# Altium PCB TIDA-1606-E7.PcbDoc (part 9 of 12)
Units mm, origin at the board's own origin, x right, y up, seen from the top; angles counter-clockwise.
Board outline 270 x 345 mm, 4 copper layers (Top Layer, Signal Layer 1, Signal Layer 2, Bottom Layer), stack 1.69 mm thick; 1263 components, 574 nets, 3595 pads, 4069 vias.
Unrouted connection lines stored in the file: 1719.

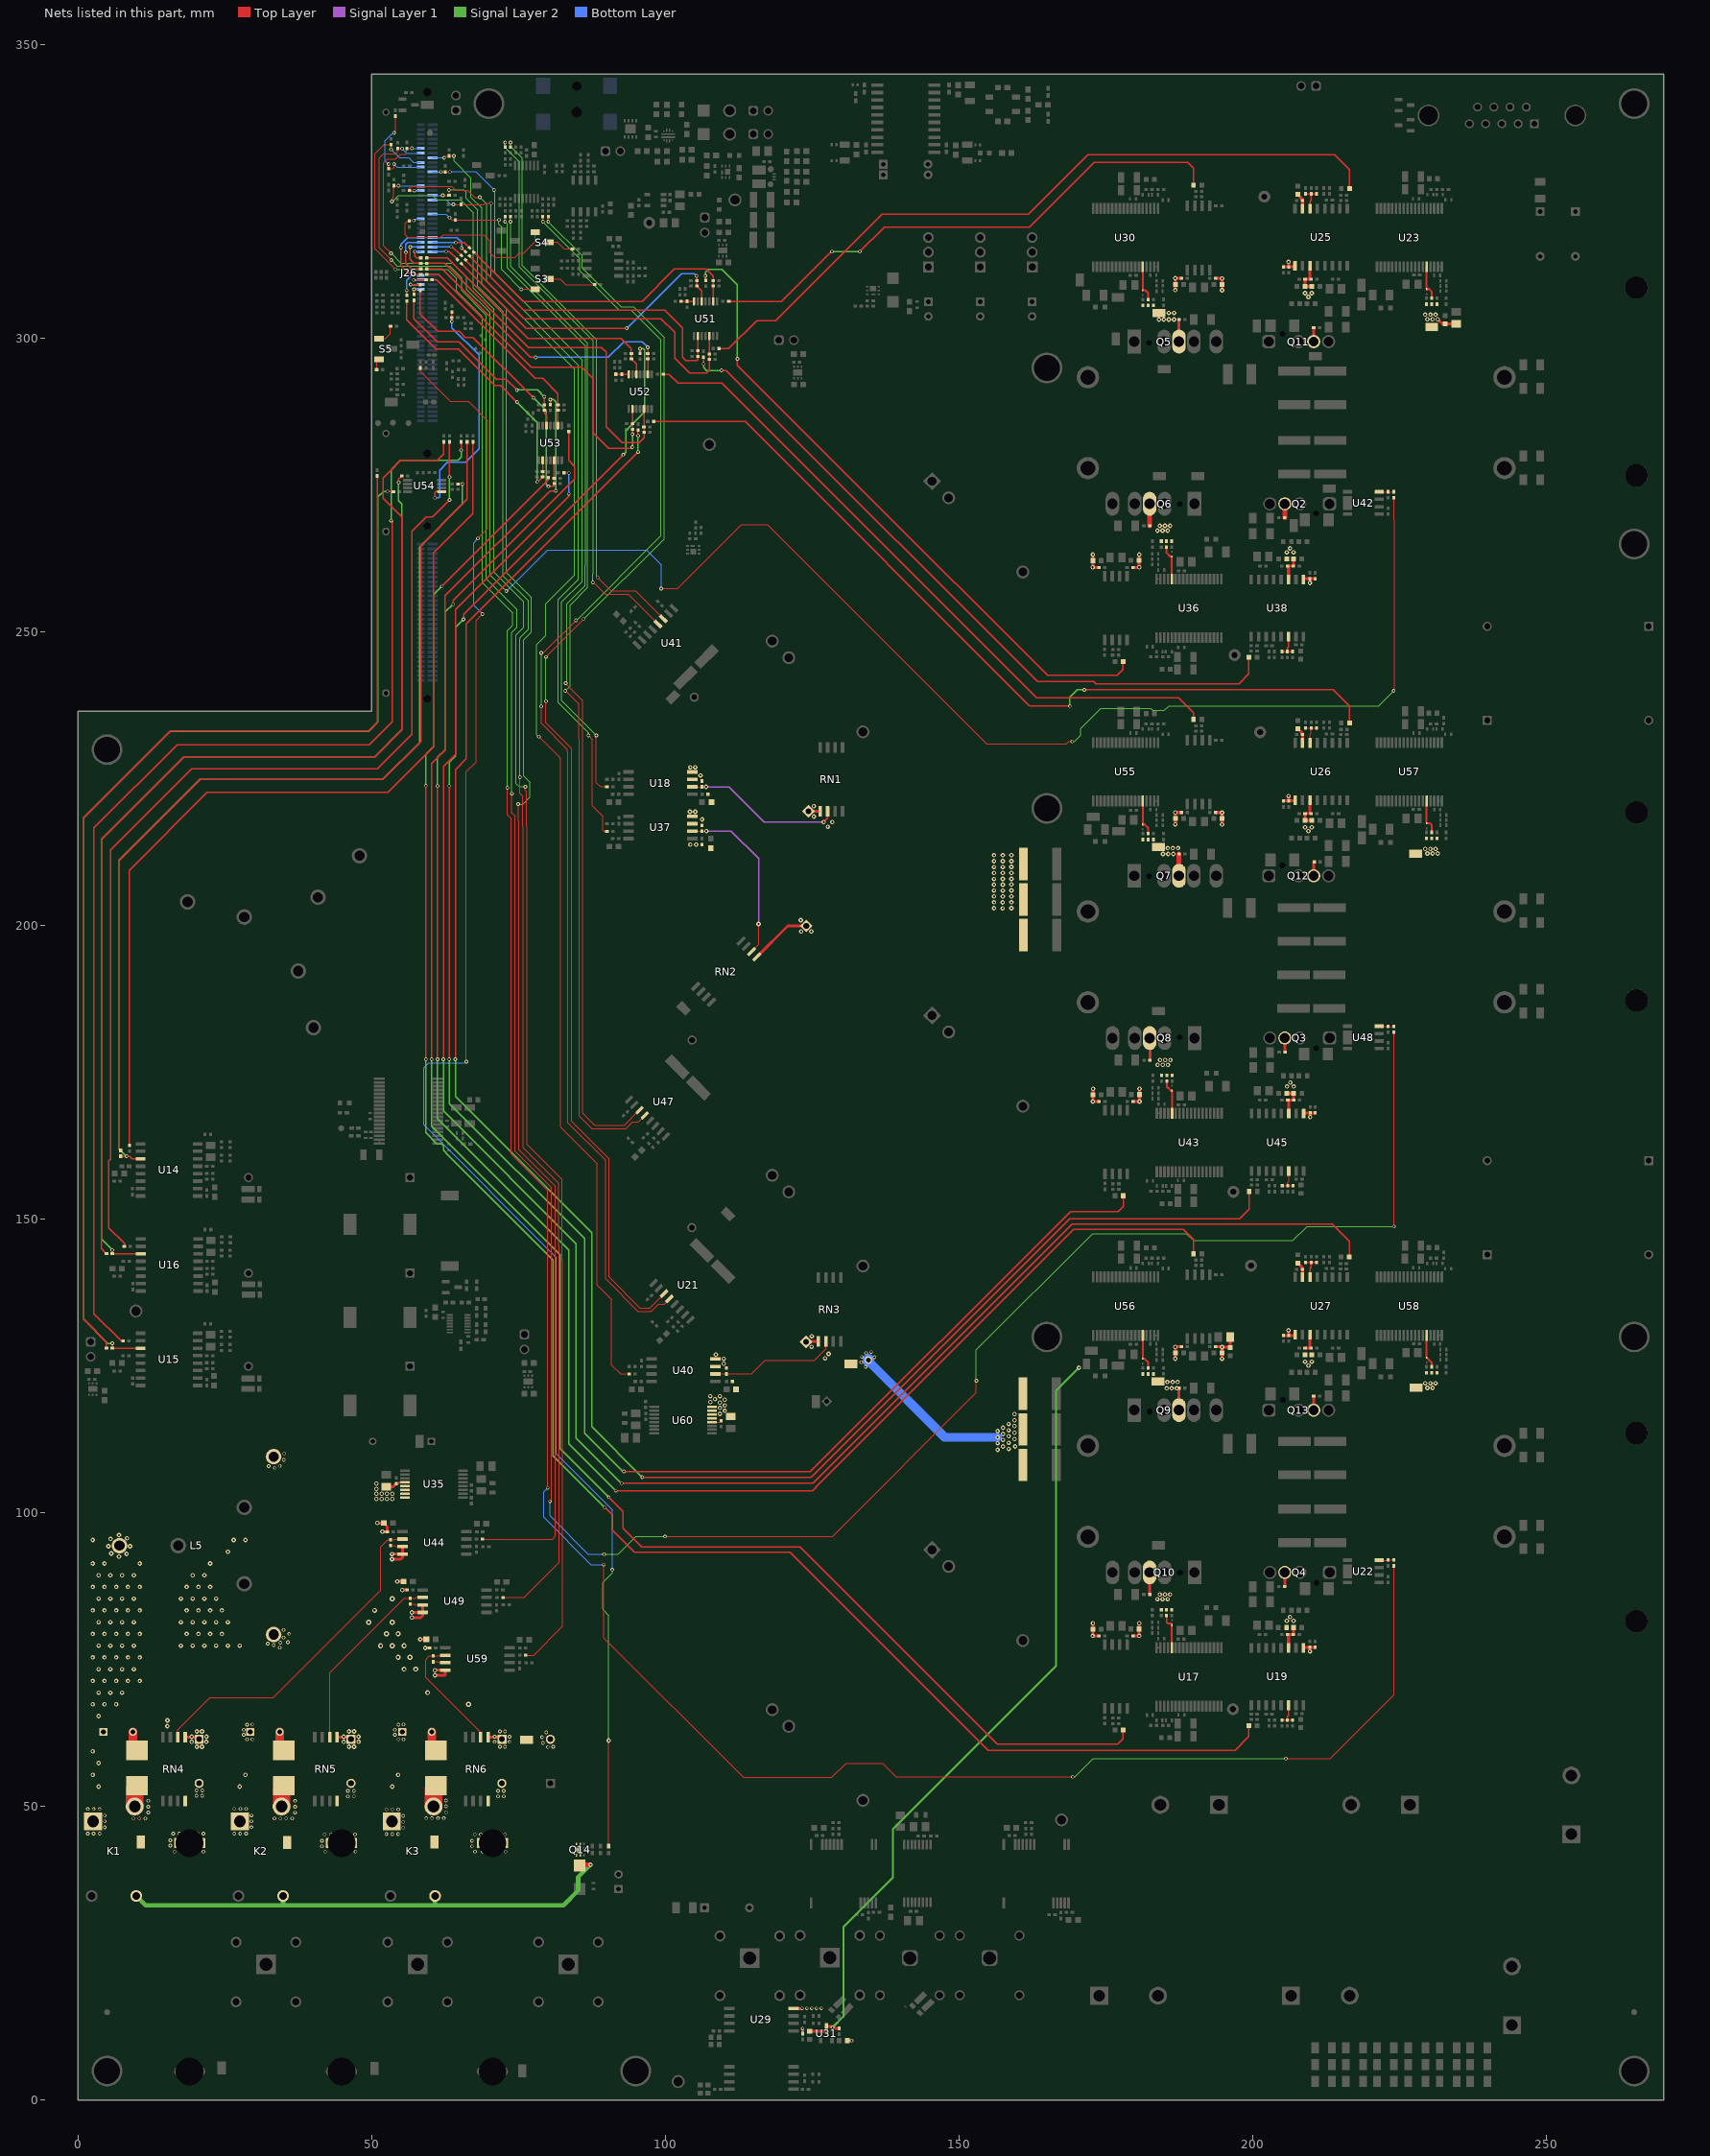
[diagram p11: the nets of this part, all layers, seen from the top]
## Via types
v1: diameter 0.762, hole 0.356, Top Layer to Bottom Layer, tented both sides, 2809 vias
v2: diameter 0.61, hole 0.356, Top Layer to Bottom Layer, tented both sides, 1209 vias
v3: diameter 0.864, hole 0.406, Top Layer to Bottom Layer, tented both sides, 15 vias
v4: diameter 0.5, hole 0.2, Top Layer to Bottom Layer, tented both sides, 12 vias
v5: diameter 0.5, hole 0.2, Top Layer to Bottom Layer, 12 vias
v6: diameter 0.305, hole 0.152, Top Layer to Bottom Layer, tented both sides, 12 vias

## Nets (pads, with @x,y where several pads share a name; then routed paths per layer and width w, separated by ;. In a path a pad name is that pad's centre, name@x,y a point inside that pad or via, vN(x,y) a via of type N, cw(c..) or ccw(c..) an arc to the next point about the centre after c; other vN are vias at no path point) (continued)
PIN42_AIN: C489.1 J26.79 S4.1 | length 33
  Top Layer w0.203: C489.1@56.447,319.827 C489.1@56.474,319.8 ; v2(57.202,320.099) 56.552,320.099 C489.1@56.452,320 56.142,320 55.728,319.585 55.728,317.646 56.127,317.246 61.796,317.246 62.171,317.621 69.135,317.621 70.106,316.65 70.106,314.672 70.967,313.811 74.46,313.811 75.169,314.52 75.923,314.52 77.901,316.499 S4.1@77.901,318.135
  Bottom Layer w0.203: v2(57.202,320.099) 57.202,320.128 57.459,320.385 J26.79@58.402,320.385
PIN76: R449.2 S5.1 | length 3.6
  Top Layer w0.203: S5.1@51.302,299.987 52.416,299.987 53.25,300.821 R449.2@53.25,302.1
PIN96: R467.2 S5.3 | length 2
  Top Layer w0.203: R467.2@50.886,294.7 50.886,296.071 S5.3@51.302,296.487
PTCR_L1: R89.2 R90.1 | length 3.7
  Top Layer w1.5: R90.1@9.375,60.181 R89.2@9.375,62.729
  Top Layer w2: R90.1@9.375,60.181 R90.1@10.221,59.336
PTCR_L2: R91.2 R92.1 | length 3.5
  Top Layer w1.5: R92.1@34.374,59.711 R91.2@34.374,62.729
  Top Layer w2: R92.1@34.374,59.711 R92.1@34.749,59.336
PTCR_L3: R94.2 R95.1 | length 3.5
  Top Layer w1.5: R95.1@60.26,59.711 R94.2@60.26,62.729
  Top Layer w2: R95.1@60.26,59.711 R95.1@60.635,59.336
PWM1_BUF_L1: R101.2 R246.2 | length 120.7
  Top Layer w0.229: v2(106.546,295.672) R101.2@106.546,296.846 ; v2(109.587,294.573) 110.44,294.573 115.666,289.347 163.408,241.605 172.943,241.605 173.348,241.2 197.7,241.2 199.398,242.898 R246.2@199.398,245.739
  Signal Layer 2 w0.229: v2(106.546,295.672) 106.546,295.113 107.086,294.573 v2(109.587,294.573)
  Bottom Layer w0.229: v2@109.386,294.573 v2(109.587,294.573)
PWM1_BUF_L2: R106.2 R264.2 | length 329.7
  Top Layer w0.229: v2(64.288,177.254) 64.288,223.6 64.288,226.588 66.154,228.454 66.154,251.424 95.4,280.67 v2(95.406,280.67) ; v2(95.406,283.439) R106.2@95.406,284.429 ; v2(96.123,106.1) 124.9,106.1 125,106.2 168.876,150.076 197.776,150.076 199.439,151.739 R264.2@199.439,154.773
  Signal Layer 2 w0.229: v2(64.288,177.254) 64.288,170.968 87.522,147.734 87.522,114.689 96.111,106.1 v2(96.123,106.1) ; v2(95.406,280.67) v2(95.406,283.439)
PWM1_BUF_L3: R112.2 R157.2 | length 328.3
  Top Layer w0.229: v2(59.254,177.254) v2(59.254,223.854) ; v2(61.972,257.785) 80.115,275.928 R112.2@80.115,276.32 ; v2(89.739,100.921) 89.739,100.965 90.955,99.749 90.955,97.125 94.78,93.3 121.3,93.3 155,59.6 197.071,59.6 199.4,61.929 R157.2@199.4,63.778
  Signal Layer 2 w0.229: v2(59.254,177.254) 59.254,164.774 61.148,162.88 61.916,162.88 62.28,162.515 62.28,161.748 63.116,160.912 63.117,160.912 80.922,143.108 80.922,109.738 v2(89.739,100.921) ; v2(59.254,223.854) 59.254,229.154 60.585,230.485 60.585,256.399 v2(61.972,257.785)
PWM1_L1: C461.1 R326.1 R376.2 U51.2 | length 53.2
  Top Layer w0.229: R326.1@66.716,314.065 75.956,304.825 99.945,304.825 102.95,301.821 102.95,296.842 103.124,296.667 103.124,296.665 103.522,296.267 103.525,296.267 103.534,296.257 105.38,296.257 105.593,296.47 R376.2@105.593,296.946 C461.1@105.593,297.895 U51.2@105.593,300.431
PWM1_L2: C465.1 R343.2 R389.2 U52.2 | length 59.3
  Top Layer w0.229: R343.2@59.402,310.918 61.387,310.918 77.234,295.071 85.81,295.071 87.738,293.143 87.738,283.925 90.363,281.3 94.202,281.3 v2(94.402,281.5) ; v2(94.452,283.7) R389.2@94.452,284.529 C465.1@94.452,285.478 U52.2@94.452,288.013
  Signal Layer 2 w0.229: v2@94.452,281.55 v2(94.452,283.7)
  Bottom Layer w0.229: v2(94.402,281.5) v2@94.452,281.55
PWM1_L3: C471.1 R414.2 R428.2 U53.2 | length 46.9
  Top Layer w0.229: R428.2@56.002,306.368 56.002,303.2 61.002,298.2 64.803,298.2 71.003,292 71.974,292 v2(74.8,289.174) ; v2(78.232,275.59) 78.332,275.59 R414.2@79.162,276.42 U53.2@79.162,279.273
  Signal Layer 2 w0.229: v2(74.8,289.174) 78.232,285.742 v2(78.232,275.59)
PWM1L1: J26.72 R326.2 | length 7.2
  Top Layer w0.229: v2(65.37,315.4) 65.998,314.772 R326.2@66.009,314.772
  Bottom Layer w0.229: J26.72@60.402,317.185 64.602,317.185 65.37,316.418 v2(65.37,315.4)
PWM1L2: J26.71 R343.1 | length 11.7
  Top Layer w0.229: v2(55.002,315.5) 55.002,312.463 56.547,310.918 R343.1@58.271,310.918 ; R343.1@58.402,310.918 R343.1@58.271,310.918 ; R343.1@58.402,311.05 R343.1@58.271,310.918
  Bottom Layer w0.229: v2(55.002,315.5) 55.002,316 56.188,317.185 J26.71@58.402,317.185 J26.71@58.387,317.2
PWM1L3: J26.63 R428.1 | length 5.3
  Top Layer w0.229: R428.1@56.002,307.368 v2(56.002,308.2)
  Bottom Layer w0.229: v2(56.002,308.2) 56.002,309.912 56.876,310.785 J26.63@58.402,310.785
PWM2_BUF_L1: R102.2 R196.2 | length 125.3
  Top Layer w0.229: R102.2@109.193,298.296 110.827,298.296 115.593,303.062 118.808,303.062 136.946,321.2 161.868,321.2 171.998,331.33 213.959,331.33 216.529,328.76 R196.2@216.529,325.518
PWM2_BUF_L2: R107.2 R210.2 | length 144.6
  Top Layer w0.229: R107.2@98.052,285.879 113.643,285.879 161.988,237.534 162.107,237.415 v2(168.91,237.415) ; v2(171.374,240.182) 171.413,240.222 213.765,240.222 216.531,237.456 R210.2@216.531,234.55
  Signal Layer 2 w0.229: v2(168.91,237.415) 168.91,238.91 170.182,240.182 v2(171.374,240.182)
PWM2_BUF_L3: R114.2 R211.2 | length 340.5
  Top Layer w0.203: R114.2@82.762,277.138 v2(83.602,277.138)
  Top Layer w0.229: v2(62.254,177.254) 62.254,225.017 62.254,227.112 64.34,229.198 64.34,253.842 82.98,272.483 82.982,272.483 83.602,273.103 v2(83.602,273.558) ; v2(92.6,105.1) 125.2,105.1 125.9,105.8 169.3,149.2 213.595,149.2 216.495,146.299 R211.2@216.495,143.6
  Signal Layer 2 w0.229: v2(62.254,177.254) 62.254,168.446 84.822,145.878 84.822,112.778 92.5,105.1 v2(92.6,105.1) ; v2(83.602,277.138) v2@83.66,277.081
  Bottom Layer w0.229: v2(83.602,273.558) v2(83.602,277.138)
PWM2_L1: C462.1 R377.2 R399.1 U51.5 | length 58.1
  Top Layer w0.229: R399.1@65.993,313.41 76.003,303.4 99.302,303.4 101.637,301.066 101.637,296.666 104.202,294.1 107.017,294.1 107.543,294.626 C462.1@107.543,297.346 U51.5@107.543,300.431
PWM2_L2: C466.1 R392.2 R404.2 U52.5 | length 62.3
  Top Layer w0.229: R404.2@59.402,312.797 62.464,312.797 76.783,298.478 89.2,298.478 89.963,297.716 89.963,284.992 92.641,282.313 95.627,282.313 96.402,283.088 C466.1@96.402,284.929 U52.5@96.402,288.013
PWM2_L3: C472.1 R415.2 R430.2 U53.5 | length 50.9
  Top Layer w0.229: R430.2@58.302,308.185 58.302,304.2 61.302,301.2 64.952,301.2 65.963,300.189 67.299,300.189 77.565,289.923 v2(77.565,289.936) ; v2(80.115,274.828) 81.119,274.828 81.137,274.846 R415.2@81.137,275.288 81.112,275.263 C472.1@81.112,276.188 U53.5@81.112,279.273
  Signal Layer 2 w0.229: v2(77.565,289.936) 79.784,287.717 79.784,275.159 v2(80.115,274.828)
PWM2L1: J26.68 R399.2 | length 5.5
  Top Layer w0.229: v2(63.602,315.625) 63.778,315.625 R399.2@65.286,314.117
  Bottom Layer w0.229: J26.68@60.402,315.585 60.441,315.625 v2(63.602,315.625)
PWM2L2: J26.67 R404.1 | length 6.1
  Top Layer w0.229: v2@56.67,315.585 v2(56.589,315.585) 56.589,313.454 57.245,312.797 R404.1@58.402,312.797
  Bottom Layer w0.229: v2(56.589,315.585) J26.67@58.402,315.585
PWM2L3: J26.59 R430.1 | length 3.4
  Top Layer w0.229: v2(56.666,309.185) R430.1@58.302,309.185
  Bottom Layer w0.229: v2(56.666,309.185) J26.59@58.402,309.185
PWM3_BUF_L1: R103.2 R224.2 | length 92.3
  Top Layer w0.229: R103.2@110.846,306.331 119.834,306.331 128.304,314.8 v2(128.412,314.8) ; v2(133.148,314.8) 137.348,319 162.054,319 173.054,330 189.016,330 189.975,329.04 R224.2@189.975,326.11
  Signal Layer 2 w0.229: v2(128.412,314.8) v2(133.148,314.8)
PWM3_BUF_L2: R108.2 R226.2 | length 115.3
  Top Layer w0.229: R108.2@99.706,293.913 100.704,293.913 102.218,292.4 109.627,292.4 163.233,238.794 187.468,238.794 189.977,236.285 R226.2@189.977,235.142
PWM3_BUF_L3: R116.2 R242.2 | length 323
  Top Layer w0.229: v2(61.254,177.254) v2(61.254,223.8) ; v2(63.902,254.759) 63.902,255.369 84.625,276.091 84.625,278.224 83.601,279.247 R116.2@83.601,284.173 ; v2(91.6,103.8) 125.066,103.8 126.422,105.156 169.571,148.305 188.248,148.305 189.977,146.576 R242.2@189.977,144.147
  Signal Layer 2 w0.229: v2(61.254,177.254) 61.254,167.146 83.622,144.778 83.622,111.778 v2(91.6,103.8) ; v2(61.254,223.8) 61.254,228.654 62.548,229.948 62.548,253.405 v2(63.902,254.759)
PWM3_L1: C463.1 R379.2 R390.1 U51.9 | length 51.3
  Top Layer w0.229: R390.1@67.407,314.735 75.826,306.316 96.083,306.316 101.584,311.816 106.993,311.816 108.21,310.6 108.21,309.882 R379.2@108.193,309.865 C463.1@108.193,308.945 U51.9@108.193,306.331
PWM3_L2: C467.1 R393.2 R398.2 U52.9 | length 50
  Top Layer w0.229: R393.2@59.402,311.858 62.033,311.858 77.094,296.796 v2(77.978,296.796) ; U52.9@97.052,293.913 C467.1@97.052,296.528 R398.2@97.052,297.448 v2(97.052,298.5)
  Bottom Layer w0.229: v2(77.978,296.796) 90.284,296.796 92.967,299.48 96.073,299.48 v2(97.052,298.5)
PWM3_L3: C473.1 R422.2 R429.2 U53.9 | length 34.9
  Top Layer w0.229: R429.2@60.302,309.985 61.117,309.985 77.902,293.2 79.201,293.2 81.762,290.639 R422.2@81.762,288.707 C473.1@81.762,287.787 U53.9@81.762,285.173
PWM3L1: J26.70 R390.2 | length 6.7
  Top Layer w0.229: v2(64.34,316.362) 65.78,316.362 R390.2@66.7,315.443
  Bottom Layer w0.229: J26.70@60.402,316.385 64.316,316.385 v2(64.34,316.362)
PWM3L2: J26.69 R393.1 | length 8.9
  Top Layer w0.229: v2(55.852,314.7) 55.852,312.874 56.869,311.858 R393.1@58.402,311.858
  Bottom Layer w0.229: v2(55.852,314.7) 55.852,316.063 56.175,316.385 J26.69@58.402,316.385 J26.69@58.388,316.399
PWM3L3: J26.61 R429.1 | length 3.3
  Top Layer w0.229: v2(57.202,309.985) R429.1@59.302,309.985
  Bottom Layer w0.229: v2(57.202,309.985) J26.61@58.402,309.985
PWM4_BUF_L1: R105.2 R260.2 | length 111.2
  Top Layer w0.229: v2(106.865,310.675) 106.865,309.922 R105.2@106.893,309.893 ; v2(112.302,296.523) 112.302,295.46 133.708,274.054 165.136,242.626 174.273,242.626 174.277,242.622 176.95,242.622 177.985,243.658 R260.2@177.985,245
  Signal Layer 2 w0.229: v2(106.865,310.675) 106.865,311.31 107.331,311.776 109.659,311.776 112.302,309.132 v2(112.302,296.523)
PWM4_BUF_L2: R110.2 R268.2 | length 324.3
  Top Layer w0.229: v2(63.254,177.254) v2(63.254,223.8) ; v2(65.681,252.185) 65.681,253.02 v2(92.883,280.223) ; v2(93,107.088) 124.753,107.088 124.765,107.1 169.015,151.35 177.131,151.35 178.027,152.246 R268.2@178.027,154.034 ; R110.2@95.752,297.476 v2(95.752,298.257)
  Signal Layer 2 w0.229: v2(63.254,177.254) 63.254,169.746 86.285,146.715 86.285,113.603 92.8,107.088 v2(93,107.088) ; v2(63.254,223.8) 63.254,227.87 64.34,228.956 64.34,250.844 v2(65.681,252.185) ; v2(92.883,280.223) 93.302,280.642 93.302,284.328 96.5,287.525 96.5,298.028 96.271,298.257 v2(95.752,298.257)
PWM4_BUF_L3: R168.2 R174.2 | length 318.9
  Top Layer w0.229: v2(60.254,177.254) 60.254,226 60.254,227.654 62.548,229.948 62.548,256.188 80.426,274.066 v2(81.393,274.066) ; R168.2@80.462,288.735 v2(80.462,289.597) ; v2(90.4,102.7) 92.802,100.298 92.802,97.416 96.018,94.2 123.003,94.2 156.519,60.684 156.591,60.612 177.031,60.612 177.995,61.577 R174.2@177.995,63.047
  Signal Layer 2 w0.229: v2(60.254,177.254) 60.254,165.846 82.122,143.978 82.122,110.941 90.363,102.7 v2(90.4,102.7) ; v2(80.462,289.597) 80.989,289.597 81.393,289.193 v2(81.393,274.066)
PWM4_L1: C464.1 R378.2 R425.1 U51.12 | length 53.3
  Top Layer w0.229: R425.1@65.334,312.744 76.327,301.752 v2(93.472,301.752) ; v2(105.348,310.675) 105.396,310.627 R378.2@105.396,309.882 C464.1@105.396,308.946 106.243,308.1 U51.12@106.243,306.331
  Bottom Layer w0.229: v2(93.472,301.752) 102.793,311.073 104.95,311.073 v2(105.348,310.675)
PWM4_L2: C468.1 R403.2 R426.2 U52.12 | length 46
  Top Layer w0.229: R426.2@59.402,313.737 62.942,313.737 76.632,300.046 92.47,300.046 94.256,298.26 R403.2@94.256,297.465 C468.1@94.256,296.529 95.102,295.682 U52.12@95.102,293.913
PWM4_L3: C474.1 R424.2 R431.2 U53.12 | length 35.9
  Top Layer w0.229: R431.2@57.241,306.5 57.241,303.362 61.202,299.4 64.902,299.4 71.232,293.07 72.936,293.07 v2(74.76,291.247) ; v2(79.437,290.068) R424.2@79.437,288.707 C474.1@79.437,287.772 79.418,287.753 79.418,287.335 79.812,286.942 U53.12@79.812,285.173
  Signal Layer 2 w0.229: v2(74.76,291.247) 78.258,291.247 v2(79.437,290.068)
PWM4L1: J26.66 R425.2 | length 4.8
  Top Layer w0.229: v2(62.692,314.785) 63.293,314.785 R425.2@64.627,313.451
  Bottom Layer w0.229: J26.66@60.402,314.785 v2(62.692,314.785)
PWM4L2: J26.65 R426.1 | length 2.9
  Top Layer w0.229: v2(57.402,314.8) 57.402,314.068 57.734,313.737 R426.1@58.402,313.737
  Bottom Layer w0.229: v2(57.402,314.8) 58.387,314.8 J26.65@58.402,314.785
PWM4L3: J26.57 R431.1 | length 2
  Top Layer w0.229: R431.1@57.241,307.5 v2(57.241,308.385)
  Bottom Layer w0.229: v2(57.241,308.385) J26.57@58.402,308.385
REF_MID1: C247.1 C248.2 C250.2 C252.1 Q5.3 R85.1 R248.1 R507.2 R511.2 TP52.1 | length 9.9
  Top Layer w0.5: v1(186.876,308.244) C248.2@186.876,309.223 v1(186.876,310.268) C247.1@187.925,310.268 ; Q5.3@187.503,299.48 R85.1@187.503,303.23 ; C250.2@193.736,310.268 194.78,310.268 v1(194.825,310.224) C252.1@194.825,309.223 v1(194.825,308.231)
  other v1: 184.087,303.224 184.924,303.23 185.763,303.224 186.653,303.224 185.763,304.357 186.648,304.357
REF_MID2: C254.1 C255.2 C257.2 C259.1 Q7.3 R86.1 R263.1 R531.2 R565.2 TP53.1 | length 9.9
  Top Layer w0.5: v1(186.878,217.276) C255.2@186.878,218.255 v1(186.878,219.3) C254.1@187.927,219.3 ; C257.2@193.738,219.3 194.782,219.3 v1(194.827,219.255) C259.1@194.827,218.255 v1(194.827,217.263)
  Top Layer w0.8: Q7.3@187.505,208.511 R86.1@187.505,212.262
  other v1: 184.785,212.239 185.661,212.239 186.537,212.239 185.578,213.237 186.454,213.237 187.33,213.237
REF_MID3: C235.1 C236.2 C237.2 C242.1 C261.1 C262.2 C264.2 C266.1 C270.2 Q9.3 R87.1 R254.2 R539.2 R566.1 R567.2 TP57.1 U29.4 U31.3 | length 149.7
  Top Layer w0.5: U29.4@121.85,15.63 v2@123.321,15.63 ; C270.2@123.404,11.357 v2(123.404,12.223) ; C237.2@124.604,11.757 125.699,11.757 125.704,11.752 127.462,11.752 U31.3@127.462,12.606 v2@128.412,12.606 ; v2@128.762,12.257 C235.1@129.619,12.257 ; v1(186.878,126.281) C262.2@186.878,127.26 v1(186.878,128.305) C261.1@187.927,128.305 ; Q9.3@187.505,118.506 R87.1@187.505,121.266 ; C264.2@193.738,128.305 194.782,128.305 v1(194.827,128.26) ; v1(194.827,126.268) C266.1@194.827,127.26 v1(194.827,128.26) ; C242.1@196.216,128.2 196.156,128.26 v1(194.827,128.26)
  Top Layer w0.508: C242.1@196.216,128.2 R254.2@196.216,129.943
  Signal Layer 2 w0.35: v2(128.504,12.405) 130.353,14.254 130.353,29.48 138.8,37.927 138.8,46.175 166.571,73.946 166.571,120.847 v1(170.465,124.742)
  other v1: 185.38,121.249 186.257,121.249 187.133,121.249 185.53,122.311 186.406,122.311 187.282,122.311
  other v2: 131.746,10.157 123.321,15.65 124.14,15.65 124.959,15.65 125.778,15.65 126.597,15.65
REF_SN_L1: C140.1 C141.2 C291.1 C293.2 C296.2 C300.2 C304.1 C307.2 C309.1 Q2.3 Q6.3 R88.1 R93.1 R154.1 R259.2 R277.2 R298.1 U38.1 U38.3 | length 19.7
  Top Layer w0.4: C296.2@205.989,261.258 C291.1@206.977,261.258
  Top Layer w0.5: v1(172.833,263.198) C309.1@172.833,262.198 172.833,261.091 v1(172.792,261.05) 172.813,261.029 C307.2@173.857,261.029 ; C304.1@179.659,261.029 180.704,261.029 v1(180.726,261.05) C141.2@180.726,262.217 v1@180.726,263.052 ; R88.1@205.51,269.474 R88.1@205.517,269.481 ; C296.2@205.989,261.254 206.148,261.095 U38.3@206.148,258.972 U38.3@206.132,258.987 ; C291.1@206.977,261.254 206.977,261.258 206.977,262.435 C293.2@206.992,262.45 ; U38.1@208.688,258.972 208.813,259.098 R298.1@210.664,259.098 ; v1(209.798,258.398) C300.2@209.798,259.098
  Top Layer w0.8: R93.1@182.513,268.1 Q6.3@182.513,271.85 ; R88.1@205.517,269.481 Q2.3@205.517,271.85
  other v1: 180.726,263.198 205.852,263.593 206.992,263.593 206.41,264.264 183.824,267.3 184.7,267.3 185.576,267.3 184.234,268.098 185.11,268.098 185.986,268.098
REF_SN_L2: C241.1 C279.2 C334.1 C336.2 C339.2 C343.2 C347.1 C350.2 C352.1 Q3.3 Q8.3 R99.1 R283.1 R284.2 R320.2 R338.1 R350.1 U45.1 U45.3 | length 20.9
  Top Layer w0.5: v1(172.874,172.232) C352.1@172.874,171.232 172.833,171.191 v1(172.833,170.084) 172.863,170.055 C350.2@173.891,170.055 ; C347.1@179.701,170.063 180.746,170.063 v1(180.767,170.084) C279.2@180.767,171.251 v1(180.767,172.232) ; R350.1@182.555,177.134 Q8.3@182.555,180.842 ; R99.1@205.552,178.508 Q3.3@205.552,180.849 ; C241.1@205.874,171.484 C336.2@207.034,171.484 207.034,170.303 C334.1@207.018,170.288 207.015,170.292 C339.2@206.031,170.292 206.189,170.133 U45.3@206.189,168.006 ; U45.1@208.729,168.006 208.855,168.132 C343.2@209.839,168.132 ; v1(209.839,167.432) C343.2@209.839,168.132 ; R338.1@210.705,168.132 C343.2@209.839,168.132
  other v1: 205.894,172.627 207.034,172.627 206.452,173.298 183.866,176.334 184.742,176.334 185.618,176.334 184.276,177.132 185.151,177.132 186.028,177.132
REF_SN_L3: C147.1 C149.2 C151.1 C152.2 C153.2 C156.2 C160.1 C163.2 C165.1 Q4.3 Q10.3 R80.1 R81.1 R147.1 R149.2 R151.2 R169.1 U19.1 U19.3 | length 19.5
  Top Layer w0.5: v1(172.835,81.234) C165.1@172.835,80.234 172.835,79.128 v1(172.794,79.087) 172.823,79.057 C163.2@173.851,79.057 ; C160.1@179.661,79.065 180.706,79.065 v1(180.728,79.087) C153.2@180.728,80.254 v1(180.728,81.234) ; R81.1@182.515,86.136 Q10.3@182.515,89.887 ; R80.1@205.512,87.51 Q4.3@205.512,89.88 ; U19.3@206.15,77.011 206.15,79.132 206.308,79.29 C147.1@206.979,79.29 206.994,79.306 C149.2@206.994,80.486 ; U19.1@208.69,77.011 208.813,77.134 C156.2@209.8,77.134 ; v1(209.8,76.434) C156.2@209.8,77.134 ; R169.1@210.666,77.134 C156.2@209.8,77.134
  other v1: 205.854,81.63 206.994,81.63 206.412,82.301 183.826,85.336 184.702,85.336 185.578,85.336 184.236,86.134 185.112,86.134 185.988,86.134
REF_VDC-1: C181.1 C187.1 C189.2 C191.1 C192.2 C196.2 Q11.3 R82.1 R186.2 R189.2 R191.2 R208.1 R555.1 TP43.1 U25.1 U25.3 | length 14.2
  Top Layer w0.5: R208.1@205.284,312.208 C196.2@206.152,312.208 ; v1(206.152,313.062) C196.2@206.152,312.208 ; U25.1@207.11,312.208 C196.2@206.152,312.208 ; U25.3@209.8,312.358 209.8,310.231 C192.2@209.959,310.072 C187.1@208.971,310.072 C189.2@208.971,308.895 C191.1@210.098,308.895 ; Q11.3@210.438,299.487 R82.1@210.438,301.856 ; v1(231.55,303.268) 232.318,302.5 C181.1@232.8,302.5 R189.2@234.7,302.5
  other v1: 229.798,303.268 230.674,303.268 229.423,304.068 230.3,304.068 231.176,304.068 209.538,307.066 208.956,307.737 210.096,307.737
REF_VDC-2: C200.1 C202.2 C205.2 C206.1 C209.2 Q12.3 R83.1 R223.1 R253.2 R527.1 R535.2 TP44.1 U26.1 U26.3 | length 10.7
  Top Layer w0.4: C200.1@208.973,219.104 C205.2@209.961,219.104
  Top Layer w0.5: R223.1@205.286,221.264 C209.2@206.154,221.264 ; C209.2@206.154,221.24 C209.2@206.154,221.264 ; v1(206.154,222.093) C209.2@206.154,221.264 ; U26.1@207.137,221.264 C209.2@206.154,221.264 ; C200.1@208.973,219.108 208.973,219.104 C202.2@208.973,217.927 C206.1@210.1,217.927 ; U26.3@209.802,221.39 209.802,219.263 C205.2@209.961,219.104 ; Q12.3@210.433,208.511 210.433,210.881 R83.1@210.44,210.888
  other v1: 229.8,212.3 230.676,212.3 231.552,212.3 229.425,213.1 230.302,213.1 231.178,213.1 209.54,216.097 208.958,216.768 210.098,216.768
REF_VDC-3: C213.1 C215.2 C218.2 C219.1 C228.2 Q13.3 R84.1 R245.1 R302.2 R556.1 R557.2 TP48.1 U27.1 U27.3 | length 8.6
  Top Layer w0.5: R245.1@205.286,130.244 C228.2@206.154,130.244 ; v1(206.154,131.098) C228.2@206.154,130.244 ; U27.1@207.262,130.394 207.112,130.244 C228.2@206.154,130.244 ; C213.1@208.973,128.109 C218.2@209.961,128.109 209.802,128.267 U27.3@209.802,130.394 ; Q13.3@210.433,117.516 210.433,119.895 R84.1@210.438,119.9
  other v1: 229.8,121.305 230.676,121.305 229.425,122.105 230.302,122.105 231.178,122.105 209.54,125.102 208.958,125.773 210.098,125.773
RLAY_1: K1.1 L5.EI R89.1
  other v1: 3.548,53.416 2.548,55.416 3.548,57.416 2.548,59.416 3.548,65.416 2.548,67.416 4.548,67.416 6.548,67.416 3.548,69.416 5.548,69.416 7.548,69.416 2.548,71.416 4.548,71.416 6.548,71.416 8.548,71.416 10.548,71.416 3.548,73.416 5.548,73.416 7.548,73.416 9.548,73.416 2.548,75.416 4.548,75.416 6.548,75.416 8.548,75.416 10.548,75.416 3.548,77.416 5.548,77.416 7.548,77.416 9.548,77.416 2.548,79.416 4.548,79.416 6.548,79.416 8.548,79.416 10.548,79.416 3.548,81.416 5.548,81.416 7.548,81.416 9.548,81.416 2.548,83.416 4.548,83.416 6.548,83.416 8.548,83.416 10.548,83.416 3.548,85.416 5.548,85.416 7.548,85.416 9.548,85.416 2.548,87.416 4.548,87.416 6.548,87.416 8.548,87.416 10.548,87.416 3.548,89.416 5.548,89.416 7.548,89.416 9.548,89.416 2.548,91.416 4.548,91.416 10.548,91.416 7.01,92.601 8.307,93.045 5.707,93.131 5.21,94.345 8.907,94.345 2.548,95.416 5.588,95.595 8.384,95.706 7.01,96.245
  other v2: 1.7,45.399 2.7,45.399 3.7,45.399 4.588,46.486 4.588,47.486 4.588,48.486 1.71,49.6 2.71,49.6 3.71,49.6
RLAY_2: K2.1 L5.EII R91.1
  other v1: 27.548,53.416 28.548,55.416 17.548,77.416 19.548,77.416 21.548,77.416 23.548,77.416 25.548,77.416 27.548,77.416 18.548,79.416 20.548,79.416 22.548,79.416 24.548,79.416 17.548,81.416 19.548,81.416 21.548,81.416 23.548,81.416 25.548,81.416 18.548,83.416 20.548,83.416 22.548,83.416 24.548,83.416 17.548,85.416 19.548,85.416 21.548,85.416 23.548,85.416 18.548,87.416 20.548,87.416 22.548,87.416 19.548,89.416 21.548,89.416 22.548,91.416 25.548,93.416 26.548,95.416 28.548,95.416
  other v2: 26.66,45.41 27.66,45.41 28.66,45.41 29.548,46.497 29.548,47.497 29.548,48.497 26.67,49.611 27.67,49.611 28.67,49.611 28.841,61.479 29.708,61.475 28.25,62.25 28.25,63.087 28.841,63.95 29.708,64 33.548,107.696 32.5,108 34.41,108.041 35.086,109.041 35.155,110.167
RLAY_3: K3.1 L5.EIII R94.1
  other v1: 53.548,53.416 54.548,55.416
  other v2: 52.542,45.335 53.542,45.335 54.542,45.335 55.43,46.422 55.43,47.422 55.43,48.422 52.552,49.536 53.552,49.536 54.552,49.536 54.591,61.479 55.457,61.475 54,62.25 54,63.087 54.591,63.95 55.457,64 34.374,77.072 33.35,77.505 32.35,77.773 34.5,77.934 35.789,78 35.047,78.78 35.998,79.417 35.047,80.1
RLIM: D7.1 R147.2 U17.32 | length 6.2
  Top Layer w0.305: R147.2@185.385,82.534 185.385,81.385 185.571,81.199 186.276,81.199 D7.1@186.276,80.914 U17.32@186.276,77.074
RLIM_MID1: D25.1 R248.2 U30.32 | length 6.2
  Top Layer w0.35: U30.32@181.328,312.215 D25.1@181.328,308.231 181.769,308.231 182.242,307.758 R248.2@182.242,306.646
RLIM_MID2: D26.1 R263.2 U55.32 | length 6.1
  Top Layer w0.35: U55.32@181.33,221.247 D26.1@181.33,217.263 181.639,217.263 182.244,216.658 R263.2@182.244,215.678
RLIM_MID3: D27.1 R566.2 U56.32 | length 6.1
  Top Layer w0.35: U56.32@181.33,130.251 D27.1@181.33,126.268 181.661,126.268 182.244,125.684 R566.2@182.244,124.682
RLIM_SN_L1: D14.1 R154.2 U36.32 | length 6
  Top Layer w0.35: R154.2@185.383,264.498 185.383,263.508 186.014,262.878 D14.1@186.274,262.878 U36.32@186.274,259.035
RLIM_SN_L2: D16.1 R283.2 U43.32 | length 6
  Top Layer w0.35: R283.2@185.424,173.532 185.424,172.598 186.111,171.912 D16.1@186.316,171.912 U43.32@186.316,168.069
RLIM_VDC-1: D19.1 R555.2 U23.32 | length 6
  Top Layer w0.35: U23.32@229.657,312.215 D19.1@229.657,308.426 230.073,308.426 230.555,307.944 R555.2@230.555,306.866
RLIM_VDC-2: D20.1 R527.2 U57.32 | length 6.1
  Top Layer w0.35: U57.32@229.659,221.247 229.659,217.458 230.261,217.458 230.557,217.162 R527.2@230.557,215.898
RLIM_VDC-3: D21.1 R556.2 U58.32 | length 5.7
  Top Layer w0.35: U58.32@229.659,130.251 229.659,126.463 D21.1@229.666,126.456 230.557,125.565 R556.2@230.557,124.902
RST_BOT_L1: C194.1 R200.1 R206.2 U25.14 | length 4.4
  Top Layer w0.229: C194.1@209.078,324.632 R200.1@209.992,324.632 ; U25.14@209.8,322.108 209.8,323.32 209.992,323.512 R200.1@209.992,324.632 ; R206.2@210.906,324.632 R200.1@209.992,324.632
RST_BOT_L2: C207.1 R215.1 R221.2 U26.14 | length 4.4
  Top Layer w0.203: C207.1@209.08,233.664 R215.1@209.994,233.664 ; U26.14@209.802,231.14 209.802,232.553 209.994,232.745 R215.1@209.994,233.664 ; R221.2@210.908,233.664 R215.1@209.994,233.664
RST_BOT_L3: C225.1 R230.1 R237.2 U27.14 | length 4.4
  Top Layer w0.229: C225.1@209.08,142.669 R230.1@209.994,142.669 ; U27.14@209.802,140.144 209.802,141.671 209.994,141.863 R230.1@209.994,142.669 ; R237.2@210.908,142.669 R230.1@209.994,142.669
RST_TOP_L1: C298.1 R291.1 R297.2 U38.14 | length 4.4
  Top Layer w0.229: R297.2@205.042,246.698 R291.1@205.956,246.698 ; U38.14@206.148,249.222 206.148,247.506 205.956,247.314 R291.1@205.956,246.698 ; C298.1@206.87,246.698 R291.1@205.956,246.698
RST_TOP_L2: C341.1 R330.1 R336.2 U45.14 | length 4.4
  Top Layer w0.203: R336.2@205.083,155.732 R330.1@205.997,155.732 ; U45.14@206.189,158.256 206.189,156.448 205.997,156.256 R330.1@205.997,155.732 ; C341.1@206.911,155.732 R330.1@205.997,155.732
RST_TOP_L3: C154.1 R161.1 R167.2 U19.14 | length 4.4
  Top Layer w0.229: R167.2@205.044,64.736 R161.1@205.958,64.736 ; U19.14@206.15,67.261 206.15,65.568 205.958,65.376 R161.1@205.958,64.736 ; C154.1@206.872,64.736 R161.1@205.958,64.736
RY_N: R113.1 R465.2 | length 282.2
  Top Layer w0.203: R465.2@58.317,295 58.317,294.423 63.464,289.276 66.524,289.276 69.8,286 69.8,267.632 v2(68.106,265.938) ; v2(66.154,176.854) 66.154,226.209 67.8,227.855 67.8,251.994 v2(68.89,253.084) ; R113.1@90.4,43.3 v1(90.4,61.25)
  Signal Layer 2 w0.203: v1(90.4,61.25) 90.4,82.55 89.364,83.586 89.364,88.156 91,89.792 v2(91,90.365)
  Bottom Layer w0.203: v2(66.154,176.854) 65.916,176.616 59.716,176.616 58.9,175.8 58.9,166.1 81.502,143.498 81.502,110.046 91,100.549 v2@91,90.164 ; v2(68.106,265.938) 67.407,265.239 67.407,254.568 v2(68.89,253.084)
SD_CLKI: R427.1 R432.1 U54.1 | length 41.1
  Top Layer w0.229: v2(60.8,272.9) 60.8,273.778 60.949,273.928 U54.1@61.951,273.928 U54.1@62,273.878 ; v2(63.686,302.9) R432.1@63.686,303.6 R427.1@63.686,304.518 R427.1@63.686,304.6
  Bottom Layer w0.229: v2(60.8,272.9) 61.468,272.9 61.602,273.034 61.602,277.576 62.926,278.9 66.024,278.9 68.326,281.202 68.326,297.204 63.686,301.844 v2(63.686,302.9)
SD_CLKI_IN_L1: R140.2 R471.1 | length 163.5
  Top Layer w0.229: R140.2@7.3,161.756 7,162.056 7,211.041 20.898,224.939 51.939,224.939 58.402,231.402 58.402,264.738 66.302,272.638 R471.1@66.302,282.42
SD_CLKI_IN_L2: R143.2 R477.1 | length 190.6
  Top Layer w0.229: R143.2@4.881,128.068 4.881,129.119 1,133 1,218.378 15.796,233.174 49.569,233.174 51.002,234.607 R477.1@51.002,276.6
SD_CLKI_IN_L3: R145.2 R481.1 | length 188.2
  Top Layer w0.229: R145.2@4.881,144.147 4,145.027 4,147.576 4,214.693 18.107,228.8 50.6,228.8 55.151,233.351 55.151,269.652 51.962,272.84 51.962,276.262 54.951,279.251 61.247,279.251 62.322,280.327 R481.1@62.322,282.42
SD_CLKI_OUT_L1: R140.1 R170.2 U14.11 | length 161.8
  Top Layer w0.229: R140.1@7.3,160.756 v2(8.3,160.756) 8.828,160.756 9.254,160.33 U14.11@10.691,160.33 U14.11@10.661,160.3 ; R170.2@64.737,275.228 v2(65.475,275.228)
  Signal Layer 2 w0.229: v2(8.3,160.756) 7,162.056 7,211.1 20.8,224.9 51.9,224.9 58.166,231.166 58.166,264.502 65.475,271.811 v2(65.475,275.228)
SD_CLKI_OUT_L2: R143.1 R192.2 U15.11 | length 195.8
  Top Layer w0.229: v2(5.881,128.895) R143.1@5.881,128.068 5.885,128.072 U15.11@10.691,128.072 ; v2(52.727,273.961) 53.704,273.961 R192.2@53.737,273.928
  Signal Layer 2 w0.229: v2(5.881,128.895) 5.105,128.895 1,133 1,218.378 15.757,233.135 49.53,233.135 51.118,234.722 51.118,273.015 52.063,273.961 v2(52.727,273.961)
SD_CLKI_OUT_L3: R145.1 R209.2 U16.11 | length 178.8
  Top Layer w0.229: v2(5.881,144.781) R145.1@5.881,144.147 10.732,144.147 U16.11@10.733,144.145 ; v2(54.632,275.5) 54.632,276.081 R209.2@55.151,276.6
  Signal Layer 2 w0.229: v2(5.881,144.781) 4,146.662 4,146.9 4,214.693 18.107,228.8 50.6,228.8 55.202,233.402 55.202,271.8 54.632,272.37 v2(54.632,275.5)
SD_Data_I_PCC_L1: R133.2 R469.1 | length 162.1
  Top Layer w0.229: R133.2@8.8,162.6 8.8,209.453 22.047,222.7 52.8,222.7 60.585,230.485 60.585,263.481 67.302,270.198 R469.1@67.302,282.42
SD_Data_I_PCC_L2: R135.2 R475.1 | length 206.2
  Top Layer w0.229: R135.2@7.7,129.342 7.37,129.342 2.744,133.968 2.744,135.8 2.744,216.644 16.909,230.809 49.584,230.809 53.502,234.728 53.502,268.824 v2(53.34,268.986) ; v2(65.28,280.978) R475.1@65.28,282.42
  Signal Layer 2 w0.229: v2(53.34,268.986) 53.349,268.995 53.349,277.649 54.951,279.251 64.734,279.251 65.28,279.797 v2(65.28,280.978)
SD_Data_I_PCC_L3: R138.2 R478.1 | length 181.3
  Top Layer w0.229: R138.2@7.915,145.415 7.915,145.932 5.3,148.547 5.3,160 5.548,160.248 5.548,212.887 19.36,226.7 51,226.7 56.902,232.602 56.902,267.15 59.363,269.611 60.411,269.611 v2(63.302,272.502) ; v2(63.302,276.4) R478.1@63.302,282.42
  Signal Layer 2 w0.229: v2(63.302,272.502) v2(63.302,276.4)
SN_Relays: D5.2 K1.4 K2.4 K3.4 Q14.1 Q14.2 Q14.5 Q14.6 Q14.8 | length 87.5
  Top Layer w0.75: D5.2@85.364,39.9 D5.2@85.446,39.982 85.564,40.1 v1(87.3,40.1)
  Signal Layer 2 w0.75: K1.4@9.95,34.797 11.547,33.2 34.9,33.2 ; K2.4@34.949,34.797 34.949,33.249 34.9,33.2 ; K3.4@60.835,34.797 60.835,33.335 60.7,33.2 ; v1(87.3,40.1) 85.2,38 85.2,35.7 82.7,33.2 60.7,33.2 ; 34.9,33.2 60.7,33.2
Temp_SENSE_AMB: C103.1 J26.101 R129.1 | length 16.4
  Top Layer w0.203: v2(52.902,329.692) C103.1@52.902,328.914 53.64,328.914 53.848,329.122 v2(53.848,329.692) ; v2(53.848,335.026) 54.114,335.292 54.114,337.855 R129.1@54.107,337.862
  Bottom Layer w0.203: v2(52.902,329.692) 52.324,330.27 52.324,333.659 53.691,335.026 v2(53.848,335.026) ; v2(53.848,329.692) 54.344,329.196 58.392,329.196 J26.101@58.402,329.185
TEMP_SENSE_L1: C171.1 J26.109 R301.2 | length 311.4
  Top Layer w0.203: v2(53.34,314.522) 52.07,315.792 52.07,329.95 52.714,330.593 54.133,330.593 54.911,331.371 55.804,331.371 56.002,331.57 C171.1@56.002,332.385 v2(56.901,332.385) ; v2(99.337,257.424) 102.134,257.424 106.223,261.512 113.008,268.297 117.429,268.297 154.727,231 168.36,231 168.749,231.388 v2(169.319,231.388) ; v2(224.057,240) 224.09,240.033 224.09,269.156 R301.2@224.09,272.9
  Signal Layer 2 w0.203: v2(53.34,314.522) 55.016,312.847 63.832,312.847 66.236,310.442 66.236,308.367 70.104,304.499 70.104,259.842 v2(72.964,256.982) v2@73.076,256.982 ; v2(169.319,231.388) 169.673,231.388 170.763,232.478 170.763,233.6 174.194,237.031 182.662,237.031 183.016,236.677 185.019,236.677 185.798,237.456 221.513,237.456 v2(224.057,240)
  Bottom Layer w0.203: v2(56.901,332.385) J26.109@58.402,332.385 ; v2(72.964,256.982) 79.979,263.998 83.602,263.998 83.607,263.993 84.112,263.993 84.116,263.998 96.81,263.998 99.337,261.471 v2(99.337,257.424)
Temp_SENSE_L2: C317.1 J26.107 R315.2 | length 465.8
  Top Layer w0.203: v2(53.362,313.375) 51.308,315.429 51.308,330.736 52.042,331.47 54.114,331.47 54.457,331.813 C317.1@54.457,332.367 v2(55.211,332.367) ; v2(73.914,222.504) 73.914,219.255 74.452,218.717 74.452,161.638 80.7,155.39 80.7,102.3 v2(80.4,102) ; v2(100,96) 100.446,96 100.449,95.997 128.497,95.997 153,120.5 v2(153,122.518) ; R315.2@224.09,181.881 224.09,178.11 224.1,178.1 v2(224.1,148.8)
  Signal Layer 2 w0.203: v2(53.362,313.375) 53.365,313.375 54.392,312.347 63.319,312.347 65.381,310.285 65.381,308.164 69.5,304.045 69.5,259.145 74.8,253.845 74.8,250.848 73.914,249.962 v2(73.914,222.504) ; v2(89.6,93) 92.042,93 95.042,96 v2(100,96) ; v2(153,122.518) 153,127.794 172.816,147.61 188.741,147.61 189.951,146.4 206.9,146.4 209.3,148.8 v2(224.1,148.8)
  Bottom Layer w0.203: v2(55.211,332.367) 55.993,331.585 J26.107@58.402,331.585 ; v2(80.4,102) 80.4,99.5 86.9,93 v2(89.6,93)
Temp_SENSE_L3: C158.1 J26.103 R182.2 | length 460.8
  Top Layer w0.203: v2(53.34,332.197) C158.1@53.34,333.016 52.158,333.016 50.627,331.485 50.627,315.25 52.753,313.125 52.753,313.122 53.11,312.765 53.113,312.765 v2(54.102,311.776) ; v2(73.152,223.52) 73.152,218.898 73.8,218.25 73.8,161.1 80.015,154.885 v2(80.015,104.292) ; v2(89.569,91.218) 89.569,78.793 89.6,78.762 89.569,78.731 113.3,55 128.399,55 130.815,57.416 137.012,57.416 139.329,55.1 v2(169.4,55.1) ; v2(205.7,58.2) 213.214,58.2 224.1,69.086 R182.2@224.1,91.001
  Signal Layer 2 w0.203: v2(54.102,311.776) 62.922,311.776 64.504,310.194 64.504,308.102 68.8,303.806 68.8,258.489 74.026,253.263 74.026,251.134 73.152,250.26 v2(73.152,223.52) ; v2(169.4,55.1) 169.8,55.1 172.9,58.2 v2(205.7,58.2)
  Bottom Layer w0.203: v2(53.34,332.197) 54.744,330.793 56.306,330.793 57.113,329.985 J26.103@58.402,329.985 ; v2(80.015,104.292) 79.35,103.627 79.35,99.261 87.393,91.218 v2(89.569,91.218)
TMCS_VO_L1: R311.2 U41.6 | length 96
  Top Layer w0.203: R311.2@72.761,332.6 v2(72.761,333.399) ; v2(87.702,258.463) 87.834,258.463 89.829,256.469 93.726,256.469 U41.6@98.806,251.389
  Signal Layer 2 w0.203: v2(72.761,333.399) 72.761,332.523 75.185,330.099 75.185,312.164 87.702,299.647 87.702,259.8 v2(87.702,258.463)
TMCS_VO_L2: R346.2 U47.6 | length 174.1
  Top Layer w0.203: v2(73.674,319.905) R346.2@73.674,320.753 ; v2(83.027,240.018) 85.312,237.733 85.312,231.902 85.312,167.703 87.516,165.5 93.3,165.5 94.439,166.639 95.467,166.639 U47.6@96.539,167.712
  Signal Layer 2 w0.203: v2(73.674,319.905) 73.702,319.877 73.702,312.286 86.829,299.159 86.829,257.596 83.82,254.587 83.82,240.811 v2(83.027,240.018)
TMCS_VO_L3: R179.2 U21.6 | length 217.6
  Top Layer w0.203: v2(78.914,237.363) 78.914,234.487 83.37,230.032 83.37,229.616 83.37,166.53 89.865,160.035 89.865,139.9 95.408,134.357 97.655,134.357 98.87,135.572 99.828,135.572 U21.6@100.726,136.47 ; v2(78.914,246.464) 79.291,246.464 v2(84.836,252.01) ; v2(79.187,319.898) R179.2@79.187,320.753
  Signal Layer 2 w0.203: v2(78.914,237.363) v2(78.914,246.464) ; v2(79.187,319.898) 85.473,313.612 85.473,311.552 92.201,304.825 94.214,304.825 99.286,299.753 99.286,266.421 84.874,252.01 v2(84.836,252.01)
TMCS_VREF1: R309.2 U41.5 | length 95.1
  Top Layer w0.203: R309.2@73.674,332.6 v2(73.674,333.395) ; v2(88.501,259.334) 90.787,257.048 94.943,257.048 U41.5@99.704,252.287
  Signal Layer 2 w0.203: v2(73.674,333.395) 73.674,332.753 75.693,330.735 75.693,312.419 88.3,299.812 88.3,259.535 v2(88.501,259.334)
TMCS_VREF2: R348.2 U47.5 | length 172.4
  Top Layer w0.203: v2(72.761,319.899) R348.2@72.761,320.753 ; v2(83.058,241.3) 85.907,238.451 85.907,168.193 88.032,166.068 93.1,166.068 U47.5@95.641,168.61
  Signal Layer 2 w0.203: v2(72.761,319.899) 73.152,319.507 73.152,312.028 86.36,298.82 86.36,261.366 86.36,257.916 83.312,254.868 83.312,241.554 v2(83.058,241.3)
TMCS_VREF3: R181.2 U21.5 | length 215.3
  Top Layer w0.203: v2(79.708,238.252) 79.708,234.576 84,230.284 84,166.776 90.478,160.298 90.478,140.187 95.719,134.946 97.406,134.946 U21.5@99.828,137.368 ; v2(79.708,245.785) v2(86.145,252.222) ; v2(80.111,319.897) R181.2@80.111,320.753
  Signal Layer 2 w0.203: v2(79.708,238.252) v2(79.708,245.785) ; v2(80.111,319.897) 85.88,314.128 85.88,312.037 92.546,305.371 94.637,305.371 99.828,300.18 99.828,265.891 86.159,252.222 v2(86.145,252.222)
TMP1: C344.2 R301.1 U42.4 | length 2.5
  Top Layer w0.203: U42.4@221.6,273.9 C344.2@223.117,273.9 R301.1@224.09,273.9
TMP2: C345.2 R315.1 U48.4 | length 2.5
  Top Layer w0.203: U48.4@221.6,182.899 223.099,182.899 C345.2@223.117,182.881 R315.1@224.09,182.881
TMP3: C340.2 R182.1 U22.4 | length 2.5
  Top Layer w0.203: U22.4@221.6,91.978 223.094,91.978 C340.2@223.117,92.001 R182.1@224.1,92.001
V_PCC_IN1: C297.1 RN4.6 U44.2 | length 57.3
  Top Layer w0.203: RN4.6@17.032,61.836 17.032,63.1 22.532,68.6 33.301,68.6 51.6,86.899 51.6,94.243 52.828,95.471 C297.1@53.285,95.471 53.92,95.471 54.009,95.56 U44.2@55.287,95.56
V_PCC_IN2: C324.1 RN5.6 U49.2 | length 32.3
  Top Layer w0.203: RN5.6@42.897,61.836 42.897,72.833 55.564,85.5 C324.1@56.637,85.5 56.649,85.512 57.503,85.512 57.617,85.626 U49.2@58.713,85.626 U49.2@58.587,85.5
V_PCC_IN3: C357.1 RN6.6 U59.2 | length 20
  Top Layer w0.203: U59.2@62.597,75.786 61.535,75.786 61.421,75.672 C357.1@60.532,75.672 59.832,75.672 59.225,75.065 59.225,72.025 RN6.6@68.589,62.661
V_PCC_L1: F1.1 K1.3 R90.2 R96.2 RN4.4 TP22.1 | length 2.9
  Top Layer w3: K1.3@9.7,50.037 R90.2@9.7,52.95
  other v2: 16.465,42.353 17.698,42.353 18.93,42.353 20.162,42.353 21.394,42.353 15.772,43.354 15.772,44.282 16.229,45.401 17.262,45.401 18.295,45.401 19.328,45.401 20.361,45.401 21.394,45.401 9.5,48 10.5,48 11.5,48 12,49 12,50 12,51 20.2,51.854 21.2,51.854 20.2,52.782 21.2,52.782
V_PCC_L2: F2.1 K2.3 R92.2 R97.2 RN5.4 TP24.1 | length 2.9
  Top Layer w3: K2.3@34.699,50.037 34.699,52.9 R92.2@34.749,52.95
  other v2: 42.1,42.353 43.391,42.353 44.682,42.353 45.974,42.353 47.265,42.353 41.575,43.254 41.575,44.182 42.032,45.301 43.065,45.301 44.098,45.301 45.131,45.301 46.164,45.301 47.197,45.301 33.5,47.987 34.5,47.987 35.5,47.987 36.5,47.987 37,48.987 37,49.987 37,50.987 46.003,51.754 47.003,51.754 46.003,52.682 47.003,52.682
V_PCC_L3: F3.1 K3.3 R95.2 R98.2 RN6.4 TP28.1 | length 2.9
  Top Layer w3: K3.3@60.585,50.037 60.585,52.9 R95.2@60.635,52.95
  other v2: 67.649,42.353 68.94,42.353 70.231,42.353 71.522,42.353 72.814,42.353 67.124,43.254 67.124,44.182 67.581,45.301 68.614,45.301 69.647,45.301 70.68,45.301 71.713,45.301 72.746,45.301 59.335,48.052 60.335,48.052 61.335,48.052 62.335,48.052 62.692,49.052 62.692,50.052 62.692,51.052 71.552,51.754 72.552,51.754 71.552,52.682 72.552,52.682
V_PCC_N: C198.2 C210.1 C268.2 C281.1 C295.2 C297.2 C305.2 C308.1 C324.2 C357.2 C447.2 R96.1 R97.1 R98.1 R100.2 RN4.5 RN5.5 RN6.5 TP40.1 U35.12 U35.13 U35.14 U35.15 U35.16 U44.3 U44.4 U49.3 U49.4 U59.3 U59.4 | length 40.2
  Top Layer w0.203: C297.2@53.285,94.471 53.9,94.471 54.08,94.29 U44.3@55.287,94.29 ; C324.2@56.637,84.5 57.4,84.5 57.544,84.356 U49.3@58.713,84.356 ; C357.2@60.532,74.672 61.421,74.672 61.577,74.516 U59.3@62.597,74.516
  Top Layer w0.305: C447.2@54.2,105 54.5,105 54.725,105.225 U35.12@55.71,105.225
  Top Layer w0.5: RN4.5@18.302,61.836 20.302,61.836 R96.1@20.659,61.479 ; RN5.5@44.167,61.836 46.167,61.836 R97.1@46.523,61.479 ; v1(51,98.3) C305.2@52.084,98.3 52.684,97.7 C308.1@52.684,96.83 v1(51.857,96.83) ; C295.2@52.524,104.484 53.684,104.484 C447.2@54.2,105 ; v1(53.5,92.154) 55.001,92.154 55.287,92.44 U44.4@55.287,93.02 ; v1(53.504,93.02) U44.4@55.287,93.02 ; v1(54.4,88.349) C198.2@55.452,88.35 ; v1(55.257,86.88) 55.277,86.9 C210.1@56.051,86.9 ; U44.3@55.287,94.29 U44.4@55.287,93.02 ; v1(56.9,82.203) 58.403,82.203 58.713,82.513 U49.4@58.713,83.086 ; v1(56.904,83.07) 56.92,83.086 U49.4@58.713,83.086 ; v1(58.3,78.51) C268.2@59.335,78.51 ; U49.3@58.713,84.356 U49.4@58.713,83.086 ; v1(59.157,77.04) 59.176,77.06 C281.1@59.935,77.06 ; v1(60.8,72.364) 62.464,72.364 62.597,72.497 U59.4@62.597,73.246 60.82,73.246 v1(60.804,73.23) ; RN6.5@69.859,61.836 71.859,61.836 R98.1@72.215,61.479
  other v1: 20.27,60.204 21.136,60.2 46.17,60.204 47.036,60.2 19.396,61.035 21.896,61.035 45.296,61.035 47.796,61.035 19.4,61.901 21.9,61.901 45.3,61.901 47.8,61.901 20.27,62.804 21.136,62.8 46.17,62.804 47.036,62.8 15.251,63.704 15.27,64.704 50.834,102.4 51.734,102.4 52.634,102.4 53.533,102.4 50.834,103.285 51.734,103.285 52.634,103.285 53.533,103.285 50.834,104.115 50.834,105
  other v2: 80.024,60.147 71.87,60.204 72.736,60.2 80.936,60.2 79.197,60.858 70.996,61.035 73.496,61.035 79.045,61.824 71,61.901 73.5,61.901 79.756,62.662 71.87,62.804 72.736,62.8
  other v3: 66.548,67.416 59.548,69.416 55.548,73.416 57.548,73.416 54.548,75.416 56.548,75.416 51.548,77.416 53.548,77.416 55.548,77.416 52.548,79.416 54.548,79.416 49.548,81.416 53.548,81.416 50.548,83.416 53.548,85.416
V_SENSE_DC: R24.2 S4.2 | length 4.5
  Top Layer w0.203: S4.2@80.152,316.399 81.632,316.399 82.757,315.275 R24.2@84.226,315.275
V_SENSE_MID_DC-: R33.2 S3.2 | length 8.2
  Top Layer w0.203: S3.2@80.201,310.15 82.152,310.15 83.113,309.189 R33.2@88.002,309.189
V_SENSE_MID_DC-_0039C: C492.1 J26.82 S3.3 | length 27.5
  Top Layer w0.203: v2(63.302,320.6) 63.702,320.2 C492.1@64.302,320.2 v2(71.703,320.2) ; v2(75.51,308.367) 75.544,308.4 S3.3@77.901,308.4
  Signal Layer 2 w0.203: v2(71.703,320.2) 71.703,319.472 72.136,319.039 72.136,311.741 v2(75.51,308.367)
  Bottom Layer w0.203: J26.82@60.402,321.185 62.717,321.185 v2(63.302,320.6)
V_SENSE_PCC_L1: C240.1 J26.106 R171.2 | length 261.8
  Top Layer w0.203: v2(62.38,330.785) 62.687,331.092 C240.1@63.202,331.092 v2(64.042,331.092) ; R171.2@68.89,95.56 80.791,95.56 81.3,96.07 81.3,155.676 75,161.976 75,217.824 v2(75,220.726)
  Signal Layer 2 w0.203: v2(64.042,331.092) 64.042,330.206 66.974,327.274 66.974,324.032 68.809,322.197 68.809,309.269 72.964,305.115 72.964,260.114 77.216,255.862 77.216,250.023 75.909,248.716 75.909,225.534 77,224.443 77,221.94 75.786,220.726 v2(75,220.726)
  Bottom Layer w0.203: J26.106@60.402,330.785 v2(62.38,330.785)
V_SENSE_PCC_L2: C301.1 J26.90 R222.2 | length 260
  Top Layer w0.203: v2(62.175,324.385) 63.218,324.385 C301.1@63.227,324.376 63.227,325.264 v2(63.181,325.311) ; R222.2@72.401,85.626 76.036,85.626 81.9,91.49 81.9,145.424 81.9,156.11 75.752,162.257 75.752,217 75.752,222.098 75.26,222.591 v2(75.26,225.289)
  Signal Layer 2 w0.203: v2(63.181,325.311) 65.692,325.311 66.102,324.9 66.102,323.868 68.072,321.898 68.072,308.939 72.39,304.621 72.39,259.602 76.708,255.284 76.708,250.492 75.26,249.044 v2(75.26,225.289)
  Bottom Layer w0.203: J26.90@60.402,324.385 v2(62.175,324.385)
V_SENSE_PCC_L3: C326.1 J26.93 R251.2 | length 280
  Top Layer w0.203: v2(53.504,323.325) 53.504,323.887 53.802,324.186 C326.1@53.802,326.025 v2(54.602,326.025) ; v2(76.2,223.669) 76.2,223.078 76.402,222.876 76.402,217 76.402,162.857 82.497,156.763 82.497,143.173 82.497,80.631 77.652,75.786 R251.2@76.26,75.786
  Signal Layer 2 w0.203: v2(53.504,323.325) 54.564,324.385 60.421,324.385 61.21,323.596 65.118,323.596 67.31,321.404 67.31,308.559 70.866,305.003 70.866,260.203 75.909,255.16 75.909,250.833 74.586,249.51 74.586,224.233 75.15,223.669 v2(76.2,223.669)
  Bottom Layer w0.203: v2(54.602,326.025) 58.272,326.025 58.357,325.94 J26.93@58.402,325.985
V_SENSE_SN_L1: C61.1 J26.100 R63.2 | length 124.7
  Top Layer w0.203: v2(61.816,328.368) v2(63.347,328.368) ; v2(88.3,232.41) 88.3,224.341 88.972,223.669 R63.2@90.1,223.669
  Signal Layer 2 w0.203: v2@70.996,325.181 70.996,311.206 85.852,296.35 85.852,258.572 82.412,255.132 82.412,238.298 v2(88.3,232.41)
  Bottom Layer w0.203: J26.100@60.402,328.385 60.419,328.368 v2(61.816,328.368) ; v2(63.347,328.368) 63.388,328.41 67.767,328.41 v2(70.866,325.311)
V_SENSE_SN_L2: C348.1 J26.88 R68.2 | length 128.7
  Top Layer w0.203: v2(63.952,322.842) C348.1@65.278,322.842 69.164,322.842 69.383,323.06 v2(70.358,323.06) ; v2(86.968,232.41) 87.626,231.752 87.626,220.462 89.444,218.644 89.444,216.246 89.586,216.104 R68.2@90.1,216.104
  Signal Layer 2 w0.203: v2(70.358,323.06) 70.358,310.388 85.27,295.476 85.27,259.033 81.788,255.551 81.788,238.022 86.968,232.842 v2(86.968,232.41)
  Bottom Layer w0.203: J26.88@60.402,323.585 62.738,323.585 63.482,322.842 v2(63.952,322.842)
V_SENSE_SN_L3: C358.1 J26.91 R73.2 | length 232.3
  Top Layer w0.203: C358.1@56.469,325.185 C358.1@56.469,325.188 ; v2(57.302,325.188) C358.1@56.469,325.188 ; v2(68.457,324.051) 67.599,324.051 66.397,325.253 64.319,325.253 63.632,325.94 56.814,325.94 56.469,325.595 C358.1@56.469,325.188 ; v2(78.512,232.211) 82.112,228.611 82.112,228.375 82.112,165.81 88.423,159.499 88.423,138.828 90.9,136.351 90.9,125.185 92.403,123.682 R73.2@93.88,123.682
  Signal Layer 2 w0.203: v2(68.457,324.051) 69.613,322.894 69.613,309.754 84.566,294.801 84.566,259.71 79.708,254.852 79.708,249.428 78.162,247.882 78.162,232.561 v2(78.512,232.211)
  Bottom Layer w0.203: v2(57.302,325.188) 58.399,325.188 J26.91@58.402,325.185
V_SN_IN1: C60.1 RN1.6 U18.2 | length 26.9
  Top Layer w0.203: U18.2@104.65,223.669 104.657,223.662 C60.1@106.297,223.662 v1(106.973,223.662)
  Top Layer w0.229: v1(127,217.653) 127.67,218.323 RN1.6@127.67,219.478
  Signal Layer 1 w0.229: v1(106.973,223.662) 110.863,223.662 116.872,217.653 v1(127,217.653)
V_SN_IN2: C197.1 RN2.6 U37.2 | length 29.5
  Top Layer w0.203: U37.2@104.65,216.104 C197.1@106.297,216.104 v1(107.023,216.104) ; RN2.6@114.724,195.605 115.923,196.803 v1(115.923,200.3)
  Signal Layer 1 w0.229: v1(107.023,216.104) 111.248,216.104 115.923,211.43 v1(115.923,200.3)
V_SN_IN3: C231.1 RN3.6 U40.2 | length 21.8
  Top Layer w0.203: U40.2@108.593,123.682 C231.1@110.431,123.682 114.718,123.682 117.035,126 125.413,126 127.37,127.957 RN3.6@127.37,129.2
V_SN_N: C56.2 C57.1 C60.2 C63.2 C64.1 C67.1 C68.1 C69.1 C70.1 C71.1 C72.1 C73.1 C74.2 C75.1 C76.1 C197.2 C231.2 C353.2 C354.1 C361.2 C362.2 RN1.5 RN2.5 RN3.5 TP38.1 U18.3 U18.4 U37.3 U37.4 U40.3 U40.4 U60.12 U60.13 U60.14 U60.15 U60.16 | length 43.9
  Top Layer w0.203: U60.12@108,115.5 109.285,115.5 C362.2@109.51,115.725
  Top Layer w0.5: RN2.5@115.622,194.707 120.906,199.991 C69.1@124.037,199.991 ; C70.1@123.993,129.167 124.027,129.2 RN3.5@126.1,129.2 ; C68.1@124.41,219.478 RN1.5@126.4,219.478
  Bottom Layer w1.5: C74.2@134.602,125.9 147.621,112.881 v1(156.616,112.881)
  Bottom Layer w2: C74.2@134.602,125.9 C74.2@134.602,126.072
  other v1: 156.616,110.755 158.501,110.907 157.534,111.328 159.601,111.328 156.616,111.887 158.501,111.97 157.534,112.46 159.5,112.605 158.501,113.102 157.534,113.454 159.5,113.668 156.616,113.944 158.501,114.096 157.534,114.517 159.5,114.8 158.501,115.159 159.5,115.794 159.5,116.857 109.346,116.9 110.177,117.4 109.33,117.9 110.177,118.325 109.346,118.8 107.711,118.9 110.162,119.3 108.5,119.4 107.7,119.9 109.346,119.892 110,125.428 110,126.268 127.24,126.354 108.642,126.994 127.836,127.1 124.94,128.309 124.995,130.109 123.171,199.051 124.9,199.051 123.1,200.951 157.48,202.979 156,203 158.979,202.995 157.48,203.979 156,204 158.979,203.995 156,205 157.5,205 158.979,205.015 156,206 157.5,206 158.979,206.015 156,207 157.5,207.015 158.979,207.031 156,207.964 157.5,207.98 158.979,207.995 156,209 157.5,209 158.979,209.015 156,210 157.5,210 158.979,210.015 156,211 157.5,211 158.979,211.015 156,212 157.5,212 158.979,212.015 104.293,213.834 105.292,213.834 127.694,216.871 128.479,217.653 106.3,218.103 125.33,218.6 104.22,219.414 105.141,219.414 125.33,220.354 106.031,225.603 104.3,227.003 105.141,227.003
  other v2: 134.152,124.902 133.4,125.664 135.64,126.533 133.5,126.59 134.2,127.215 135.066,127.407
VCC_BOT_L1: C195.1 R201.1 U25.15 | length 2.8
  Top Layer w0.5: R201.1@207.72,324.532 208.53,323.722 C195.1@208.53,323.511 U25.15@208.53,322.108
VCC_BOT_L2: C208.1 R216.1 U26.15 | length 2.8
  Top Layer w0.4: C208.1@208.532,232.543 C208.1@208.532,232.754
  Top Layer w0.5: R216.1@207.722,233.564 C208.1@208.532,232.754 ; U26.15@208.532,231.14 C208.1@208.532,232.543
VCC_BOT_L3: C226.1 R231.1 U27.15 | length 2.8
  Top Layer w0.5: R231.1@207.722,142.569 208.53,141.761 C226.1@208.53,141.519 208.532,141.517 U27.15@208.532,140.144
VCC_BUF_L1: C383.2 R388.1 U51.14 | length 2.2
  Top Layer w0.229: R388.1@102.746,306.331 C383.2@103.746,306.331 U51.14@104.943,306.331
VCC_BUF_L2: C384.2 R380.1 U52.14 | length 2.2
  Top Layer w0.229: R380.1@91.606,293.913 C384.2@92.606,293.913 U52.14@93.802,293.913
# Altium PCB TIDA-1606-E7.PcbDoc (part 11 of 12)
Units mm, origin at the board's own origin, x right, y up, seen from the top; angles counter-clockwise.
Board outline 270 x 345 mm, 4 copper layers (Top Layer, Signal Layer 1, Signal Layer 2, Bottom Layer), stack 1.69 mm thick; 1263 components, 574 nets, 3595 pads, 4069 vias.
Unrouted connection lines stored in the file: 1719.

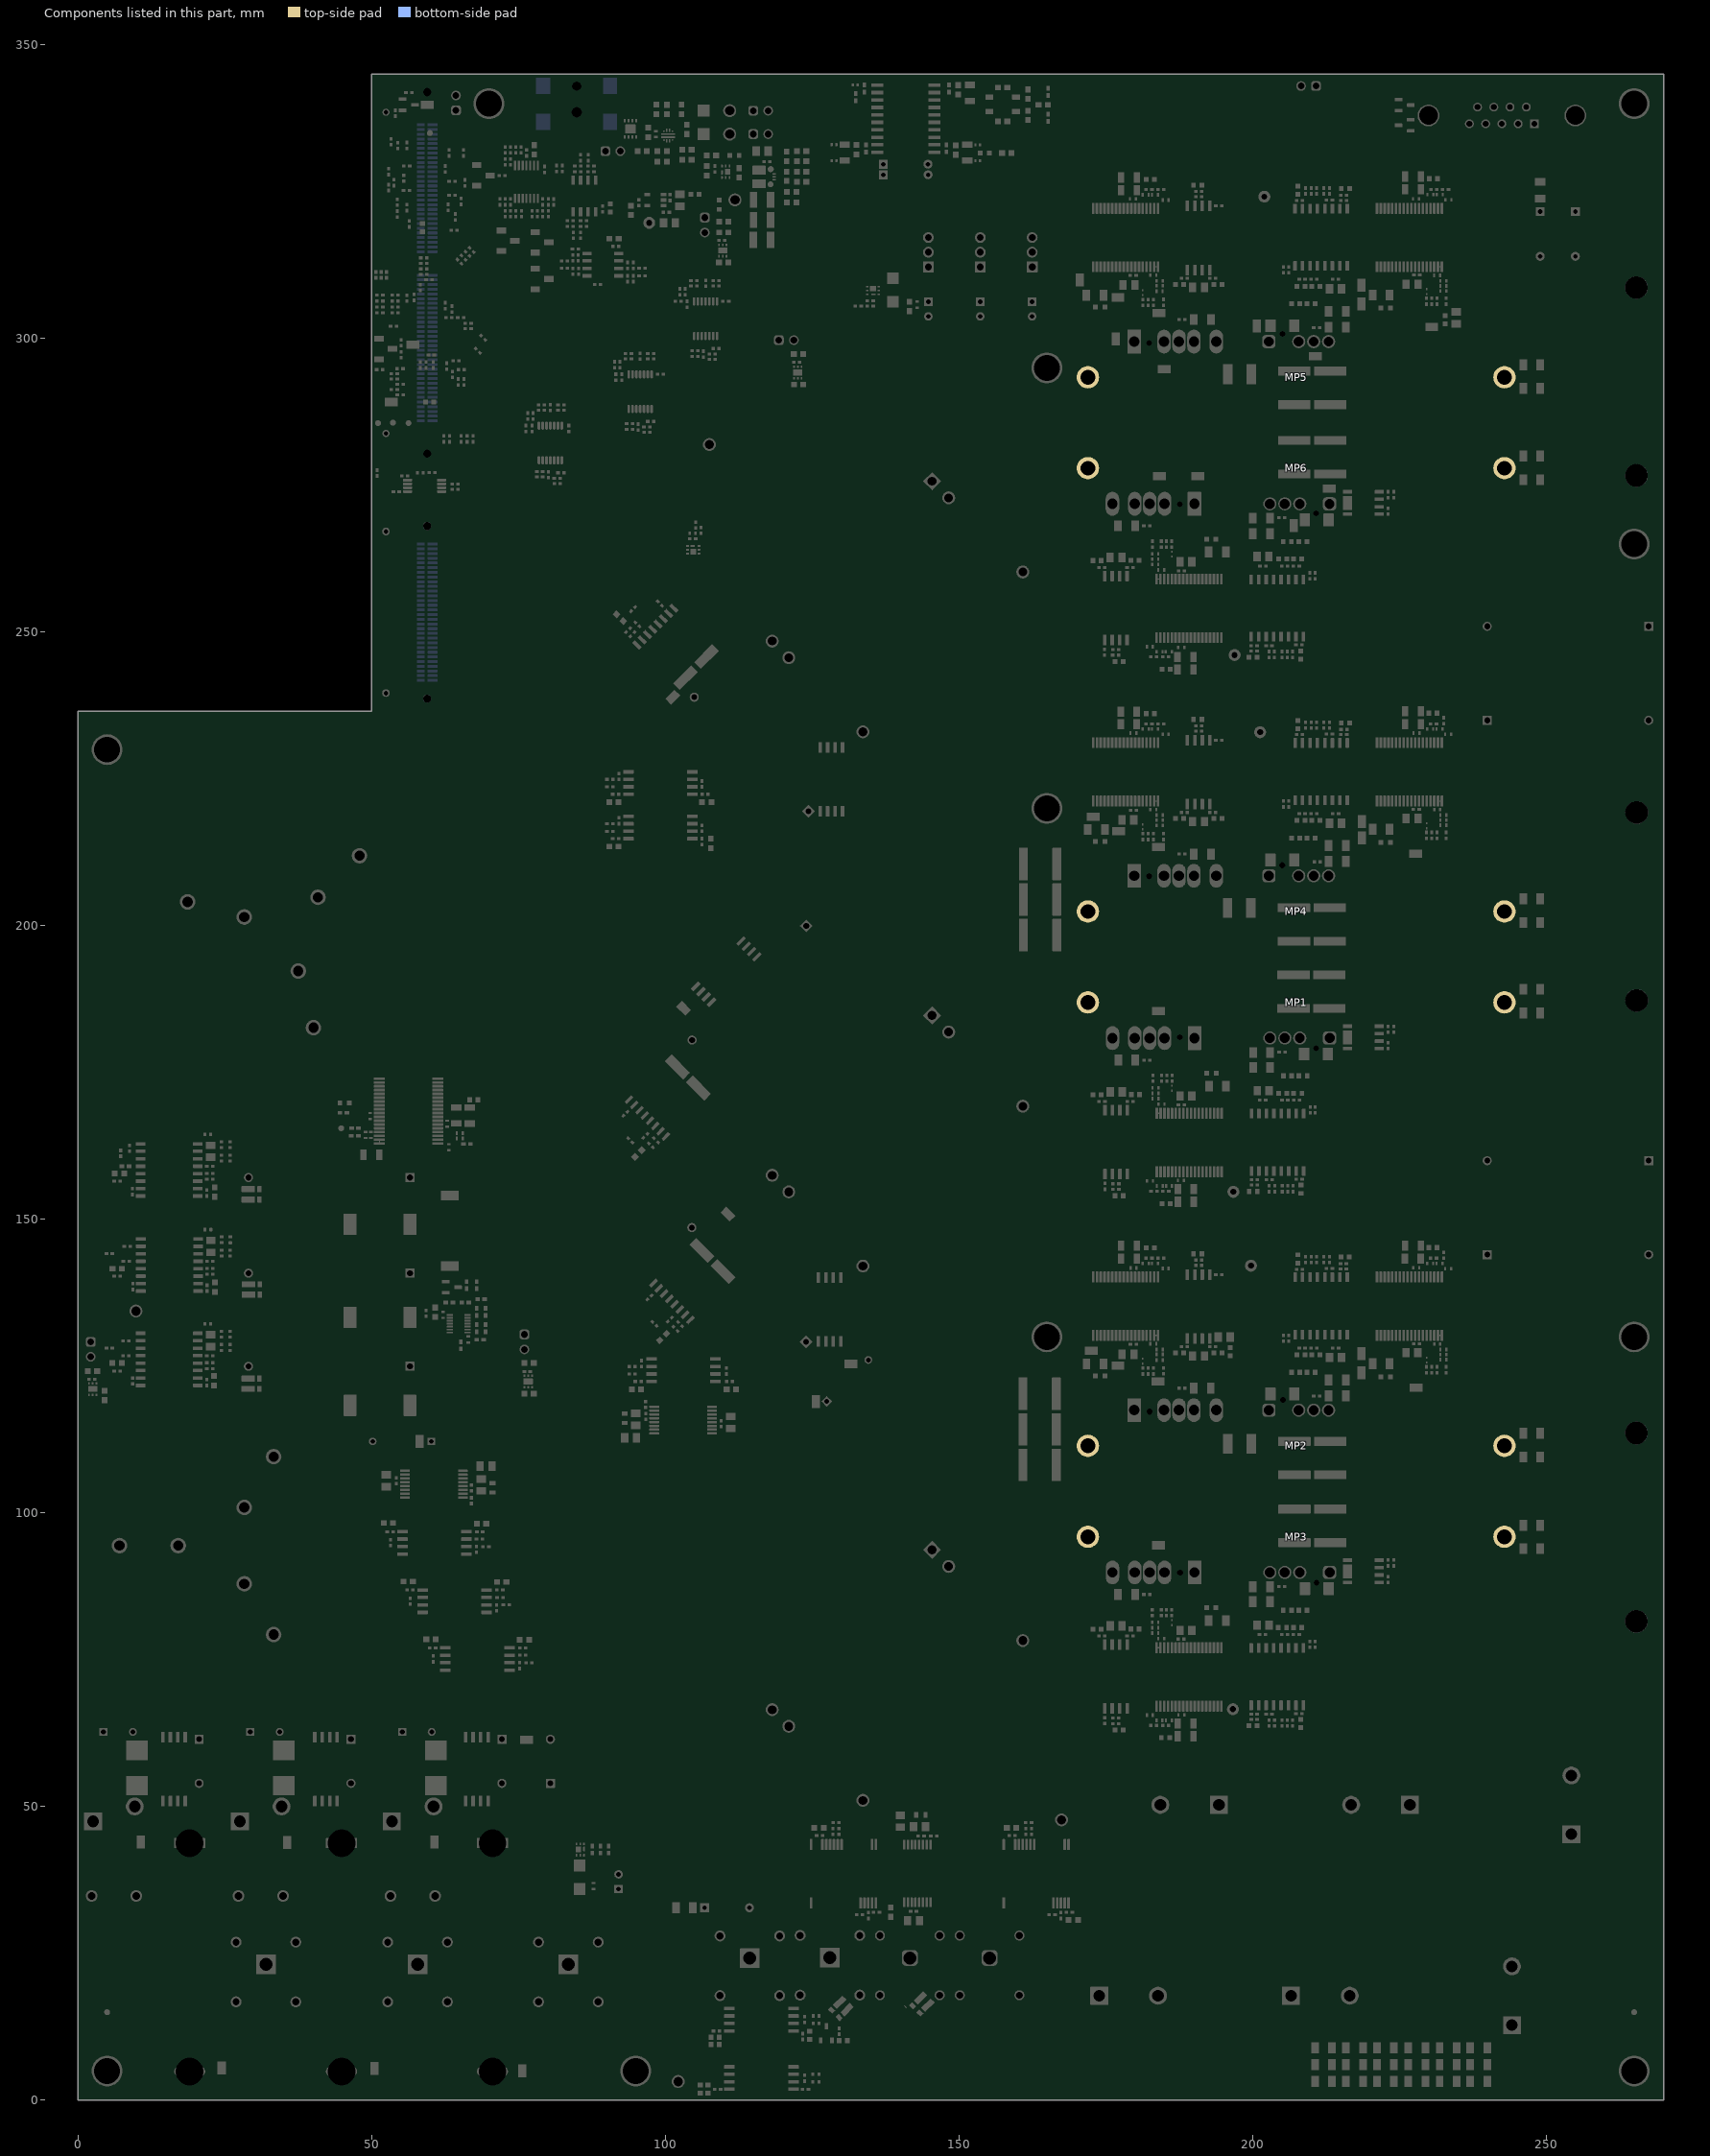
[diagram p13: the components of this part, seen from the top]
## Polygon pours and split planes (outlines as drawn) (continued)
DESAT_BOT_L3 on Top Layer "Bottom Layer-DESAT_BOT_L2" (solid, remove dead copper, pour order 1514): 140.892,94.242 145.892,99.242 153.883,91.251 148.882,86.251
DESAT_BOT_L2 on Top Layer "Bottom Layer-DESAT_BOT_L2" (solid, remove dead copper, pour order 1510): 141.092,185.608 146.092,190.608 154.083,182.618 149.082,177.617
DESAT_BOT_L1 on Top Layer "TOP_LAYER_DESAT_BOT_L1_P1507" (solid, remove dead copper, pour order 1507): 141.451,276.63 146.71,281.89 154.701,273.899 149.441,268.639
+5VISO_PCC on Top Layer "TOP_LAYER_+5VISO_PCC_P1503" (solid, remove dead copper, pour order 1503): 52.938,107.175 53.34,107.577 53.34,108.041 56.5,108.041 56.5,105.6 50.5,105.6 50.5,108.523 51.734,108.523 51.734,107.493 52.052,107.175 52.537,107.175
V_PCC_N on Top Layer "TOP_LAYER_V_PCC_N_P1502" (solid, remove dead copper, pour order 1502): 50.4,101.89 50.4,105.4 56.5,105.4 56.5,101.89
I_SN_L2- on Top Layer "Top Layer-I_SN_L2-" (solid, remove dead copper, pour order 1318): 102.488,188.142 95.576,181.23 103.074,173.828 103.112,173.828 107.392,178.107 107.392,183.238
CHK_1 on Top Layer "Top Layer-CHK_1" (solid, pour order 1491): 34.866,152.07 34.866,148.166 28.787,148.166 27.806,149.147 27.806,153.87 30.166,153.87 30.166,152.77 30.865,152.07
CHK_2 on Top Layer "Top Layer-CHK_2" (solid, pour order 1488): 31.3,113.3 30.133,112.133 30.133,100.433 28.992,99.292 23.398,99.292 20.854,101.836 20.854,117.793 24.84,121.78 31.3,121.78
V_PCC_L1 on Top Layer "TOP_LAYER_V_PCC_L1_P1476" (solid, pour order 1476): 8,52.5 19.346,52.5 19.346,55 22.012,55 22.012,42 8,42
RLAY_1 on Top Layer "TOP_LAYER_RLAY_1_P1473" (solid, remove dead copper, pour order 1473): 9.295,97 2,97 0,95 0,44.501 5.5,44.498 5.5,65.082 11.5,71.082 11.5,94.795
REF_MID3 on Top Layer "Top Layer-REF_MID1" (solid, remove dead copper, pour order 1465): 120.904,16.657 120.904,9.657 132.105,9.657 132.105,10.612 126.061,16.657
VDC- on Top Layer "Top Layer-VDC- 3" (solid, remove dead copper, pour order 1295): 156.9,16.7 156.9,10.1 149.13,10.1 143.53,15.7 144.531,16.7
VDC_MID_IN on Top Layer "Top Layer-VDC_MID_IN" (solid, remove dead copper, pour order 1293): 123.14,27.2 132.807,27.2 132.807,19.109 128.477,14.779 123.14,20.116
VDC+ on Top Layer "Top Layer-VDC+" (solid, remove dead copper, pour order 1462): 209.246,94.1 212.033,91.313 212.033,89.882 212.291,89.882 212.291,86.2 217,86.2 217,95.722 204.231,95.722 204.231,94.1
VDC+ on Top Layer "Top Layer-VDC+" (solid, remove dead copper, pour order 1461): 209.246,276.1 211.9,273.446 211.9,270.7 212.291,270.7 212.291,268.085 216.996,268.085 216.996,277.722 204.231,277.722 204.231,276.1
LO_MAG_VIN_L3 on Top Layer "TOP_LAYER_LO_MAG_VIN_L3_P1398" (solid, remove dead copper, pour order 1398): 228.1,139.269 228.054,146.169 229.158,146.169 229.158,139.269
+15V_MID3 on Top Layer "TOP_LAYER_+15V_MID3_P1440" (solid, remove dead copper, pour order 1440): 17 vertices, not listed, extent 175.639,122.489 180.98,131.13
-4V_MID3 on Top Layer "Top Layer--4V_SN_L1 1" (solid, remove dead copper, pour order 1445): 194.16,124.845 192.229,124.845 191.207,125.868 191.207,127.557 192.485,127.557 192.485,128.306 192.882,128.306 193.52,127.668 193.785,127.668 193.785,126.374 194.16,125.999
+15V_MID3 on Top Layer "Top Layer-+15V_SN_L1 1" (solid, remove dead copper, pour order 1442): 190.5,123.105 184.52,123.105 184.52,124.168 187.9,124.176 187.9,127.668 188.186,127.668 188.823,128.305 189.221,128.305 189.221,127.557 190.5,127.557
REF_MID3 on Top Layer "Top Layer-REF_SN_L1 1" (solid, remove dead copper, pour order 1441): 181.029,123.376 183.632,120.773 187.877,120.773 187.877,123.205 183.508,123.205 183.508,124.075 181.029,124.075
-4V_MID3 on Top Layer "Top Layer--4V_SN_L1" (solid, remove dead copper, pour order 1439): 169.88,131.126 169.88,125.309 175.226,125.309 175.226,126.338 178.399,129.511 178.399,131.126
-4V_SN_L2 on Top Layer "Top Layer--4V_SN_L1" (solid, remove dead copper, pour order 1413): 200.147,167.217 200.147,169.541 201.139,170.533 201.139,172.932 191.939,172.932 191.939,171.431 189.34,168.832 189.34,167.217
+15V_SN_L2 on Top Layer "Top Layer-+15V_SN_L1" (solid, remove dead copper, pour order 1412): 202.255,170.288 202.224,174.874 205.139,174.874 205.139,170.288
-4V_SN_L2 on Top Layer "Top Layer-REF_SN_L1" (solid, remove dead copper, pour order 1410): 209.833,173.064 209.855,169.793 207.921,169.793 207.921,173.064
+15V_SN_L2 on Top Layer "Top Layer-+15V_SN_L1 2" (solid, remove dead copper, pour order 1411): 21 vertices, not listed, extent 186.839,167.232 202.559,176.199
+15V_SN_L2 on Top Layer "Top Layer-+15V_SN_L1 1" (solid, remove dead copper, pour order 1415): 177.261,170.942 178.439,170.942 178.439,170.063 178.851,170.063 179.619,170.832 179.739,170.832 179.739,172.487 181.684,174.432 183.275,174.432 183.275,175.682 180.114,175.682 177.261,172.828
-4V_MID1 on Top Layer "Top Layer--4V_SN_L1 1" (solid, remove dead copper, pour order 1407): 194.158,306.809 192.227,306.809 192.219,306.817 191.205,307.831 191.205,309.521 192.483,309.521 192.483,310.156 192.993,310.156 193.518,309.631 193.783,309.631 193.783,308.337 194.158,307.962
+15V_MID1 on Top Layer "Top Layer-+15V_SN_L1 1" (solid, remove dead copper, pour order 1405): 190.498,305.068 184.606,305.068 184.606,306.132 187.898,306.139 187.898,309.631 188.138,309.631 188.775,310.268 189.219,310.268 189.219,309.521 190.498,309.521
+15V_MID1 on Top Layer "TOP_LAYER_+15V_MID1_P1403" (solid, remove dead copper, pour order 1403): 17 vertices, not listed, extent 175.637,304.453 180.978,313.093
REF_SN_L3 on Top Layer "Top Layer-REF_SN_L1" (solid, remove dead copper, pour order 1434): 205.481,78.234 205.452,82.718 207.392,82.718 207.392,78.234
-4V_SN_L3 on Top Layer "Top Layer--4V_SN_L1" (solid, remove dead copper, pour order 1431): 200.108,76.219 200.108,78.543 201.1,79.535 201.1,81.934 191.9,81.934 191.9,80.434 189.3,77.834 189.3,76.219
+15V_SN_L3 on Top Layer "Top Layer-+15V_SN_L1" (solid, remove dead copper, pour order 1430): 202.215,79.29 202.185,83.876 205.1,83.876 205.1,79.29
-4V_SN_L3 on Top Layer "Top Layer-REF_SN_L1" (solid, remove dead copper, pour order 1428): 209.794,82.066 209.815,78.796 207.881,78.796 207.881,82.066
+15V_SN_L3 on Top Layer "Top Layer-+15V_SN_L1 2" (solid, remove dead copper, pour order 1429): 21 vertices, not listed, extent 186.8,76.234 202.52,85.201
+15V_SN_L3 on Top Layer "Top Layer-+15V_SN_L1 1" (solid, remove dead copper, pour order 1433): 177.221,79.945 178.4,79.945 178.4,79.065 178.931,79.065 179.7,79.834 179.7,81.489 181.644,83.434 183.236,83.434 183.236,84.684 180.075,84.684 177.221,81.83
REF_SN_L1 on Top Layer "Top Layer-REF_SN_L1" (solid, remove dead copper, pour order 1347): 205.479,260.198 205.45,264.682 207.39,264.682 207.39,260.198
MID_MAG_VIN_L3 on Top Layer "TOP_LAYER_MID_MAG_VIN_L3_P1444" (solid, remove dead copper, pour order 1444): 179.825,139.269 179.78,146.169 180.883,146.169 180.883,139.269
-4V_MID3 on Top Layer "Top Layer--4V_SN_L1 2" (solid, remove dead copper, pour order 1443): 178.9,124.467 180.93,124.467 180.93,127.93 180.93,131.13 179.825,131.13 179.825,128.433 178.9,127.508
-4V_SN_L3 on Top Layer "Top Layer--4V_SN_L1 2" (solid, remove dead copper, pour order 1436): 188.559,80.834 188.813,81.088 188.814,81.088 188.814,82.436 186.697,82.436 186.697,76.234 187.802,76.234 187.802,78.73 188.304,79.231 188.304,80.834
REF_SN_L3 on Top Layer "Top Layer-REF_SN_L1 1" (solid, remove dead copper, pour order 1435): 184.236,86.536 182.502,86.536 182.502,85.036 184.236,85.036 184.236,83.234 186.5,83.234 186.5,86.536
-4V_SN_L3 on Top Layer "Top Layer--4V_SN_L1 1" (solid, remove dead copper, pour order 1432): 173.446,82.617 175.377,82.617 176.4,81.594 176.4,79.905 175.121,79.905 175.121,79.057 174.701,79.057 173.964,79.794 173.821,79.794 173.821,81.088 173.446,81.463
VDC+ on Top Layer "Top Layer-VDC+" (solid, remove dead copper, pour order 1425): 209.284,185.1 212.07,182.313 212.07,180.882 212.329,180.882 212.329,177.132 217,177.132 217,186.722 204.269,186.722 204.269,185.1
NetC132_1 on Top Layer "TOP_LAYER_NETC132_1_P1423" (solid, remove dead copper, pour order 1423): 186.742,61.136 186.696,68.036 187.8,68.036 187.8,61.136
NetC319_1 on Top Layer "TOP_LAYER_NETC319_1_P1421" (solid, remove dead copper, pour order 1421): 186.781,152.132 186.736,159.032 187.839,159.032 187.839,152.132
-4V_SN_L2 on Top Layer "Top Layer--4V_SN_L1 2" (solid, remove dead copper, pour order 1418): 188.599,171.832 188.853,172.086 188.854,172.086 188.854,173.434 186.737,173.434 186.737,167.232 187.842,167.232 187.842,169.727 188.343,170.229 188.343,171.832
REF_SN_L2 on Top Layer "Top Layer-REF_SN_L1 1" (solid, remove dead copper, pour order 1417): 184.276,177.534 182.542,177.534 182.542,176.034 184.276,176.034 184.276,174.232 186.539,174.232 186.539,177.534
REF_SN_L2 on Top Layer "Top Layer-REF_SN_L1" (solid, remove dead copper, pour order 1416): 205.5,173.716 205.5,169.232 207.432,169.232 207.432,173.716
-4V_SN_L2 on Top Layer "Top Layer--4V_SN_L1 1" (solid, remove dead copper, pour order 1414): 173.486,173.614 175.417,173.614 176.439,172.592 176.439,170.903 175.161,170.903 175.161,170.047 174.749,170.047 174.004,170.792 173.861,170.792 173.861,172.086 173.486,172.461
-4V_MID1 on Top Layer "Top Layer--4V_SN_L1 2" (solid, remove dead copper, pour order 1406): 178.898,306.431 180.928,306.431 180.928,309.894 180.928,313.093 179.823,313.093 179.823,310.397 178.898,309.472
REF_MID1 on Top Layer "Top Layer-REF_SN_L1 1" (solid, remove dead copper, pour order 1404): 181.027,305.339 183.63,302.736 187.875,302.736 187.875,304.939 183.506,304.939 183.506,306.039 181.027,306.039
-4V_MID1 on Top Layer "Top Layer--4V_SN_L1" (solid, remove dead copper, pour order 1402): 169.798,313.089 169.798,307.294 175.135,307.294 175.135,308.213 178.397,311.475 178.397,313.089
MID_MAG_VIN_L1 on Top Layer "TOP_LAYER_MID_MAG_VIN_L1_P1399" (solid, remove dead copper, pour order 1399): 179.823,321.232 179.778,328.132 180.881,328.132 180.881,321.232
+15V_VDC-1 on Top Layer "Top Layer-+15V_SN_L1" (solid, remove dead copper, pour order 1390): 213.898,310.096 213.928,305.51 211.014,305.509 211.014,310.096
REF_VDC-1 on Top Layer "Top Layer-REF_SN_L1" (solid, remove dead copper, pour order 1389): 210.527,311.123 210.557,306.639 208.616,306.639 208.616,311.123
-4V_VDC-1 on Top Layer "Top Layer--4V_SN_L1" (solid, remove dead copper, pour order 1387): 215.754,313.068 215.754,310.745 214.762,309.753 214.762,307.354 223.962,307.354 223.962,308.854 226.562,311.454 226.562,313.068
+15V_VDC-1 on Top Layer "Top Layer-+15V_SN_L1 2" (solid, remove dead copper, pour order 1385): 21 vertices, not listed, extent 213.402,302.844 229.122,313.068
-4V_VDC-1 on Top Layer "Top Layer-REF_SN_L1" (solid, remove dead copper, pour order 1384): 207.884,310.595 207.905,307.324 205.971,307.324 205.971,310.595
-4V_VDC-1 on Top Layer "Top Layer--4V_SN_L1 2" (solid, remove dead copper, pour order 1388): 227.284,308.446 227.03,308.192 227.029,306.843 229.223,306.843 229.223,313.068 228.107,313.068 228.107,310.616 227.54,310.048 227.54,308.446
-4V_VDC-3 on Top Layer "Top Layer-REF_SN_L1" (solid, remove dead copper, pour order 1397): 207.886,128.631 207.907,125.361 205.973,125.361 205.973,128.631
+15V_VDC-3 on Top Layer "Top Layer-+15V_SN_L1 2" (solid, remove dead copper, pour order 1396): 21 vertices, not listed, extent 213.404,120.318 229.124,131.105
REF_VDC-3 on Top Layer "Top Layer-REF_SN_L1 1" (solid, remove dead copper, pour order 1395): 231.994,120.318 231.994,122.462 231.757,122.462 231.757,124.264 226.449,124.264 226.449,120.318
-4V_VDC-3 on Top Layer "Top Layer--4V_SN_L1" (solid, remove dead copper, pour order 1394): 215.756,131.105 215.756,128.781 214.764,127.789 214.764,125.39 223.964,125.39 223.964,126.891 226.564,129.49 226.564,131.105
-4V_VDC-3 on Top Layer "Top Layer--4V_SN_L1 2" (solid, remove dead copper, pour order 1393): 227.286,126.482 227.032,126.228 227.031,124.88 229.225,124.88 229.225,131.105 228.109,131.105 228.109,128.652 227.542,128.085 227.542,126.482
REF_VDC-3 on Top Layer "Top Layer-REF_SN_L1" (solid, remove dead copper, pour order 1392): 210.529,129.159 210.559,124.675 208.618,124.675 208.618,129.159
+15V_VDC-3 on Top Layer "Top Layer-+15V_SN_L1" (solid, remove dead copper, pour order 1391): 213.9,128.132 213.93,123.546 211.016,123.546 211.016,128.132
REF_VDC-1 on Top Layer "Top Layer-REF_SN_L1 1" (solid, remove dead copper, pour order 1386): 233.25,301 233.25,304.425 231.755,304.425 231.755,306.228 229.101,306.228 229.101,301
LO_MAG_VIN_L1 on Top Layer "TOP_LAYER_LO_MAG_VIN_L1_P1380" (solid, remove dead copper, pour order 1380): 228.122,321.269 228.122,328.169 229.206,328.169 229.206,321.269
LO_MAG_VIN_L2 on Top Layer "TOP_LAYER_LO_MAG_VIN_L2_P1374" (solid, remove dead copper, pour order 1374): 228.1,230.264 228.054,237.164 229.158,237.164 229.158,230.264
-4V_SN_L1 on Top Layer "Top Layer-REF_SN_L1" (solid, remove dead copper, pour order 1373): 209.792,264.03 209.813,260.759 207.879,260.759 207.879,264.03
-4V_VDC-2 on Top Layer "Top Layer-REF_SN_L1" (solid, remove dead copper, pour order 1372): 207.886,219.626 207.907,216.356 205.973,216.356 205.973,219.626
+15V_VDC-2 on Top Layer "Top Layer-+15V_SN_L1 2" (solid, remove dead copper, pour order 1369): 21 vertices, not listed, extent 213.404,211.297 229.124,222.1
REF_VDC-2 on Top Layer "Top Layer-REF_SN_L1 1" (solid, remove dead copper, pour order 1371): 231.994,211.288 231.994,213.457 231.757,213.457 231.757,215.259 226.336,215.259 226.336,211.288
-4V_VDC-2 on Top Layer "Top Layer--4V_SN_L1" (solid, remove dead copper, pour order 1370): 215.756,222.1 215.756,219.776 214.764,218.784 214.764,216.385 223.964,216.385 223.964,217.886 226.564,220.485 226.564,222.1
-4V_VDC-2 on Top Layer "Top Layer--4V_SN_L1 2" (solid, remove dead copper, pour order 1368): 227.286,217.477 227.032,217.223 227.031,215.875 229.225,215.875 229.225,222.1 228.109,222.1 228.109,219.648 227.542,219.08 227.542,217.477
-4V_MID2 on Top Layer "Top Layer--4V_SN_L1" (solid, remove dead copper, pour order 1357): 169.8,222.121 169.8,216.181 175.179,216.181 175.179,216.987 178.399,220.207 178.399,222.121
+15V_MID2 on Top Layer "TOP_LAYER_+15V_MID2_P1366" (solid, remove dead copper, pour order 1366): 17 vertices, not listed, extent 175.639,213.484 180.98,222.125
REF_MID2 on Top Layer "Top Layer-REF_SN_L1 1" (solid, remove dead copper, pour order 1367): 181.029,214.371 183.632,211.768 187.877,211.768 187.877,214.294 183.508,214.294 183.508,215.07 181.029,215.07
+15V_MID2 on Top Layer "Top Layer-+15V_SN_L1 1" (solid, remove dead copper, pour order 1359): 190.5,214.1 184.608,214.1 184.608,215.164 187.9,215.171 187.9,218.663 188.186,218.663 188.823,219.3 189.221,219.3 189.221,218.552 190.5,218.552
-4V_MID2 on Top Layer "Top Layer--4V_SN_L1 2" (solid, remove dead copper, pour order 1354): 178.9,215.462 180.93,215.462 180.93,218.925 180.93,222.125 179.825,222.125 179.825,219.429 178.9,218.503
REF_VDC-2 on Top Layer "Top Layer-REF_SN_L1" (solid, remove dead copper, pour order 1365): 210.529,220.155 210.559,215.671 208.618,215.671 208.618,220.155
+15V_VDC-2 on Top Layer "Top Layer-+15V_SN_L1" (solid, remove dead copper, pour order 1364): 213.9,219.127 213.93,214.541 211.016,214.541 211.016,219.127
MID_MAG_VIN_L2 on Top Layer "TOP_LAYER_MID_MAG_VIN_L2_P1360" (solid, remove dead copper, pour order 1360): 179.825,230.264 179.78,237.164 180.883,237.164 180.883,230.264
-4V_MID2 on Top Layer "Top Layer--4V_SN_L1 1" (solid, remove dead copper, pour order 1358): 194.16,215.84 192.229,215.84 191.207,216.863 191.207,218.552 192.485,218.552 192.485,219.3 192.883,219.3 193.52,218.663 193.785,218.663 193.785,217.369 194.16,216.994
+15V_SN_L1 on Top Layer "Top Layer-+15V_SN_L1 2" (solid, remove dead copper, pour order 1344): 21 vertices, not listed, extent 186.798,258.198 202.518,267.165
NetC276_1 on Top Layer "TOP_LAYER_NETC276_1_P1351" (solid, remove dead copper, pour order 1351): 186.74,243.098 186.694,249.998 187.798,249.998 187.798,243.098
+15V_SN_L1 on Top Layer "Top Layer-+15V_SN_L1" (solid, remove dead copper, pour order 1350): 202.213,261.254 202.183,265.84 205.098,265.84 205.098,261.254
-4V_SN_L1 on Top Layer "Top Layer--4V_SN_L1" (solid, remove dead copper, pour order 1346): 200.106,258.183 200.106,260.507 201.098,261.499 201.098,263.898 191.898,263.898 191.898,262.397 189.298,259.798 189.298,258.183
-4V_SN_L1 on Top Layer "Top Layer--4V_SN_L1 1" (solid, remove dead copper, pour order 1349): 173.444,264.58 175.375,264.58 176.398,263.558 176.398,261.869 175.119,261.869 175.119,261.029 174.548,261.029 173.819,261.758 173.819,263.052 173.444,263.427
+15V_SN_L1 on Top Layer "Top Layer-+15V_SN_L1 1" (solid, remove dead copper, pour order 1348): 177.219,261.908 178.309,261.908 178.309,261.029 178.929,261.029 179.698,261.798 179.698,263.453 181.642,265.398 183.234,265.398 183.234,266.648 180.073,266.648 177.219,263.794
REF_SN_L1 on Top Layer "Top Layer-REF_SN_L1 1" (solid, remove dead copper, pour order 1345): 184.234,268.5 182.5,268.5 182.5,267 184.234,267 184.234,265.198 186.498,265.198 186.498,268.5
-4V_SN_L1 on Top Layer "Top Layer--4V_SN_L1 2" (solid, remove dead copper, pour order 1341): 188.557,262.798 188.811,263.052 188.812,263.052 188.812,264.4 186.695,264.4 186.695,258.198 187.8,258.198 187.8,260.693 188.302,261.195 188.302,262.798
MP6 on Top Layer "Top Layer-MP6" (solid, remove dead copper, pour order 1331): 239.853,280.901 246.923,280.901 246.923,275.002 239.865,275.002
MP5 on Top Layer "Top Layer-MP5" (solid, remove dead copper, pour order 1330): 239.726,296.44 246.796,296.44 246.796,290.542 239.738,290.542
MP3 on Top Layer "Top Layer-MP3" (solid, remove dead copper, pour order 1329): 240.018,98.849 247.088,98.849 247.088,92.951 240.03,92.951
MP2 on Top Layer "Top Layer-MP2" (solid, remove dead copper, pour order 1328): 239.986,114.517 247.056,114.517 247.056,108.618 239.997,108.618
MP1 on Top Layer "Top Layer-MP1" (solid, remove dead copper, pour order 1327): 240.155,190.132 247.225,190.132 247.225,184.233 240.167,184.233
MP4 on Top Layer "Top Layer-MP4" (solid, remove dead copper, pour order 1326): 239.98,205.508 247.05,205.508 247.05,199.61 239.992,199.61
I_SN_L3- on Top Layer "Top Layer-I_SN_L2-" (solid, remove dead copper, pour order 1323): 107.256,142.605 107.294,142.605 112.726,148.036 112.726,150.435 106.286,156.875 100.132,150.721 100.132,149.637
I_SN_L3+ on Top Layer "Top Layer-I_SN_L2-" (solid, remove dead copper, pour order 1320): 107.664,142.039 107.664,142.078 113.41,147.824 115.18,147.824 123.5,139.504 116.848,132.852 116.733,132.852
I_SN_L2+ on Top Layer "Top Layer-I_SN_L2+" (solid, remove dead copper, pour order 1317): 103.548,173.333 115.52,161.361 115.52,156.541 121.163,150.898 126.188,155.923 126.188,161.82 110.44,177.568 107.782,177.568
I_SN_L1- on Top Layer "Top Layer-I_SN_L1-" (solid, remove dead copper, pour order 1315): 107.727,230.6 104.351,230.6 99.028,235.922 99.028,239.172 104.362,244.506 104.362,244.481 112.125,236.718 112.125,234.998
I_SN_L1+ on Top Layer "Top Layer-I_SN_L1+" (solid, remove dead copper, pour order 1314): 115.07,250.974 110.24,246.144 108.263,248.122 105.019,244.878 104.993,244.878 112.765,237.106 116.356,237.106 124.625,245.375 119.026,250.974
V_SN_N on Top Layer "Top Layer-No Net" (solid, remove dead copper, pour order 1308): 161.685,105.5 155.479,105.5 155.479,123.043 161.685,123.038
VDC_MID on Top Layer "Top Layer-VDC_MID" (solid, remove dead copper, pour order 1307): 165.879,123.194 165.879,103.767 185.042,103.767 185.042,112.663 179.034,112.666 168.511,123.194
no net on Top Layer "Top Layer-No Net 1" (solid, remove dead copper, pour order 1291): 204.413,282.403
GND on Signal Layer 1 "SIGNAL_LAYER_1_GND_P1575" (solid, remove dead copper, pour order 1575): 121 vertices, not listed, extent -0.1,0.407 270,345.207
VDC- on Signal Layer 1 "Top Layer-VDC- 3" (solid, remove dead copper, pour order 1882): 145.994,16.7 145.994,13.236 145.998,13.232 149.13,10.1 156.9,10.1 156.9,16.7
AMC_HGND_L2 on Signal Layer 1 "Bottom Layer-AMC_HGND_L2" (solid, pour order 1858): 19.354,132.698 26.954,132.698 26.954,124.012 19.354,124.012
AMC_HGND_L3 on Signal Layer 1 "Bottom Layer-AMC_HGND_L3" (solid, pour order 1856): 19.354,148.771 26.954,148.771 26.954,136.371 19.354,136.371
AMC_HGND_L1 on Signal Layer 1 "SIGNAL_LAYER_1_AMC_HGND_L1_P1850" (solid, pour order 1850): 19.331,164.956 26.931,164.956 26.931,152.556 19.331,152.556
V_SN_N on Signal Layer 1 "Top Layer-No Net" (solid, remove dead copper, pour order 1744): 46 vertices, not listed, extent 103.708,112.6 161.798,227.463
V_PCC_N on Signal Layer 1 "Signal Layer 1-V_PCC_N" (solid, pour order 1504): 17 vertices, not listed, extent 14.2,59.3 81.3,108.7
VDC-_REF on Signal Layer 1 "Top Layer-REF_SN_L1" (solid, remove dead copper, pour order 1820): 171.735,30 145.994,30 145.994,27.5 132.105,27.5 132.105,35 171.735,35
REF_SN_L2 on Signal Layer 1 "Signal Layer 1-REF_SN_L1" (solid, remove dead copper, pour order 1459): 17 vertices, not listed, extent 172.709,167.328 211.193,180.995
REF_SN_L3 on Signal Layer 1 "Signal Layer 1-REF_SN_L1" (solid, remove dead copper, pour order 1446): 17 vertices, not listed, extent 172.594,76.219 211.078,89.887
RLAY_2 on Signal Layer 1 "Signal Layer 2-RLAY_2" (solid, pour order 1790): 19 vertices, not listed, extent 16.2,44.515 39.8,111.3
AEF_CHK_3 on Signal Layer 1 "Bottom Layer-AEF_CHK_3" (solid, pour order 1788): 18 vertices, not listed, extent 16,139.496 48.7,206.3
GRID_GND on Signal Layer 1 "SIGNAL_LAYER_1_GRID_GND_P1754" (solid, remove dead copper, pour order 1754): 60.194,140.021 68.468,140.021 68.468,127.347 60.194,127.347
REF_MID3 on Signal Layer 1 "Signal Layer 1-REF_MID1" (solid, remove dead copper, pour order 1451): 170.942,130.881 170.942,126.791 170.096,125.944 170.096,124.348 173.504,124.348 184.249,124.348 184.323,124.423 184.323,117.387 196.515,117.387 196.515,130.881
REF_MID2 on Signal Layer 1 "Signal Layer 1-REF_MID1" (solid, remove dead copper, pour order 1450): 173.385,215.406 184.129,215.406 184.204,215.48 184.204,208.445 196.396,208.445 196.396,221.939 169.983,221.939 169.976,215.406
REF_MID1 on Signal Layer 1 "Signal Layer 1-REF_MID1" (solid, remove dead copper, pour order 1337): 173.281,306.461 184.025,306.461 184.1,306.536 184.1,299.5 196.292,299.5 196.292,312.994 169.879,312.994 169.872,306.461
VDC_NEG_IN on Signal Layer 1 "SIGNAL_LAYER_1_VDC_NEG_IN_P1750" (solid, remove dead copper, pour order 1750): 136.598,27.059 146.265,27.059 146.265,19.421 143.032,16.188 136.598,22.622
VDC_MID_IN on Signal Layer 1 "SIGNAL_LAYER_1_VDC_MID_IN_P1752" (solid, remove dead copper, pour order 1752): 123.149,27.182 132.816,27.182 132.816,19.091 128.485,14.761 123.149,20.097
GND_ISO_CAN on Signal Layer 1 "SIGNAL_LAYER_1_GND_ISO_CAN_P1720" (solid, remove dead copper, pour order 1720): 164.143,334.813 168.392,339.063 219.427,339.063 223.786,334.813 259.08,334.813 259.08,345 167.64,345 144.794,345 144.794,327.613 156.943,327.613
VDC+ on Signal Layer 1 "Signal Layer 1-VDC+ 2" (solid, remove dead copper, pour order 1708): 20 vertices, not listed, extent 211.499,71 246.408,126.396
RLAY_1 on Signal Layer 1 "SIGNAL_LAYER_1_RLAY_1_P1680" (solid, remove dead copper, pour order 1680): 9.3,96.984 2.005,96.984 0.004,94.984 0.004,44.485 5.505,44.482 5.505,65.066 11.505,71.066 11.505,94.779
V_PCC_L3 on Signal Layer 1 "SIGNAL_LAYER_1_V_PCC_L3_P1678" (solid, pour order 1678): 59,52.515 70.86,52.515 70.86,55.015 73.526,55.015 73.526,42.015 59,42.015
V_PCC_L2 on Signal Layer 1 "SIGNAL_LAYER_1_V_PCC_L2_P1666" (solid, pour order 1666): 32.901,52.515 45.333,52.515 45.333,55.015 47.999,55.015 47.999,42.015 32.901,42.015
V_PCC_L1 on Signal Layer 1 "SIGNAL_LAYER_1_V_PCC_L1_P1634" (solid, pour order 1634): 8,52.5 19.346,52.5 19.346,55 22.012,55 22.012,42 8,42
PCC_L3 on Signal Layer 1 "Top Layer-PCC_L1" (solid, pour order 1632): 86.985,25.978 65.985,25.978 65.985,1.978 86.985,1.978
PCC_L2 on Signal Layer 1 "Top Layer-PCC_L1" (solid, pour order 1624): 62.039,25.978 41.039,25.978 41.039,1.978 62.039,1.978
PCC_L1 on Signal Layer 1 "Top Layer-PCC_L1" (solid, pour order 1612): 36,26 15,26 15,2 36,2
I_SN_L3+ on Signal Layer 1 "Signal Layer 2-I_SN_L3+" (solid, pour order 1559): 127.034,66.741 120.217,59.924 99.408,80.732 106.261,87.514
DESAT_BOT_L3 on Signal Layer 1 "Bottom Layer-DESAT_BOT_L2" (solid, remove dead copper, pour order 1515): 140.892,94.242 145.892,99.242 153.883,91.251 148.882,86.251
VDC+ on Signal Layer 1 "Signal Layer 1-VDC+" (solid, remove dead copper, pour order 1300): 25 vertices, not listed, extent 149.243,2.006 268,295.98
VDC+ on Signal Layer 1 "SIGNAL_LAYER_1_VDC+_P1554" (solid, pour order 1554): 268.5,234.014 268.5,236.014 267.624,236.014 267.624,234.014
VDC+ on Signal Layer 1 "SIGNAL_LAYER_1_VDC+_P1553" (solid, pour order 1553): 268.5,143 268.5,145 267.624,145 267.624,143
I_SN_L3- on Signal Layer 1 "Bottom Layer-I_SN_L3-" (solid, remove dead copper, pour order 1321): 109.843,183.357 119.543,193.057 125.934,186.666 125.934,160.8 107.164,142.568 107.164,142.739 99.83,150.073 99.826,155.426 114.25,169.85 114.25,178.95
I_SN_L1+ on Signal Layer 1 "Top Layer-I_SN_L1+" (solid, remove dead copper, pour order 1516): 115.11,250.974 110.446,246.31 110.278,246.31 109.844,246.744 106.486,243.386 112.765,237.106 116.306,237.106 124.64,245.44 119.106,250.974
DESAT_BOT_L2 on Signal Layer 1 "Bottom Layer-DESAT_BOT_L2" (solid, remove dead copper, pour order 1511): 141.092,185.608 146.092,190.608 154.083,182.618 149.082,177.617
DESAT_BOT_L1 on Signal Layer 1 "SIGNAL_LAYER_1_DESAT_BOT_L1_P1508" (solid, remove dead copper, pour order 1508): 141.01,276.19 146.455,281.634 154.445,273.643 149.001,268.199
CHK_1 on Signal Layer 1 "Signal Layer 1-CHK_1" (solid, pour order 1492): 21 vertices, not listed, extent 11.9,93.1 46.3,153.1
VDC-_REF on Signal Layer 1 "Bottom Layer-REF_MID1" (solid, remove dead copper, pour order 1467): 126.718,6.5 132.502,6.502 139.75,13.75 139.75,16.75 141,18 145,14 145,12.937 132.063,0 130,0 121,0 121,6.5
REF_MID3 on Signal Layer 1 "Bottom Layer-REF_MID1" (solid, remove dead copper, pour order 1466): 121,16.8 121,9.657 132.105,9.657 132.105,10.695 126,16.8
REF_SN_L1 on Signal Layer 1 "Signal Layer 1-REF_SN_L1" (solid, remove dead copper, pour order 1460): 17 vertices, not listed, extent 172.806,258.328 211.29,271.995
DESAT_BOT_L1 on Signal Layer 1 "Signal Layer 2-DESAT_BOT_L1" (solid, remove dead copper, pour order 1339): 205.304,273.204 202.487,273.204 199.498,276.193 199.498,300.758 204.2,300.758 204.2,277.101 205.174,276.127 208.484,276.122 209.448,275.159 209.448,270.77 205.69,270.77 205.69,272.818
DESAT_BOT_L2 on Signal Layer 1 "Signal Layer 2-DESAT_BOT_L1" (solid, remove dead copper, pour order 1377): 205.404,182.204 202.587,182.204 199.598,185.193 199.598,209.758 204.012,209.758 204.012,186.389 205.274,185.127 208.584,185.122 209.346,184.36 209.346,182.362 209.346,178.659 206.494,178.659 206.494,181.114
DESAT_BOT_L3 on Signal Layer 1 "Signal Layer 2-DESAT_BOT_L1" (solid, remove dead copper, pour order 1379): 205.304,91.204 202.487,91.204 199.498,94.193 199.498,118.758 203.912,118.758 203.912,95.389 205.174,94.127 208.484,94.122 209.246,93.36 209.246,91.362 209.246,87.544 206.494,87.544 206.494,90.014
REF_VDC-3 on Signal Layer 1 "Signal Layer 1-REF_VDC-1" (solid, remove dead copper, pour order 1452): 231.717,120.942 233.239,122.464 233.23,131.246 205.83,131.246 205.555,131.242 205.555,130.718 206.817,130.718 206.817,117.442 214.255,117.442 214.255,120.942
REF_VDC-2 on Signal Layer 1 "Signal Layer 1-REF_VDC-1" (solid, remove dead copper, pour order 1449): 205.771,222.291 205.496,222.288 205.496,221.763 206.758,221.763 206.758,208.487 214.196,208.487 214.196,211.987 233.181,211.987 233.171,222.291
REF_VDC-1 on Signal Layer 1 "Signal Layer 1-REF_VDC-1" (solid, remove dead copper, pour order 1338): 205.975,313.204 205.7,313.2 205.7,312.676 206.961,312.676 206.961,299.4 214.4,299.4 214.4,302.9 233.385,302.9 233.375,313.204
L3_MID_DRAIN on Signal Layer 1 "Signal Layer 2-L1_MID_DRAIN" (solid, remove dead copper, pour order 1378): 184.378,103.542 187.142,103.542 188.91,101.775 188.91,88.04 189.05,87.9 192.612,87.9 192.88,88.168 192.88,111.447 191.949,112.378 183.083,112.378 181.052,114.409 181.052,119.52 177.242,119.52 177.242,110.678
L2_MID_DRAIN on Signal Layer 1 "Signal Layer 2-L1_MID_DRAIN" (solid, remove dead copper, pour order 1376): 184.478,194.542 187.242,194.542 189.01,192.775 189.01,179.04 189.15,178.9 192.712,178.9 192.98,179.168 192.98,202.447 192.049,203.378 183.183,203.378 181.152,205.409 181.152,210.52 177.342,210.52 177.342,201.678
L1_MID_DRAIN on Signal Layer 1 "Signal Layer 2-L1_MID_DRAIN" (solid, remove dead copper, pour order 1340): 184.378,285.542 187.142,285.542 188.91,283.775 188.91,269.9 192.612,269.9 192.88,270.168 192.88,293.447 191.949,294.378 183.083,294.378 181.1,296.361 181.1,301.52 177.242,301.52 177.242,292.678
VDC+ on Signal Layer 1 "Signal Layer 1-VDC+ 2" (solid, remove dead copper, pour order 1336): 21 vertices, not listed, extent 211.878,162.106 246.786,217.136

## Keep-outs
Bottom Layer:
  region: 118.27,164.652 128.215,154.707 119.673,146.165 143.281,122.558 180.404,159.681 156.796,183.289 148.184,174.676 138.239,184.621 146.851,193.234 138.685,201.4 101.561,164.277 109.728,156.11
  region: 118.266,255.623 128.211,245.678 119.669,237.136 143.277,213.528 180.4,250.652 156.792,274.259 148.18,265.647 138.235,275.592 146.847,284.204 138.681,292.371 101.558,255.248 109.724,247.081
  region: 118.27,73.66 128.215,63.715 119.673,55.173 143.281,31.565 180.404,68.688 156.796,92.296 148.184,83.684 138.239,93.629 146.851,102.241 138.685,110.407 101.562,73.284 109.728,65.118
Keep-Out Layer:
  text ".Layer_Name" at -4.444,-20.006 h0.76

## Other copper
Top Layer:
  region net I_SN_L2-: 41.973,190.114 42.106,189.982 50.999,189.982 50.999,185.07 50.919,184.991 41.713,184.991 39.256,187.425 34.866,191.815 36.842,193.791 38.296,193.791
  region net I_SN_L3-: 27.74,204.75 25.2,202.21 25.2,200.103 31.303,194 32.612,194 35.612,197 39.7,197 42.7,194 51.002,194 51.002,199.991 36.681,199.991 35.272,201.4 33.3,201.4 29.95,204.75
  region: 27.349,205.015
  region net AEF_CHK_2: 39.407,184.019 41.629,184.019 44.935,180.713 42.272,178.05 37.855,182.467
  region net I_SN_L1-: 38.3,207.8 38.3,203.3 50.997,203.3 50.998,203.3 50.998,207.995 38.305,207.995 38.3,208
  region net AEF_CHK_2: 27.87,123.319
  region: 27.871,139.094
  region: 27.906,155.633
  pour cut-out: 271,74.472 258.332,74.472 258.332,88.659 271,88.659
  pour cut-out: 271,106.473 258.332,106.473 258.332,120.66 271,120.66
  pour cut-out: 271.046,180.135 258.378,180.135 258.378,194.322 271.046,194.322
  pour cut-out: 271.046,212.136 258.378,212.136 258.378,226.323 271.046,226.323
  pour cut-out: 271,301.514 258.332,301.514 258.332,315.701 271,315.701
  pour cut-out: 271,269.513 258.332,269.513 258.332,283.7 271,283.7
  pour cut-out: 259.954,282.005
  pour cut-out: 155.173,342.392 155.173,337.695 160.559,337.695 160.559,342.392
  pour cut-out: 144.794,334.617 144.794,329.56 153.43,329.56 153.43,334.617
  pour cut-out: 92.372,336.506 92.372,334.936 95.902,334.936 95.902,336.464
  pour cut-out: 25.642,59.246 25.642,66.458 38.103,66.458 38.103,59.279
  pour cut-out: 51.54,59.264 51.54,66.476 64.001,66.476 64.001,59.297
  pour cut-out: 124.498,44.8 125.198,44.8 125.198,42.348 124.498,42.348
  pour cut-out: 123.998,44.9
  pour cut-out: 134.798,44.8 136.298,44.8 136.298,42.384 134.798,42.384
  pour cut-out: 167.6,44.8 169.1,44.8 169.1,42.384 167.6,42.384
  pour cut-out: 156.8,44.9
  pour cut-out: 157.3,44.8 158,44.8 158,42.348 157.3,42.348
  pour cut-out: 103.239,239.341 103.036,239.137 100.953,241.22 101.157,241.424
  pour cut-out: 110.274,246.111 110.07,245.907 107.987,247.99 108.191,248.194
  pour cut-out: 104.069,145.639 103.866,145.843 105.949,147.926 106.152,147.722
  pour cut-out: 110.698,138.853 110.902,138.65 112.985,140.732 112.781,140.936
  pour cut-out: 99.888,176.862 99.684,177.066 101.767,179.149 101.971,178.945
  pour cut-out: 106.797,169.934 106.593,170.137 108.676,172.22 108.88,172.016
  text ".Layer_Name" at -25.064,56.36 h0.76
Signal Layer 1:
  region net AEF_CHK_2: 39.407,184.019 41.629,184.019 44.935,180.713 42.572,178.35 38.155,182.767
  region net I_SN_L3-: 27.74,204.75 25.2,202.21 25.2,200.103 31.303,194 32.612,194 35.612,197 39.7,197 42.7,194 51.002,194 51.002,199.991 36.681,199.991 35.272,201.4 33.3,201.4 29.95,204.75
  region net I_SN_L2-: 41.977,190.123 42.109,189.991 51.002,189.991 51.002,185.079 50.923,185 41.716,185 39.26,187.434 34.869,191.824 36.845,193.8 38.3,193.8
  region net I_SN_L1-: 38.3,207.8 38.3,203.3 50.997,203.3 50.998,203.3 50.998,207.995 38.305,207.995 38.3,208
  region net +12V_OUT: 102.932,334.621 102.932,333.288 102.09,333.288 102.09,334.65 99.314,334.65 99.314,335.797 102.932,335.797
  region net VIN_PWR: 98.201,333.288 101.819,333.288 101.819,334.427 98.201,334.427
  pour cut-out: 109.742,246.719 102.828,239.806 101.16,241.474 108.073,248.388
  pour cut-out: 101.07,178.305 107.984,171.391 106.54,169.947 99.627,176.861
  pour cut-out: 105.272,147.057 112.185,140.143 110.517,138.475 103.604,145.388
  pour cut-out: 51.498,59.32 51.498,66.532 63.958,66.532 63.958,59.353
  pour cut-out: 25.6,59.301 25.6,66.514 38.061,66.514 38.061,59.335
Signal Layer 2:
  region net AEF_CHK_2: 39.407,184.019 41.629,184.019 44.935,180.713 42.272,178.05 37.855,182.467
  region net I_SN_L2-: 41.973,190.114 42.106,189.982 50.999,189.982 50.999,185.07 50.919,184.991 41.713,184.991 39.256,187.425 34.866,191.815 36.842,193.791 38.296,193.791
  region net I_SN_L3-: 27.74,204.75 25.2,202.21 25.2,200.103 31.303,194 32.612,194 35.612,197 39.7,197 42.7,194 51.002,194 51.002,199.991 36.681,199.991 35.272,201.4 33.3,201.4 29.95,204.75
  region net I_SN_L1-: 38.3,207.8 38.3,203.3 50.997,203.3 50.998,203.3 50.998,207.995 38.305,207.995 38.3,208
  region net +12V_OUT: 102.932,334.612 102.932,333.279 102.09,333.279 102.09,334.65 99.314,334.65 99.314,335.788 102.932,335.788
  region net VIN_PWR: 95.914,333.288 95.148,334.054 93.3,334.054 92.926,333.68 92.926,332.791 93.256,332.461 93.256,331.04 91.502,331.04 91.502,333.675 92.427,334.6 98.049,334.6 98.232,334.416 101.819,334.416 101.819,333.288
  pour cut-out: 105.271,147.068 112.184,140.154 110.516,138.486 103.602,145.4
  pour cut-out: 109.742,246.719 102.828,239.806 101.16,241.474 108.073,248.388
  pour cut-out: 101.07,178.305 107.984,171.391 106.54,169.947 99.627,176.861
Bottom Layer:
  region net VIN_PWR: 92.937,334
  region net VIN_PWR: 92.606,334.6
  region net +12V_OUT: 102.932,334.612 102.932,333.279 102.09,333.279 102.09,334.65 99.314,334.65 99.314,335.788 102.932,335.788
  region net VIN_PWR: 98.218,333.292 101.836,333.292 101.836,334.416 98.218,334.416
  pour cut-out: 271,269.509 258.332,269.509 258.332,283.696 271,283.696
  pour cut-out: 271,301.511 258.332,301.511 258.332,315.698 271,315.698
  pour cut-out: 271.046,212.132 258.378,212.132 258.378,226.319 271.046,226.319
  pour cut-out: 271.046,180.131 258.378,180.131 258.378,194.318 271.046,194.318
  pour cut-out: 271,106.469 258.332,106.469 258.332,120.656 271,120.656
  pour cut-out: 271,74.468 258.332,74.468 258.332,88.655 271,88.655
  pour cut-out: 259.954,282.002
  pour cut-out: 154.787,342.363 154.787,337.666 160.173,337.666 160.173,342.363
  pour cut-out: 144.794,334.617 144.794,329.56 153.43,329.56 153.43,334.617
  pour cut-out: 92.92,336.73 92.92,334.6 95.102,334.6 95.102,336.704
  pour cut-out: 101.067,178.281 107.981,171.367 106.468,169.855 99.555,176.768
  pour cut-out: 105.271,147.068 112.184,140.154 110.516,138.486 103.602,145.4
  pour cut-out: 109.742,246.719 102.828,239.806 101.16,241.474 108.073,248.388
  text ".Layer_Name" at -25.064,56.36 h0.76

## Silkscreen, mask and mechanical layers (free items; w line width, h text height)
Top Overlay:
  circle w0.254: c104.943,299.278 r0.027
  circle w0.254: c93.781,286.803 r0.027
  circle w0.254: c78.496,278.129 r0.027
  circle w0.254: c64.389,133.901 r0.066
  circle w0.254: c220.263,88.199 r0.102
  circle w0.254: c220.167,179.117 r0.102
  circle w0.254: c220.167,270.14 r0.102
  circle w0.254: c74.964,121.351 r0.041
  circle w0.254: c121,293.215 r0.027
  circle w0.254: c1.208,119.7 r0.065
  circle w0.254: c61.112,86.97 r0.131
  circle w0.254: c108.153,314.146 r0.103
  circle w0.254: c119.405,328.973 r0.103
  circle w0.254: c78.943,330.479 r0.065
  lines w0.1: 238.23,341.39 238.512,341.108 ; 238.512,342.381 238.512,341.097 238.512,341.108 ; 238.795,341.39 238.512,341.108 ; 239.435,335.072 239.718,335.354 ; 239.718,334.081 239.718,335.365 239.718,335.354 ; 240,335.072 239.718,335.354 ; 245.946,321.457 247.231,321.457 247.22,321.457 ; 246.937,321.174 247.22,321.457 ; 246.937,321.739 247.22,321.457 ; 256.731,321.172 256.449,321.454 ; 256.731,321.737 256.449,321.454 ; 257.723,321.454 256.438,321.454 256.449,321.454
  lines w0.127: 169.878,285.165 244.878,285.165 ; 169.878,286.165 244.878,286.165 ; 169.88,103.201 244.88,103.201 ; 169.88,104.201 244.88,104.201 ; 169.88,194.197 244.88,194.197 ; 169.88,195.197 244.88,195.197 ; 170.022,275.35 244.878,275.35 ; 170.022,295.98 244.878,295.98 ; 170.024,93.387 244.88,93.387 ; 170.024,114.016 244.88,114.016 ; 170.024,184.382 244.88,184.382 ; 170.024,205.011 244.88,205.011
  text "ISO PWR to EXT" at 212.372,342.738 h0.76
  text "ISO PWR to EXT" at 234.004,342.728 h1.02
  text "+12VIN" at 77.412,342.605 h2
  text "Aux Power Supply" at 99.92,342.316 h2
  text "GND" at 110.232,341.02 h1.02
  text "CANH" at 244.296,340.998 h1.02 r90
  text "DACx" at 62.865,339.776 h1.02 r90
  text "CAN_GND" at 249.9,339.063 h1.02 r90
  text "12V PWR EN" at 119.029,338.363 h1
  text "GND" at 58.699,338.2 h1.02
  text "TMP235" at 55.11,336.829 h1.27
  text "eFuse" at 99.377,336.419 h1.02
  text "ISO CAN" at 148,335.783 h1.02
  text "12V to LV Rails" at 119.029,334.491 h1
  text "EXT AUX PWR" at 236.948,332.89 h1.02
  text "CANL" at 245.567,332.803 h1.02 r90
  text "SN ISENSE" at 67.035,332.393 h1
  text "12V" at 110.167,332.13 h1.02
  text "79D" at 68.402,331.241 h1.02
  text "AUX PWR IN" at 89.138,329.541 h1.02
  text "GND" at 134.62,329.493 h0.75
  text "CAN_GND" at 145.805,329.489 h0.75
  text "AUX VIN PWR" at 131.496,327.66 h0.75
  text "VIN PWR CAN" at 145.84,327.613 h0.75
  text "DC ISENSE" at 89.618,326.11 h1
  text "ISOW1044" at 137.211,324.79 h2
  text "5V" at 108.153,324.444 h2
  text "39C" at 68.457,324.051 h1.02
  text "SELECT ONLY ONE OF THESE MCU REFERENCES: /  / A: VDC MID  / B: VDC- / C: GRID GND / PE" at 236.1,322.676 h1.5
  text "GND" at 200.914,321.793 h1.02
  text "UCC14341" at 233.909,319.811 h1.27 r270
  text "UCC14341" at 185.318,319.608 h1.27 r270
  text "UCC5350" at 194.361,319.507 h1.27 r270
  text "3.3VREF" at 91.948,319.209 h1.02
  text "LDO VIN" at 105.076,318.262 h1.02 r90
  text "79D" at 69.12,318.16 h1.02
  text "79D" at 75.242,317.805 h1.02
  text "1.65VREF" at 95.182,317.353 h1.02
  text "A: VDC MID" at 242.308,317.089 h1.02
  text "B: VDC-" at 256.727,317.089 h1.02
  text "MID BIAS" at 174.574,316 h2
  text "BOT BIAS" at 222.08,316 h2
  text "UCC217x" at 206.031,315.214 h1.27 r90
  text "39C" at 69.12,314.63 h1.02
  text "39C" at 75.209,314.242 h1.02
  text "79D" at 75.185,311.556 h1.02
  text "3.3Va2" at 108.393,311.249 h1.02
  text "FAN DRV" at 128.8,308.2 h1.02
  text "39C" at 75.336,308.051 h1.02
  text "DC VSENSE" at 86.817,307.721 h1
  text "79D" at 51.193,301.475 h1.02
  text "LDO VIN" at 117.484,301.215 h1.02
  text "MID" at 170.798,299.12 h2
  text "BOT" at 219.905,298.5 h2
  text "PWM Buffers" at 104.233,293.266 h1.02
  text "39C" at 50.452,292.532 h1.02
  text "3.3V" at 121.599,290.274 h1.02
  text "LINE1" at 161,285.165 h2
  text "PWM Buffers" at 92.71,280.695 h1.02
  text "GND" at 105.292,277.894 h2.54
  text "PWM Buffers" at 77.539,272.27 h1.02
  text "CLK BUFF" at 56.921,271.551 h1.02
  text "M_SN" at 168.05,271.359 h2
  text "ISOTMP35" at 217.118,267.345 h1.02
  text "TOP" at 211.9,264.719 h2
  text "MAGNETO EN" at 96.402,263.718 h1.02
  text "UCC217x" at 209.906,256.388 h1.27 r270
  text "SN ISENSE L1" at 84.625,255.242 h1.27
  text "SN BIAS" at 185.298,253.498 h2
  text "UCC5350" at 173.304,251.568 h1.27 r90
  text "UCC14341" at 182.118,251.389 h1.27 r90
  text "TMCS1123" at 92.769,245.483 h2 r315
  text "GND" at 195.894,243.713 h1.02
  text "SN L1" at 98.129,234.95 h2
  text "GND" at 200.279,230.589 h1.02
  text "UCC14341" at 233.756,229.006 h1.27 r270
  text "UCC14341" at 185.496,228.981 h1.27 r270
  text "UCC5350" at 194.539,228.879 h1.27 r270
  text "RES60A" at 123.419,228.473 h2 r270
  text "MID BIAS" at 174.799,225.5 h2
  text "BOT BIAS" at 222.305,225.5 h2
  text "UCC217x" at 205.765,224.231 h1.27 r90
  text "SN VSENSE L1" at 78.555,223.449 h1.27
  text "AMC0330R" at 96.088,220.142 h1.27
  text "SN VSENSE L2" at 78.551,216.304 h1.27
  text "AMC0330R" at 96.088,212.42 h1.27
  text "MID" at 170.863,207.605 h2
  text "BOT" at 219.97,206.985 h2
  text "LINE2" at 161,194 h2
  text "RES60A" at 111.862,186.207 h2 r45
  text "SN L2" at 95.352,185.416 h2
  text "M_SN" at 168.05,179.844 h2
  text "ISOTMP35" at 216.662,176.378 h1.02
  text "TOP" at 212.634,173.925 h2
  text "PCC ISENSE" at 10.262,168.173 h2
  text "UCC217x" at 210.033,165.456 h1.27 r270
  text "SN ISENSE L2" at 83.922,164 h1.27
  text "TMCS1123" at 103.214,161.808 h2 r45
  text "SN BIAS" at 185.94,161.798 h2
  text "UCC5350" at 173.228,160.884 h1.27 r90
  text "UCC14341" at 182.321,160.655 h1.27 r90
  text "UCC14131" at 52.261,160.071 h2
  text "GND" at 196.057,152.112 h1.02
  text "AMC3306" at 11.532,151.384 h2
  text "SN L3" at 103.353,149.885 h2
  text "GND" at 198.78,143.916 h1.02
  text "UCC14341" at 234.117,138.125 h1.27 r270
  text "RES60A" at 122.577,138 h2 r270
  text "UCC14341" at 185.527,137.922 h1.27 r270
  text "UCC5350" at 194.57,137.82 h1.27 r270
  text "UCC217x" at 217.658,137.77 h1.27 r270
  text "AMC3306" at 11.808,135.179 h2
  text "MID BIAS" at 174.747,134.197 h2
  text "BOT BIAS" at 222.253,134.197 h2
  text "SN ISENSE L3" at 87.548,132.417 h1.27
  text "LDO VIN" at 76.743,132.26 h1.02 r90
  text "GND" at 8.975,131.722 h1.02
  text "LDO VIN" at 2.853,131.115 h1.02 r90
  text "TMCS1123" at 107.499,130.566 h2 r45
  text "TPSF12C3" at 59.402,124.262 h2
  text "SN VSENSE L3" at 83.185,124.136 h1.27
  text "SN NEUTRAL" at 128.499,122.936 h2
  text "AEF" at 59.357,121.656 h2
  text "AMC0330R" at 99.884,120.001 h1.27
  text "AMC3306" at 11.465,118.9 h2
  text "3.3Vd" at 6.491,118.8 h1.02 r90
  text "3.3Va" at 75.102,118.432 h1.02
  text "PE" at 124.257,118.059 h2 r90
  text "MID" at 170.7,116.26 h2
  text "BOT" at 219.807,115.64 h2
  text "UCC33421" at 100.033,111.421 h1.27
  text "LINE3" at 161,103.201 h2
  text "UCC33421" at 57.993,100.477 h1.27
  text "L1" at 72.517,95.021 h2
  text "PCC VSENSE" at 71.169,91.019 h2
  text "AMC0330R" at 57.801,90.716 h1.27
  text "M_SN" at 168.05,88.499 h2
  text "ISOTMP35" at 217.097,85.416 h1.02
  text "L2" at 75.596,85.09 h2
  text "TOP" at 212.471,82.58 h2
  text "AMC0330R" at 61.205,80.823 h1.27
  text "L3" at 79.299,75.362 h2
  text "UCC217x" at 209.959,74.143 h1.27 r270
  text "SN BIAS" at 185.94,70.949 h2
  text "AMC0330R" at 65.161,70.566 h1.27
  text "UCC5350" at 173.285,69.469 h1.27 r90
  text "UCC14341" at 182.22,69.416 h1.27 r90
  text "GND" at 195.489,64.29 h1.02
  text ".Layer_Name" at -25.064,56.36 h2
  text "GND" at 166.294,50.267 h1.02
  text "VDC+ VSEN" at 152.781,47.828 h1.27
  text "RES60A" at 39.226,47.57 h2
  text "RES60A" at 65.089,47.519 h2
  text "VMID VSEN" at 117.699,47.497 h1.27
  text "RES60A" at 13.322,47.27 h2
  text "RELAY DRV" at 84.201,45.161 h1.02
  text ".PRJ_Number /  / REV: .PCB_Rev" at 195.149,37.384 h4
  text "AMC0381" at 123.3,35.998 h1.27 r90
  text "UCC33421" at 139.439,35.998 h1.27 r90
  text "AMC0381" at 155.9,35.998 h1.27 r90
  text "C: GRID GND / PE" at 107.745,34.739 h1.02
  text "PE" at 116.073,32 h2.54
  text "AC Range: 120-230 VRMS (VPhase) / MAX Current 16A RMS / MAX POWER 11kVA / Line Frequency: 50/60 Hz" at 1.71,24 h2
  text "PE" at 112.634,20.189 h2.5
  text "VDC-" at 140.042,20.189 h2.5
  text "VDC+" at 153.662,20.189 h2.5
  text "VMID" at 125.539,20.161 h2.5
  text "AMC1302" at 112.979,17.272 h1.27
  text "L3" at 75,9 h5
  text "L1" at 23.019,8.985 h5
  text "L2" at 48.97,8.985 h5
  text "AMC1302" at 112.989,7.366 h1.27
  text "VBUS Range: 650-900 VDC (800V Nom) / MAX Current 16A / MAX POWER 11kW" at 136.598,7 h2
  text "GND" at 101.422,5.461 h1.02
  text "VBUS = VDC+ - VDC- / VMID = Midpoint of VBUS / PE = Protected Earth / Grid GND" at 141.668,2.028 h1.5
Bottom Overlay:
  text "GND" at 93.091,339.674 h1
  text "+12VIN" at 79.578,339.662 h1
  text "CAN CONN" at 249.072,332.208 h2.54
  text "12V INPUT AUX PWR /  / 25-35 W (30W Nom)" at 95.182,323.5 h2.54
  text "FAN CONN" at 160.062,321.564 h2.54
  text "FET THERMAL PADS REQUIRED" at 217.782,317 h2
  text "LINE1" at 166.658,284 h5
  text "LINE2" at 167.162,193 h5
  text "LINE3" at 167.195,102 h5
  text "AC Range: 120-230 VRMS (VPhase) / MAX Current 16A RMS / MAX POWER 11kVA / Line Frequency: 50/60 Hz" at 88,70.328 h3
  text ".Layer_Name" at -25.064,56.36 h0.76
  text "DC Range: 650-900 VDC (800V Nom) / MAX Current 16A / MAX POWER 11kW" at 125.808,39 h3
  text "DC-" at 141,31.217 h2.54
  text "DC+" at 156.185,31.217 h2.54
  text "PE" at 112.497,31.188 h2.54
  text "VMID" at 129,31.188 h2.54
  text "L3" at 84.347,30.6 h2.54
  text "L1" at 32.366,30.569 h2.54
  text "L2" at 58.476,30.569 h2.54
Top Paste:
  text ".Layer_Name" at -4.444,-20.006 h0.76
Bottom Paste:
  text ".Layer_Name" at -4.444,-20.006 h0.76
Top Solder:
  region: 251.11,11.267 ccw(c254.61,11.267) 254.61,7.767 ccw(c254.61,11.267) 258.11,11.267 ccw(c254.61,11.267) 254.61,14.767 ccw(c254.61,11.267)
  text ".Layer_Name" at -4.444,-20.006 h0.76
  text ".Layer_Name" at -4.444,-20.006 h0.76
Bottom Solder:
  text ".Layer_Name" at -4.444,-20.006 h0.76
Drill Guide:
  text ".Layer_Name" at -4.444,-20.006 h0.76
M1 Board Outline:
  lines w0.25: 50,345 50,237.01 50,236.5 0,236.5 0,0 270.002,0 ; 50,345 270,345 270,0
  text ".Layer_Name" at -4.444,-20.006 h0.76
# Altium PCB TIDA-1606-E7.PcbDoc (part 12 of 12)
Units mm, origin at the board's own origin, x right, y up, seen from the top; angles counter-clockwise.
Board outline 270 x 345 mm, 4 copper layers (Top Layer, Signal Layer 1, Signal Layer 2, Bottom Layer), stack 1.69 mm thick; 1263 components, 574 nets, 3595 pads, 4069 vias.
Unrouted connection lines stored in the file: 1719.

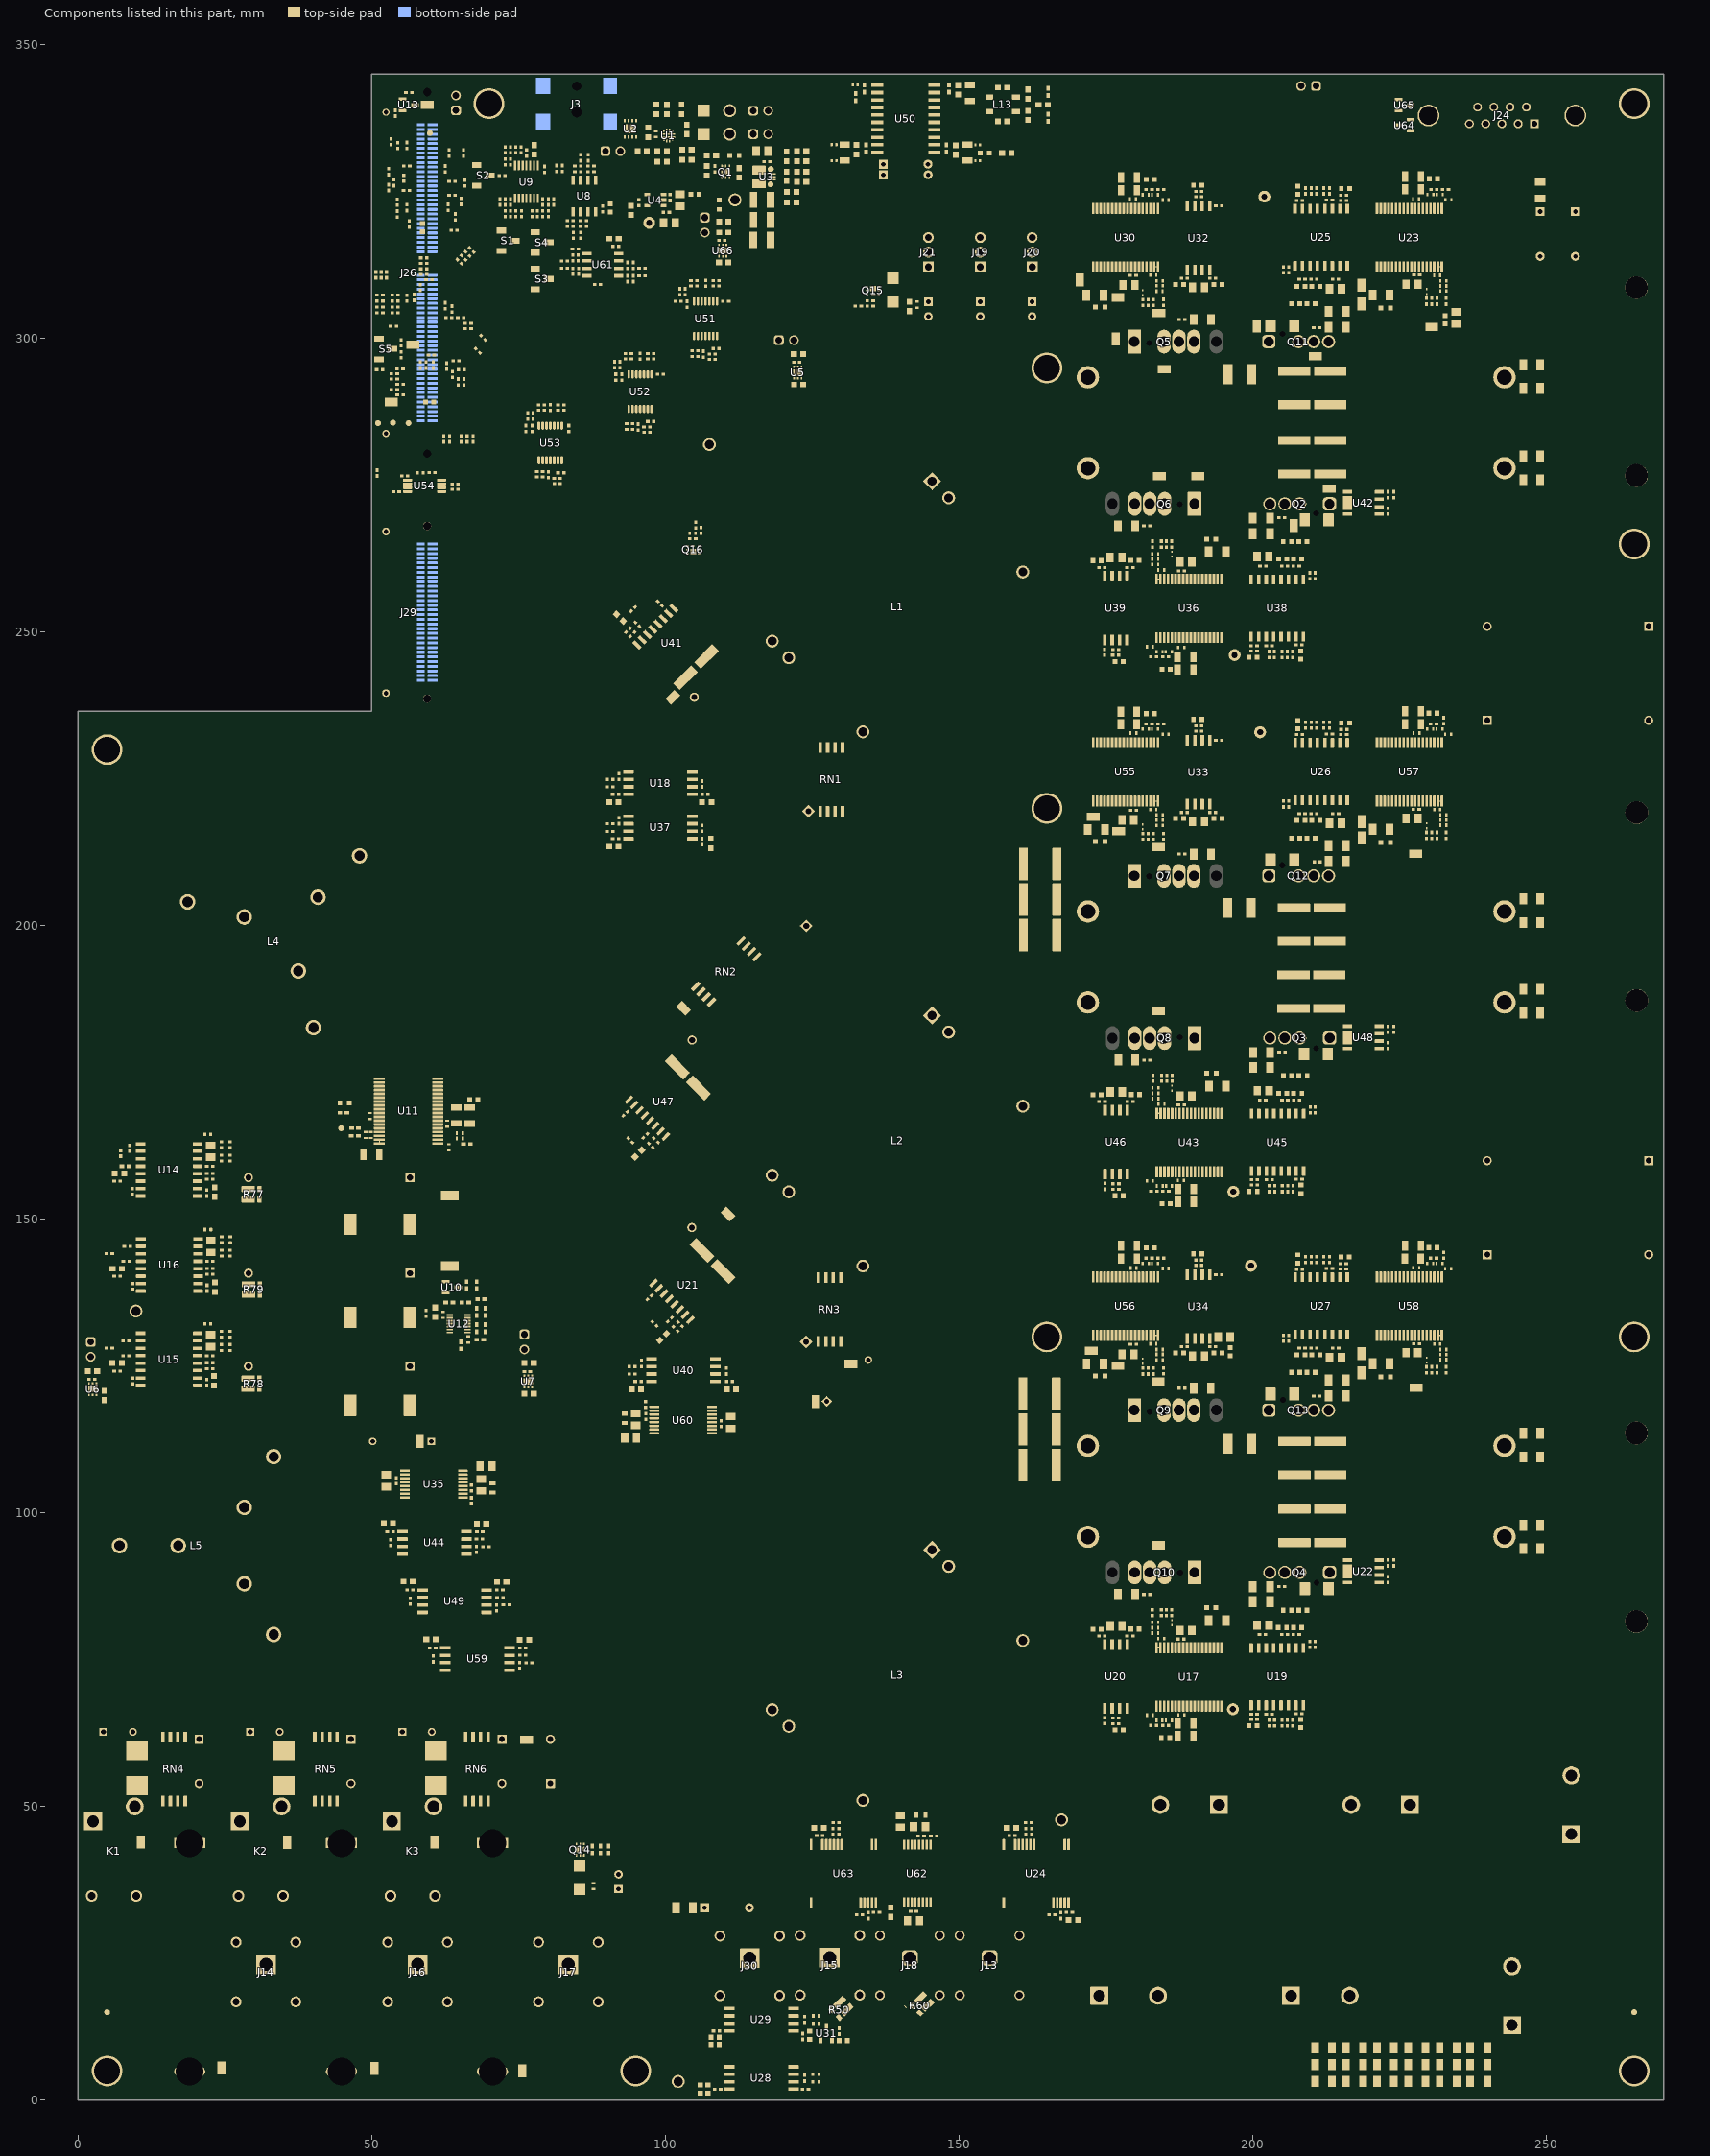
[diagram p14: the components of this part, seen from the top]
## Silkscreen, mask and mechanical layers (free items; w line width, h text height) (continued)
M2 Board Dimensions:
  rectangle: -15.925,-8.36 -6.4,-5.185
  rectangle: -19.1,-5.185 -15.925,-2.01
  lines w0.1: 176.163,271.85 179.973,271.85 ; 176.165,89.887 179.975,89.887 ; 176.165,180.882 179.975,180.882 ; 190.043,299.48 193.853,299.48 ; 190.045,117.516 193.855,117.516 ; 190.045,208.511 193.855,208.511
  lines w0.15: 58.402,264.985 58.402,285.985
  lines w0.178: -19.1,-5.185 6.3,-5.185 ; -15.925,-8.36 -15.925,-2.01 ; -12.75,-8.36 -12.75,-2.01 ; -6.4,-8.36 -6.4,-2.01 ; -0.05,-8.36 -0.05,-2.01 ; -19.1,-8.36 -19.1,-2.01 6.3,-2.01 6.3,-8.36 -19.1,-8.36
  lines w0.25: 1.213,275.363 1.213,342.615 ; 1.398,275.211 44.234,275.251 ; 1.398,342.8 44.248,342.742 ; 44.363,275.38 44.363,280.141 44.4,280.178 47.652,280.178 ; 44.375,342.615 44.375,337.891 44.501,337.891 ; 44.552,337.881 47.623,337.881 ; 48.311,278.355 48.311,278.718 ; 48.334,339.34 48.334,339.755 ; 48.428,278.177 50.405,278.177 ; 48.463,339.884 50.442,339.884 ; 50.566,339.727 50.566,335.382 56.434,335.382 ; 50.568,278.299 50.568,282.928 56.418,282.928 56.439,282.926 ; 51.432,309.542 56.439,309.542 ; 51.432,311.954 51.456,311.956 56.396,311.956 ; 56.56,312.078 56.56,335.233 ; 56.567,283.054 56.568,309.413
  lines w0.254: 1.213,275.363 ccw(c1.37,275.365) 1.398,275.211 ; 1.213,342.615 cw(c1.522,342.491) 1.398,342.8 ; 44.234,275.251 ccw(c44.233,275.38) 44.325,275.289 ccw(c44.236,275.38) 44.363,275.38 ; 44.248,342.742 cw(c44.248,342.615) 44.375,342.615 ; 44.501,337.891 cw(c44.502,337.764) 44.552,337.881 ; 47.623,337.881 ccw(c47.663,338.533) 47.671,337.879 ccw(c47.672,338.742) 48.36,339.263 cw(c48.458,339.339) 48.334,339.34 ; 47.652,280.178 cw(c47.649,279.315) 48.337,278.795 ccw(c48.437,278.718) 48.311,278.718 ; 48.312,278.355 ccw(c48.428,278.304) 48.428,278.177 ; 48.334,339.755 cw(c48.459,339.756) 48.371,339.845 cw(c48.464,339.755) 48.463,339.884 ; 50.405,278.177 ccw(c50.44,278.293) 50.441,278.172 ccw(c50.441,278.299) 50.568,278.299 ; 50.442,339.884 cw(c50.443,339.757) 50.566,339.727 ; 51.432,309.542 cw(c51.441,310.748) 51.432,311.954 ; 56.396,311.956 ccw(c56.432,312.072) 56.432,311.951 ccw(c56.432,312.078) 56.56,312.078 ; 56.434,335.382 cw(c56.434,335.254) 56.56,335.233 ; 56.439,282.926 ccw(c56.439,283.054) 56.567,283.054 ; 56.439,309.542 cw(c56.44,309.415) 56.53,309.504 cw(c56.438,309.411) 56.568,309.413
  text ".Layer_Name" at -4.444,-20.006 h0.76
M3 3D STEP Top:
  text ".Layer_Name" at -25.064,56.36 h0.76
M4 3D STEP Bottom:
  text ".Layer_Name" at -25.064,56.36 h0.76
M5 Assembly Top:
  lines w0.254: -26.517,-21.826 141.123,-21.826 ; -26.517,-16.662 141.174,-16.662 ; -26.517,-11.497 -26.517,-26.991 75.21,-26.991 141.174,-26.991 141.174,-11.497 -26.504,-11.497 -26.504,-26.991 13.514,-26.991 ; 36.094,-26.991 36.094,-11.497 ; 68.276,-16.662 68.276,-11.497 ; 89.612,-16.662 89.612,-11.497 ; 105.411,-27.156 105.411,-22.004
  text "COMPONENTS MARKED 'DNP' SHOULD NOT BE POPULATED." at 10.199,-6.29 h0.76
  text "ASSEMBLY VARIANT:" at 10.186,-9.224 h0.76
  text ".VariantName" at 36.501,-9.224 h0.76
  text "PCB VIEWED FROM TOP SIDE" at -24.904,-14.854 h0.76
  text "BOARD #:" at 37.999,-14.854 h0.76
  text ".PRJ_Number" at 51.855,-14.854 h0.76
  text "REV:" at 73.305,-14.854 h0.76
  text ".PCB_Rev" at 80.709,-14.854 h0.76
  text "SVN REV:" at 94.59,-14.854 h0.76
  text ".VersionControl_RevNumber" at 107.443,-14.854 h0.76
  text "Note: Isolated thermal pads are required for all 12x HV SiC FET assembly (to the heatsink)" at 169.799,-15.215 h1.52
  text "PLOT NAME =" at -24.904,-25.234 h0.76
  text ".plot_File_Name" at -4.444,-25.234 h0.76
  text "GENERATED    :" at 38.05,-25.234 h0.76
  text ".Print_Date" at 60.135,-25.234 h0.76
  text ".Print_Time" at 78.652,-25.234 h0.76
  text "TEXAS INSTRUMENTS" at 110.77,-25.234 h0.76
M6 Assembly Bottom:
  lines w0.254: -26.529,-16.674 141.161,-16.674 ; -26.479,-21.839 141.161,-21.839 ; 9.234,-27.169 9.234,-22.017 ; 25.033,-16.674 25.033,-11.51 ; 46.369,-16.674 46.369,-11.51 ; 78.55,-27.004 78.55,-11.51 ; 101.131,-27.004 141.149,-27.004 141.149,-11.51 -26.529,-11.51 -26.529,-27.004 39.434,-27.004 141.161,-27.004 141.161,-11.51
  text "COMPONENTS MARKED 'DNP' SHOULD NOT BE POPULATED." at 135.891,-6.277 h0.76
  text ".VariantName" at 109.373,-9.224 h0.76
  text "ASSEMBLY VARIANT:" at 135.764,-9.224 h0.76
  text ".VersionControl_RevNumber" at 7.202,-14.867 h0.76
  text "SVN REV:" at 20.054,-14.867 h0.76
  text ".PCB_Rev" at 33.935,-14.867 h0.76
  text "REV:" at 41.339,-14.867 h0.76
  text ".PRJ_Number" at 62.79,-14.867 h0.76
  text "BOARD #:" at 76.645,-14.867 h0.76
  text "PCB VIEWED FROM BOTTOM SIDE" at 139.548,-14.867 h0.76
  text "TEXAS INSTRUMENTS" at 3.874,-25.247 h0.76
  text ".Print_Time" at 35.993,-25.247 h0.76
  text ".Print_Date" at 54.509,-25.247 h0.76
  text "GENERATED    :" at 76.595,-25.247 h0.76
  text ".plot_File_Name" at 119.089,-25.247 h0.76
  text "PLOT NAME =" at 139.548,-25.247 h0.76
M9 Title Sheet:
  drawing of 56 lines, arcs and shapes, not listed
  text "1" at 7.782,341.687 h1.78
  text "2" at 92.254,341.687 h1.78
  text "3" at 176.836,341.687 h1.78
  text "4" at 261.545,341.687 h1.78
  text "5" at 346,341.687 h1.78
  text "6" at 430.709,341.687 h1.78
  text "A" at -30.86,296.526 h1.78
  text "A" at 469.52,296.526 h1.78
  text "B" at -30.86,201.276 h1.78
  text "B" at 469.52,201.276 h1.78
  text "C" at -30.86,106.026 h1.78
  text "C" at 469.52,106.026 h1.78
  text "D" at -30.86,10.776 h1.78
  text "D" at 469.52,10.776 h1.78
  text "PROJECT TITLE:" at 390.932,8.617 h1.14
  text ".PRJ_Title" at 392.202,5.231 h1.78
  text "DESIGNED FOR:" at 390.932,0.972 h1.14
  text ".PRJ_Customer" at 392.202,-2.584 h1.78
  text "FILE NAME:" at 390.932,-6.648 h1.14
  text ".PCB_File_Name_No_Path" at 392.202,-9.696 h1.78
  text "Texas Instruments (TI) and/or its licensors do not warrant the accuracy or completeness of this specification" at 264.707,-13.807 h1.14
  text "ENGINEER:" at 390.932,-14.014 h1.14
  text "LAYOUT BY:" at 429.159,-14.014 h1.14
  text "or any information contained therein. TI and/or its licensors do not warrant that this design will meet" at 263.564,-16.669 h1.14
  text ".PRJ_Engineer" at 392.202,-17.951 h1.78
  text ".PCB_Layout" at 430.442,-17.951 h1.78
  text "the specifications, will be suitable for your application or fit for any particular purpose, or will operate in" at 263.564,-19.53 h1.14
  text ".Layer_Name" at -4.444,-20.006 h0.76
  text "ALTIUM DESIGNER VERSION:" at 429.159,-21.888 h1.14
  text "an implementation. TI and/or its licensors do not warrant that the design is production worthy. You should" at 263.564,-22.392 h1.14
  text "completely validate and test your design implementation to confirm the system functionality for your application." at 264.707,-25.254 h1.14
  text ".print_Scale" at 392.202,-25.275 h1.78
  text ".Application_BuildNumber" at 430.442,-25.275 h1.78
  text "1" at 7.782,-31.693 h1.78
  text "2" at 92.254,-31.693 h1.78
  text "3" at 176.836,-31.693 h1.78
  text "4" at 261.545,-31.693 h1.78
  text "5" at 346,-31.693 h1.78
  text "6" at 430.709,-31.693 h1.78
M10 Fab Notes:
  drawing of 189 lines, arcs and shapes, not listed
  text "DESIGN INFORMATION" at 417.222,163.475 h0.76
  text "MIN. TRACK WIDTH:" at 400.85,160.119 h0.76
  text "8" at 428.694,160.119 h0.76
  text "MIL" at 432.625,160.119 h0.76
  text "1. 2-Oz Cu ON ALL LAYERS." at 273.678,159.491 h1.52
  text "8" at 428.694,157 h0.76
  text "MIN. CLEARANCE:" at 400.85,156.967 h0.76
  text "MIL" at 432.625,156.967 h0.76
  text "2. ALL VIAS ARE TENTED ON BOTH SIDES EXCEPT VIAS ON PAD." at 273.678,155.578 h1.52
  text "MIN. VIA PAD SIZE:" at 400.85,153.814 h0.76
  text "12" at 428.694,153.814 h0.76
  text "MIL" at 432.625,153.814 h0.76
  text "3. NON CONDUCTIVE VIA FILLING IS REQUIRED FOR ALL ON PAD VIAS." at 273.678,151.665 h1.52
  text "0.076mm (3MIL)" at 418.503,150.514 h0.76
  text "MINIMUM ANNULAR RING" at 392.487,150.306 h0.76
  text "EXTERNAL" at 436.486,150.306 h0.76
  text "4. U1 and U2 have the smallest vias with min annular ring of 3 mil (6mil hole)" at 273.678,148.234 h1.52
  text "PER" at 397.567,147.508 h0.76
  text "IPC-D-275 CLASS 2 LEVEL C" at 403.155,147.508 h0.76
  text "MIL, HOLES" at 440.956,144.956 h0.76
  text "+/-" at 430.988,144.738 h0.76
  text "+/-" at 452.68,144.738 h0.76
  text "REGISTRATION TOLERANCES:" at 392.487,144.711 h0.76
  text "METAL" at 422.962,144.711 h0.76
  text "5" at 437.597,144.711 h0.76
  text "3" at 458.755,144.711 h0.76
  text "MIL" at 461.708,144.711 h0.76
  text "5. All other vias have min annular ring of 5.9 mil (10 mil hole)" at 273.678,144.321 h1.52
  text "HOLE SIZE TOLERANCE (UNLESS OTHERWISE SPECIFIED):" at 392.487,142.214 h0.76
  text "+/-" at 452.68,142.141 h0.76
  text "3" at 458.755,142.114 h0.76
  text "MIL" at 461.708,142.114 h0.76
  text "MATERIAL:" at 390.588,138.618 h0.76
  text "FR-4 High Tg" at 415.644,135.353 h0.76
  text "X" at 411.975,135.15 h0.76
  text "FR-408" at 401.282,135.035 h0.76
  text "OTHER" at 439.077,135.035 h0.76
  text "62 MIL (1.6mm) +/-10%" at 409.412,131.402 h0.76
  text "X" at 406.362,131.34 h0.76
  text "THICKNESS:" at 392.487,131.194 h0.76
  text "OTHER" at 442.049,131.194 h0.76
  text "TOLERANCE:" at 392.487,127.68 h0.76
  text "X" at 414.033,127.68 h0.76
  text "ANSI IPC-6012 TYPE 3 CLASS 2" at 418.554,127.68 h0.76
  text "OTHER +/-" at 418.554,124.018 h0.76
  text "BOW & TWIST:" at 392.487,120.33 h0.76
  text "X" at 414.033,120.33 h0.76
  text "ANSI IPC-6012 TYPE 3 CLASS 2" at 418.554,120.33 h0.76
  text "OTHER +/-" at 418.554,116.604 h0.76
  text "DRILLING:" at 390.588,113.286 h0.76
  text "NC_DRILL FILES" at 435.318,110.615 h0.76
  text "REFERENCE:" at 392.487,110.515 h0.76
  text "X" at 409.181,110.512 h0.76
  text "AS SHOWN" at 413.702,110.515 h0.76
  text "X" at 432.067,110.515 h0.76
  text "OTHER" at 442.887,106.901 h0.76
  text "PTH COPPER THICKNESS:" at 392.479,106.812 h0.76
  text "X" at 421.416,106.812 h0.76
  text "20-30 um" at 424.667,106.812 h0.76
  text "BOARD FINISH:" at 390.588,103.063 h0.76
  text "SILKSCREEN:" at 394.531,100.266 h0.76
  text "X" at 418.859,100.266 h0.76
  text "TOP" at 421.83,100.266 h0.76
  text "X" at 431.813,100.266 h0.76
  text "BOTTOM" at 434.81,100.266 h0.76
  text "SILKSCREEN COLOR:" at 394.531,96.324 h0.76
  text "X" at 418.833,96.324 h0.76
  text "WHITE" at 421.83,96.324 h0.76
  text "OTHER" at 434.81,96.324 h0.76
  text "X" at 422.161,92.68 h0.76
  text "GREEN" at 425.158,92.68 h0.76
  text "OTHER" at 440.855,92.68 h0.76
  text "SOLDER RESIST COLOR:" at 394.531,92.506 h0.76
  text "X" at 422.161,88.762 h0.76
  text "MATTE" at 425.158,88.762 h0.76
  text "SEMI-GLOSS" at 440.843,88.746 h0.76
  text "IMMERSION GOLD (ENIG)" at 417.538,84.374 h0.76
  text "ENEPIG" at 451.511,84.19 h0.76
  text "SURFACE FINISH:" at 390.588,84.165 h0.76
  text "X" at 413.017,84.165 h0.76
  text "IMM. TIN/SILVER OR EQUIV" at 398.959,80.677 h0.76
  text "OTHER" at 435.318,80.577 h0.76
  text "ARRAY/PANEL:" at 390.588,76.631 h0.76
  text "CUT AND TRIM PER M1 BOARD OUTLINE" at 417.538,76.422 h0.76
  text "N.C. ROUTE" at 417.538,72.968 h0.76
  text "X" at 435.013,72.968 h0.76
  text "V. SCORE" at 439.534,72.968 h0.76
  text "CERTIFICATION:" at 390.588,69.688 h0.76
  text "MATERIALS AND WORKMANSHIP FOR ALL PCBS" at 409.003,69.688 h0.76
  text "TO MEET OR EXCEED THE REQUIREMENTS OF:" at 409.003,67.299 h0.76
  text "X" at 399.796,64.032 h0.76
  text "ANSI IPC-A-600F CLASS ->" at 403.047,64.032 h0.76
  text "X" at 444.906,64.032 h0.76
  text "2" at 447.7,64.032 h0.76
  text "1" at 439.699,63.994 h0.76
  text "3" at 456.692,63.994 h0.76
  text "X" at 420.421,60.281 h0.76
  text "RoHS" at 423.672,60.281 h0.76
  text "OTHER" at 440.04,60.281 h0.76
  text "PER ORDER" at 450.125,60.281 h0.76
  text "ALL BOARDS MUST MEET OR EXCEED UL94-V0 REQUIREMENTS." at 391.288,56.374 h0.76
  text "PCB MUST BEAR THE UL94V-0 UL REGISTERED MATERIAL ID NUMBER" at 391.288,53.426 h0.76
  text "ADDITIONAL REQUIREMENTS:" at 390.588,49.122 h0.76
  text "MICROSECTION:" at 392.487,46.401 h0.76
  text "YES" at 415.493,46.401 h0.76
  text "REQUIRED" at 437.375,42.735 h0.76
  text "BARE BOARD ELEC. TEST:" at 392.487,42.663 h0.76
  text "NONE" at 425.653,42.663 h0.76
  text "X" at 434.378,42.663 h0.76
  text "PER ORDER" at 452.412,42.663 h0.76
  text "XX MIL VIAS REQUIRE NON-CONDUCTIVE FILL AND PLANARIZE" at 396.758,37.457 h1.5
  text "XX MIL VIAS REQUIRE CONDUCTIVE FILL AND PLANARIZE" at 396.962,34.816 h0.76
  text "OUTER XX MIL TRACES REQUIRE 50 OHM SINGLE-ENDED IMPEDANCE" at 396.937,30.666 h1.47
  text "LAYER 2 & 3 (INNER LAYERS) XX MIL WIDE, XX MIL SPACE / TRACES REQUIRE 100 OHM DIFFERENTIAL IMPEDANCE" at 396.733,24.679 h0.76
  text ".Layer_Name" at -4.444,-20.006 h0.76
M11 Gerber Information:
  lines w0.254: -26.517,-21.826 141.123,-21.826 ; -26.517,-16.662 141.174,-16.662 ; -26.517,-11.497 -26.517,-26.991 75.21,-26.991 141.174,-26.991 141.174,-11.497 -26.504,-11.497 -26.504,-26.991 13.514,-26.991 ; 36.094,-26.991 36.094,-11.497 ; 68.276,-16.662 68.276,-11.497 ; 89.612,-16.662 89.612,-11.497 ; 105.411,-27.156 105.411,-22.004
  text "ALL ARTWORK VIEWED FROM TOP SIDE" at -24.904,-14.854 h0.76
  text "BOARD #:" at 37.999,-14.854 h0.76
  text ".PRJ_Number" at 51.855,-14.854 h0.76
  text "REV:" at 73.305,-14.854 h0.76
  text ".PCB_Rev" at 80.709,-14.854 h0.76
  text "SVN REV:" at 94.59,-14.854 h0.76
  text ".VersionControl_RevNumber" at 107.443,-14.854 h0.76
  text "LAYER NAME =" at -24.904,-20.006 h0.76
  text "PLOT NAME =" at -24.904,-25.234 h0.76
  text ".plot_File_Name" at -4.444,-25.234 h0.76
  text "GENERATED    :" at 38.05,-25.234 h0.76
  text ".Print_Date" at 60.135,-25.234 h0.76
  text ".Print_Time" at 78.652,-25.234 h0.76
  text "TEXAS INSTRUMENTS" at 110.77,-25.234 h0.76
M12 Stackup:
  drawing of 295 lines, arcs and shapes, not listed
  text "Layer" at 344.881,208.692 h1.52
  text "Name" at 355.292,208.692 h1.52
  text "Material" at 379.162,208.692 h1.52
  text "Thickness" at 401,208.692 h1.52
  text "Constant" at 417.506,208.692 h1.52
  text "Board Layer Stack" at 431.98,208.692 h1.52
  text "1" at 344.881,205.644 h1.52
  text "Top Overlay" at 355.292,205.644 h1.52
  text "2" at 344.881,202.596 h1.52
  text "Top Solder" at 355.292,202.596 h1.52
  text "Solder Resist" at 379.162,202.596 h1.52
  text "0.39mil" at 401,202.596 h1.52
  text "3.5" at 417.506,202.596 h1.52
  text "3" at 344.881,199.548 h1.52
  text "Top Layer" at 355.292,199.548 h1.52
  text "Copper" at 379.162,199.548 h1.52
  text "2.36mil" at 401,199.548 h1.52
  text "4" at 344.881,196.5 h1.52
  text "Dielectric 1" at 355.292,196.5 h1.52
  text "FR-4" at 379.162,196.5 h1.52
  text "14.17mil" at 401,196.5 h1.52
  text "4.2" at 417.506,196.5 h1.52
  text "5" at 344.881,193.452 h1.52
  text "Signal Layer 1" at 355.292,193.452 h1.52
  text "Copper" at 379.162,193.452 h1.52
  text "2.76mil" at 401,193.452 h1.52
  text "6" at 344.881,190.404 h1.52
  text "Dielectric 2" at 355.292,190.404 h1.52
  text "FR-4" at 379.162,190.404 h1.52
  text "27.95mil" at 401,190.404 h1.52
  text "4.2" at 417.506,190.404 h1.52
  text "7" at 344.881,187.356 h1.52
  text "Signal Layer 2" at 355.292,187.356 h1.52
  text "Copper" at 379.162,187.356 h1.52
  text "2.76mil" at 401,187.356 h1.52
  text "8" at 344.881,184.308 h1.52
  text "Dielectric 3" at 355.292,184.308 h1.52
  text "FR-4" at 379.162,184.308 h1.52
  text "14.17mil" at 401,184.308 h1.52
  text "4.2" at 417.506,184.308 h1.52
  text "9" at 344.881,181.26 h1.52
  text "Bottom Layer" at 355.292,181.26 h1.52
  text "Copper" at 379.162,181.26 h1.52
  text "2.36mil" at 401,181.26 h1.52
  text "10" at 344.881,178.212 h1.52
  text "Bottom Solder" at 355.292,178.212 h1.52
  text "Solder Resist" at 379.162,178.212 h1.52
  text "0.39mil" at 401,178.212 h1.52
  text "3.5" at 417.506,178.212 h1.52
  text "11" at 344.881,175.164 h1.52
  text "Bottom Overlay" at 355.292,175.164 h1.52
  text ".Layer_Name" at -4.444,-20.006 h0.76
M13 Component Bodies Top:
  text ".Layer_Name" at -4.444,-20.006 h0.76
M14 Component Bodies Bottom:
  text ".Layer_Name" at -4.444,-20.006 h0.76
M15 Courtyards Top:
  text ".Layer_Name" at -4.444,-20.006 h0.76
M16 Courtyards Bottom:
  text ".Layer_Name" at -4.444,-20.006 h0.76
Drill Drawing:
  drawing of 165 lines, arcs and shapes, not listed
  text "Symbol" at -10.637,490.39 h1.83
  text "Count" at 2.212,490.39 h1.83
  text "Hole Size" at 18.971,490.39 h1.83
  text "Plated" at 48.173,490.39 h1.83
  text "Hole Type" at 61.022,490.39 h1.83
  text "Drill Layer Pair" at 79.661,490.39 h1.83
  text "Via/Pad" at 117.749,490.39 h1.83
  text "Pad Shape" at 132.731,490.39 h1.83
  text "Template" at 160.409,490.39 h1.83
  text "Description" at 192.912,490.39 h1.83
  text "Hole Tolerance (+)" at 214.597,490.39 h1.83
  text "Hole Tolerance (-)" at 248.471,490.39 h1.83
  text "1" at 2.212,486.58 h1.52
  text "62.99mil (1.600mm)" at 18.971,486.58 h1.52
  text "NPTH" at 48.173,486.58 h1.52
  text "Round" at 61.022,486.58 h1.52
  text "Top Layer - Bottom Layer" at 79.661,486.58 h1.52
  text "Pad" at 117.749,486.58 h1.52
  text "Rounded" at 132.731,486.58 h1.52
  text "c100hn160" at 160.409,486.58 h1.52
  text "B" at -11.376,486.326 h1.69
  text "1" at 2.212,482.77 h1.52
  text "70.87mil (1.800mm)" at 18.971,482.77 h1.52
  text "NPTH" at 48.173,482.77 h1.52
  text "Round" at 61.022,482.77 h1.52
  text "Top Layer - Bottom Layer" at 79.661,482.77 h1.52
  text "Pad" at 117.749,482.77 h1.52
  text "Rounded" at 132.731,482.77 h1.52
  text "c152hn180" at 160.409,482.77 h1.52
  text "A" at -11.376,482.516 h1.69
  text "2" at 2.212,478.96 h1.52
  text "31.89mil (0.810mm)" at 18.971,478.96 h1.52
  text "PTH" at 48.173,478.96 h1.52
  text "Round" at 61.022,478.96 h1.52
  text "Top Layer - Bottom Layer" at 79.661,478.96 h1.52
  text "Pad" at 117.749,478.96 h1.52
  text "Rounded" at 132.731,478.96 h1.52
  text "c122h81(Tol5-5)" at 160.409,478.96 h1.52
  text "1.97mil (0.050mm)" at 214.597,478.96 h1.52
  text "1.97mil (0.050mm)" at 248.471,478.96 h1.52
  text "I" at -11.094,478.706 h1.69
  text "2" at 2.212,475.15 h1.52
  text "31.89mil (0.810mm)" at 18.971,475.15 h1.52
  text "PTH" at 48.173,475.15 h1.52
  text "Round" at 61.022,475.15 h1.52
  text "Top Layer - Bottom Layer" at 79.661,475.15 h1.52
  text "Pad" at 117.749,475.15 h1.52
  text "Rounded" at 132.731,475.15 h1.52
  text "c131h81m131p100131" at 160.409,475.15 h1.52
  text "M" at -11.376,474.896 h1.69
  text "2" at 2.212,471.34 h1.52
  text "55.12mil (1.400mm)" at 18.971,471.34 h1.52
  text "NPTH" at 48.173,471.34 h1.52
  text "Round" at 61.022,471.34 h1.52
  text "Top Layer - Bottom Layer" at 79.661,471.34 h1.52
  text "Pad" at 117.749,471.34 h1.52
  text "Rounded" at 132.731,471.34 h1.52
  text "c110hn140m150(Tol5-5)" at 160.409,471.34 h1.52
  text "1.97mil (0.050mm)" at 214.597,471.34 h1.52
  text "1.97mil (0.050mm)" at 248.471,471.34 h1.52
  text "C" at -11.376,471.086 h1.69
  text "2" at 2.212,467.53 h1.52
  text "55.12mil (1.400mm)" at 18.971,467.53 h1.52
  text "NPTH" at 48.173,467.53 h1.52
  text "Round" at 61.022,467.53 h1.52
  text "Top Layer - Bottom Layer" at 79.661,467.53 h1.52
  text "Pad" at 117.749,467.53 h1.52
  text "Rounded" at 132.731,467.53 h1.52
  text "c140hn140m140p100140" at 160.409,467.53 h1.52
  text "N" at -11.376,467.276 h1.69
  text "2" at 2.212,463.72 h1.52
  text "125.98mil (3.200mm)" at 18.971,463.72 h1.52
  text "PTH" at 48.173,463.72 h1.52
  text "Round" at 61.022,463.72 h1.52
  text "Top Layer - Bottom Layer" at 79.661,463.72 h1.52
  text "Pad" at 117.749,463.72 h1.52
  text "Rounded" at 132.731,463.72 h1.52
  text "c370h320" at 160.409,463.72 h1.52
  text "H" at -11.376,463.466 h1.69
  text "4" at 2.212,459.91 h1.52
  text "31.50mil (0.800mm)" at 18.971,459.91 h1.52
  text "PTH" at 48.173,459.91 h1.52
  text "Round" at 61.022,459.91 h1.52
  text "Top Layer - Bottom Layer" at 79.661,459.91 h1.52
  text "Pad" at 117.749,459.91 h1.52
  text "(Mixed)" at 132.731,459.91 h1.52
  text "(Mixed)" at 160.409,459.91 h1.52
  text "J" at -11.376,459.656 h1.69
  text "6" at 2.212,456.1 h1.52
  text "33.47mil (0.850mm)" at 18.971,456.1 h1.52
  text "PTH" at 48.173,456.1 h1.52
  text "Round" at 61.022,456.1 h1.52
  text "Top Layer - Bottom Layer" at 79.661,456.1 h1.52
  text "Pad" at 117.749,456.1 h1.52
  text "(Mixed)" at 132.731,456.1 h1.52
  text "(Mixed)" at 160.409,456.1 h1.52
  text "6" at 2.212,452.29 h1.52
  text "51.18mil (1.300mm)" at 18.971,452.29 h1.52
  text "PTH" at 48.173,452.29 h1.52
  text "Round" at 61.022,452.29 h1.52
  text "Top Layer - Bottom Layer" at 79.661,452.29 h1.52
  text "Pad" at 117.749,452.29 h1.52
  text "Rounded" at 132.731,452.29 h1.52
  text "c200h130m200p100200" at 160.409,452.29 h1.52
  text "E" at -11.376,452.036 h1.69
  text "6" at 2.212,448.48 h1.52
  text "152.76mil (3.880mm)" at 18.971,448.48 h1.52
  text "NPTH" at 48.173,448.48 h1.52
  text "Round" at 61.022,448.48 h1.52
  text "Top Layer - Bottom Layer" at 79.661,448.48 h1.52
  text "Pad" at 117.749,448.48 h1.52
  text "Rounded" at 132.731,448.48 h1.52
  text "c388hn388m388p100388" at 160.409,448.48 h1.52
  text "6" at 2.212,444.67 h1.52
  text "185.04mil (4.700mm)" at 18.971,444.67 h1.52
  text "PTH" at 48.173,444.67 h1.52
  text "Slot" at 61.022,444.67 h1.52
  text "Top Layer - Bottom Layer" at 79.661,444.67 h1.52
  text "Pad" at 117.749,444.67 h1.52
  text "Rounded Rectangle" at 132.731,444.67 h1.52
  text "(Mixed)" at 160.409,444.67 h1.52
  text "D" at -11.376,444.416 h1.69
  text "7" at 2.212,440.86 h1.52
  text "40.00mil (1.016mm)" at 18.971,440.86 h1.52
  text "PTH" at 48.173,440.86 h1.52
  text "Round" at 61.022,440.86 h1.52
  text "Top Layer - Bottom Layer" at 79.661,440.86 h1.52
  text "Pad" at 117.749,440.86 h1.52
  text "Rounded" at 132.731,440.86 h1.52
  text "c203h102" at 160.409,440.86 h1.52
  text "7" at 2.212,437.05 h1.52
  text "63.00mil (1.600mm)" at 18.971,437.05 h1.52
  text "PTH" at 48.173,437.05 h1.52
  text "Round" at 61.022,437.05 h1.52
  text "Top Layer - Bottom Layer" at 79.661,437.05 h1.52
  text "Pad" at 117.749,437.05 h1.52
  text "Rounded" at 132.731,437.05 h1.52
  text "c221h160" at 160.409,437.05 h1.52
  text "L" at -11.376,436.796 h1.69
  text "7" at 2.212,433.24 h1.52
  text "86.61mil (2.200mm)" at 18.971,433.24 h1.52
  text "PTH" at 48.173,433.24 h1.52
  text "Round" at 61.022,433.24 h1.52
  text "Top Layer - Bottom Layer" at 79.661,433.24 h1.52
  text "Pad" at 117.749,433.24 h1.52
  text "Rounded Rectangle" at 132.731,433.24 h1.52
  text "(Mixed)" at 160.409,433.24 h1.52
  text "8" at 2.212,429.43 h1.52
  text "31.00mil (0.787mm)" at 18.971,429.43 h1.52
  text "PTH" at 48.173,429.43 h1.52
  text "Round" at 61.022,429.43 h1.52
  text "Top Layer - Bottom Layer" at 79.661,429.43 h1.52
  text "Pad" at 117.749,429.43 h1.52
  text "(Mixed)" at 132.731,429.43 h1.52
  text "(Mixed)" at 160.409,429.43 h1.52
  text "10" at 2.212,425.62 h1.52
  text "30.00mil (0.762mm)" at 18.971,425.62 h1.52
  text "PTH" at 48.173,425.62 h1.52
  text "Round" at 61.022,425.62 h1.52
  text "Top Layer - Bottom Layer" at 79.661,425.62 h1.52
  text "Pad" at 117.749,425.62 h1.52
  text "(Mixed)" at 132.731,425.62 h1.52
  text "(Mixed)" at 160.409,425.62 h1.52
  text "11" at 2.212,421.81 h1.52
  text "173.23mil (4.400mm)" at 18.971,421.81 h1.52
  text "NPTH" at 48.173,421.81 h1.52
  text "Round" at 61.022,421.81 h1.52
  text "Top Layer - Bottom Layer" at 79.661,421.81 h1.52
  text "Pad" at 117.749,421.81 h1.52
  text "Rounded" at 132.731,421.81 h1.52
  text "c440hn440m440p100440" at 160.409,421.81 h1.52
  text "12" at 2.212,418 h1.52
  text "6.00mil (0.152mm)" at 18.971,418 h1.52
  text "PTH" at 48.173,418 h1.52
  text "Round" at 61.022,418 h1.52
  text "Top Layer - Bottom Layer" at 79.661,418 h1.52
  text "Via" at 117.749,418 h1.52
  text "Rounded" at 132.731,418 h1.52
  text "v30h15m0mx0" at 160.409,418 h1.52
  text "P" at -11.376,417.746 h1.69
  text "12" at 2.212,414.19 h1.52
  text "39.37mil (1.000mm)" at 18.971,414.19 h1.52
  text "NPTH" at 48.173,414.19 h1.52
  text "Slot" at 61.022,414.19 h1.52
  text "Top Layer - Bottom Layer" at 79.661,414.19 h1.52
  text "Pad" at 117.749,414.19 h1.52
  text "Rounded" at 132.731,414.19 h1.52
  text "c-100hn100_800" at 160.409,414.19 h1.52
  text "R" at -11.376,413.936 h1.69
  text "12" at 2.212,410.38 h1.52
  text "68.90mil (1.750mm)" at 18.971,410.38 h1.52
  text "PTH" at 48.173,410.38 h1.52
  text "Round" at 61.022,410.38 h1.52
  text "Top Layer - Bottom Layer" at 79.661,410.38 h1.52
  text "Pad" at 117.749,410.38 h1.52
  text "Rounded" at 132.731,410.38 h1.52
  text "c265h175m265p100265" at 160.409,410.38 h1.52
  text "12" at 2.212,406.57 h1.52
  text "98.43mil (2.500mm)" at 18.971,406.57 h1.52
  text "PTH" at 48.173,406.57 h1.52
  text "Round" at 61.022,406.57 h1.52
  text "Top Layer - Bottom Layer" at 79.661,406.57 h1.52
  text "Pad" at 117.749,406.57 h1.52
  text "Rounded" at 132.731,406.57 h1.52
  text "c380h250m380p100380" at 160.409,406.57 h1.52
  text "F" at -11.376,406.316 h1.69
  text "15" at 2.212,402.76 h1.52
  text "16.00mil (0.406mm)" at 18.971,402.76 h1.52
  text "PTH" at 48.173,402.76 h1.52
  text "Round" at 61.022,402.76 h1.52
  text "Top Layer - Bottom Layer" at 79.661,402.76 h1.52
  text "Via" at 117.749,402.76 h1.52
  text "Rounded" at 132.731,402.76 h1.52
  text "v86h41m0mx0" at 160.409,402.76 h1.52
  text "18" at 2.212,398.95 h1.52
  text "45.28mil (1.150mm)" at 18.971,398.95 h1.52
  text "PTH" at 48.173,398.95 h1.52
  text "Round" at 61.022,398.95 h1.52
  text "Top Layer - Bottom Layer" at 79.661,398.95 h1.52
  text "Pad" at 117.749,398.95 h1.52
  text "(Mixed)" at 132.731,398.95 h1.52
  text "(Mixed)" at 160.409,398.95 h1.52
  text "K" at -11.376,398.696 h1.69
  text "18" at 2.212,395.14 h1.52
  text "59.06mil (1.500mm)" at 18.971,395.14 h1.52
  text "PTH" at 48.173,395.14 h1.52
  text "Round" at 61.022,395.14 h1.52
  text "Top Layer - Bottom Layer" at 79.661,395.14 h1.52
  text "Pad" at 117.749,395.14 h1.52
  text "(Mixed)" at 132.731,395.14 h1.52
  text "(Mixed)" at 160.409,395.14 h1.52
  text "18" at 2.212,391.33 h1.52
  text "78.74mil (2.000mm)" at 18.971,391.33 h1.52
  text "PTH" at 48.173,391.33 h1.52
  text "Round" at 61.022,391.33 h1.52
  text "Top Layer - Bottom Layer" at 79.661,391.33 h1.52
  text "Pad" at 117.749,391.33 h1.52
  text "(Mixed)" at 132.731,391.33 h1.52
  text "(Mixed)" at 160.409,391.33 h1.52
  text "24" at 2.212,387.52 h1.52
  text "7.87mil (0.200mm)" at 18.971,387.52 h1.52
  text "PTH" at 48.173,387.52 h1.52
  text "Round" at 61.022,387.52 h1.52
  text "Top Layer - Bottom Layer" at 79.661,387.52 h1.52
  text "Via" at 117.749,387.52 h1.52
  text "Rounded" at 132.731,387.52 h1.52
  text "(Mixed)" at 160.409,387.52 h1.52
  text "O" at -11.376,387.266 h1.69
  text "24" at 2.212,383.71 h1.52
  text "66.93mil (1.700mm)" at 18.971,383.71 h1.52
  text "PTH" at 48.173,383.71 h1.52
  text "Round" at 61.022,383.71 h1.52
  text "Top Layer - Bottom Layer" at 79.661,383.71 h1.52
  text "Pad" at 117.749,383.71 h1.52
  text "(Mixed)" at 132.731,383.71 h1.52
  text "(Mixed)" at 160.409,383.71 h1.52
  text "30" at 2.212,379.9 h1.52
  text "70.08mil (1.780mm)" at 18.971,379.9 h1.52
  text "PTH" at 48.173,379.9 h1.52
  text "Round" at 61.022,379.9 h1.52
  text "Top Layer - Bottom Layer" at 79.661,379.9 h1.52
  text "Pad" at 117.749,379.9 h1.52
  text "Rounded Rectangle" at 132.731,379.9 h1.52
  text "(Mixed)" at 160.409,379.9 h1.52
  text "37" at 2.212,376.09 h1.52
  text "39.37mil (1.000mm)" at 18.971,376.09 h1.52
  text "PTH" at 48.173,376.09 h1.52
  text "Round" at 61.022,376.09 h1.52
  text "Top Layer - Bottom Layer" at 79.661,376.09 h1.52
  text "Pad" at 117.749,376.09 h1.52
  text "(Mixed)" at 132.731,376.09 h1.52
  text "(Mixed)" at 160.409,376.09 h1.52
  text "G" at -11.376,375.836 h1.69
  text "37" at 2.212,372.28 h1.52
  text "47.24mil (1.200mm)" at 18.971,372.28 h1.52
  text "PTH" at 48.173,372.28 h1.52
  text "Round" at 61.022,372.28 h1.52
  text "Top Layer - Bottom Layer" at 79.661,372.28 h1.52
  text "Pad" at 117.749,372.28 h1.52
  text "(Mixed)" at 132.731,372.28 h1.52
  text "(Mixed)" at 160.409,372.28 h1.52
  text "4018" at 2.212,368.47 h1.52
  text "14.00mil (0.356mm)" at 18.971,368.47 h1.52
  text "PTH" at 48.173,368.47 h1.52
  text "Round" at 61.022,368.47 h1.52
  text "Top Layer - Bottom Layer" at 79.661,368.47 h1.52
  text "Via" at 117.749,368.47 h1.52
  text "Rounded" at 132.731,368.47 h1.52
  text "(Mixed)" at 160.409,368.47 h1.52
  text "Q" at -11.376,368.216 h1.69
  text "4377 Total" at 2.212,364.66 h1.52
  text "Slot definitions :" at -10.637,360.978 h1.52
  text "Routed Path Length" at 15.593,360.978 h1.52
  text "= Calculated from tool start centre position to tool end centre position." at 43.601,360.978 h1.52
  text "Hole Length" at 15.593,358.438 h1.52
  text "= Routed Path Length + Tool Size = Slot length as defined in the PCB layout" at 33.19,358.438 h1.52
  text ".Layer_Name" at -4.444,-20.006 h0.76
M17 Embedded Cavity:
  text ".Layer_Name" at -4.444,-20.006 h0.76
M18 Embedded Assembly:
  text ".Layer_Name" at -4.444,-20.006 h0.76
M19 Embedded Keepout:
  text ".Layer_Name" at -4.698,-20.006 h0.76

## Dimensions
0,236.5 to 50,236.5 on M2 Board Dimensions
50,345 to 50,236.5 on M2 Board Dimensions
58.402,285.985 to 58.402,264.985 on M2 Board Dimensions
244.878,306.163 to 244.878,319.847 on M2 Board Dimensions
216.2,271.995 to 213.137,271.85 on M2 Board Dimensions
190.133,271.85 to 193.073,271.85 on M2 Board Dimensions
179.883,299.48 to 176.943,296.596 on M2 Board Dimensions
244.878,286.165 to 244.878,306.163 on M2 Board Dimensions
169.878,286.165 to 170.022,295.98 on M2 Board Dimensions
202.811,299.48 to 193.853,299.48 on M2 Board Dimensions
202.811,299.48 to 169.811,309.982 on M2 Board Dimensions
169.883,299.48 to 179.883,299.48 on M2 Board Dimensions
179.883,299.48 to 170.022,295.98 on M2 Board Dimensions
270,345 to 270.002,0 on M2 Board Dimensions
0,0 to 270,0 on M2 Board Dimensions
-19.1,-8.36 to 6.3,-8.36 on M2 Board Dimensions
